VERSION 5.8 ;
BUSBITCHARS "[]" ;
DIVIDERCHAR "/" ;
UNITS
    DATABASE MICRONS 1000 ;
END UNITS

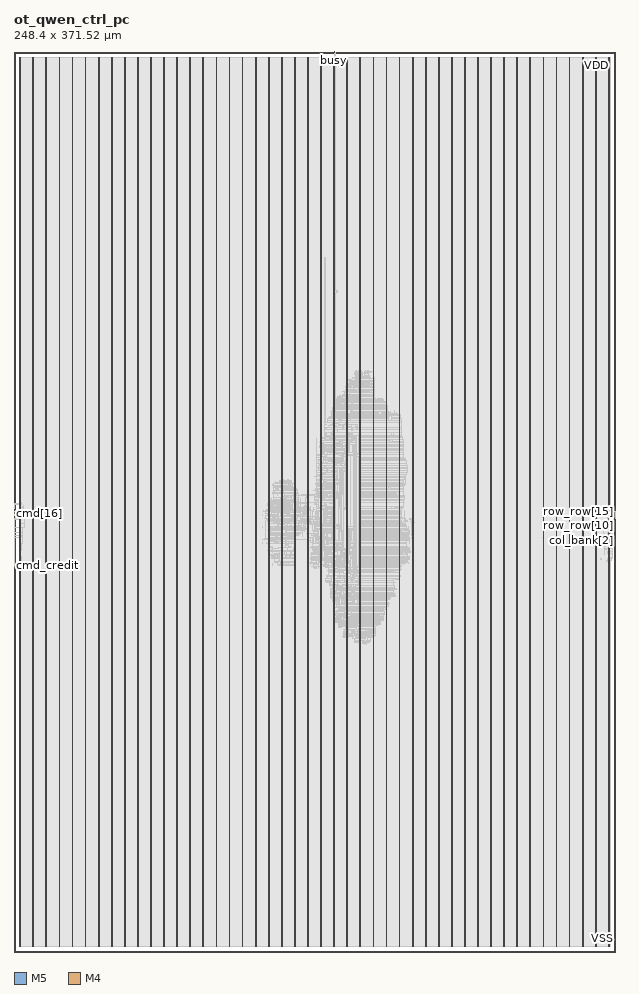
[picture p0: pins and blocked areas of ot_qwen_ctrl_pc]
MACRO ot_qwen_ctrl_pc
  FOREIGN ot_qwen_ctrl_pc 0 0 ;
  CLASS BLOCK ;
  SIZE 248.4 BY 371.52 ;
  PIN busy
    DIRECTION OUTPUT ;
    USE SIGNAL ;
    PORT
      LAYER M5 ;
        RECT  132.144 371.436 132.168 371.52 ;
    END
  END busy
  PIN clk
    DIRECTION INPUT ;
    USE SIGNAL ;
    PORT
      LAYER M5 ;
        RECT  132.24 371.436 132.264 371.52 ;
    END
  END clk
  PIN cmd[0]
    DIRECTION INPUT ;
    USE SIGNAL ;
    PORT
      LAYER M4 ;
        RECT  0 179.568 0.084 179.592 ;
    END
  END cmd[0]
  PIN cmd[10]
    DIRECTION INPUT ;
    USE SIGNAL ;
    PORT
      LAYER M4 ;
        RECT  0 180.528 0.084 180.552 ;
    END
  END cmd[10]
  PIN cmd[11]
    DIRECTION INPUT ;
    USE SIGNAL ;
    PORT
      LAYER M4 ;
        RECT  0 180.624 0.084 180.648 ;
    END
  END cmd[11]
  PIN cmd[12]
    DIRECTION INPUT ;
    USE SIGNAL ;
    PORT
      LAYER M4 ;
        RECT  0 180.72 0.084 180.744 ;
    END
  END cmd[12]
  PIN cmd[13]
    DIRECTION INPUT ;
    USE SIGNAL ;
    PORT
      LAYER M4 ;
        RECT  0 180.816 0.084 180.84 ;
    END
  END cmd[13]
  PIN cmd[14]
    DIRECTION INPUT ;
    USE SIGNAL ;
    PORT
      LAYER M4 ;
        RECT  0 180.912 0.084 180.936 ;
    END
  END cmd[14]
  PIN cmd[15]
    DIRECTION INPUT ;
    USE SIGNAL ;
    PORT
      LAYER M4 ;
        RECT  0 181.008 0.084 181.032 ;
    END
  END cmd[15]
  PIN cmd[16]
    DIRECTION INPUT ;
    USE SIGNAL ;
    PORT
      LAYER M4 ;
        RECT  0 181.104 0.084 181.128 ;
    END
  END cmd[16]
  PIN cmd[17]
    DIRECTION INPUT ;
    USE SIGNAL ;
    PORT
      LAYER M4 ;
        RECT  0 181.2 0.084 181.224 ;
    END
  END cmd[17]
  PIN cmd[18]
    DIRECTION INPUT ;
    USE SIGNAL ;
    PORT
      LAYER M4 ;
        RECT  0 181.296 0.084 181.32 ;
    END
  END cmd[18]
  PIN cmd[19]
    DIRECTION INPUT ;
    USE SIGNAL ;
    PORT
      LAYER M4 ;
        RECT  0 181.392 0.084 181.416 ;
    END
  END cmd[19]
  PIN cmd[1]
    DIRECTION INPUT ;
    USE SIGNAL ;
    PORT
      LAYER M4 ;
        RECT  0 179.664 0.084 179.688 ;
    END
  END cmd[1]
  PIN cmd[20]
    DIRECTION INPUT ;
    USE SIGNAL ;
    PORT
      LAYER M4 ;
        RECT  0 181.488 0.084 181.512 ;
    END
  END cmd[20]
  PIN cmd[21]
    DIRECTION INPUT ;
    USE SIGNAL ;
    PORT
      LAYER M4 ;
        RECT  0 181.584 0.084 181.608 ;
    END
  END cmd[21]
  PIN cmd[22]
    DIRECTION INPUT ;
    USE SIGNAL ;
    PORT
      LAYER M4 ;
        RECT  0 181.68 0.084 181.704 ;
    END
  END cmd[22]
  PIN cmd[23]
    DIRECTION INPUT ;
    USE SIGNAL ;
    PORT
      LAYER M4 ;
        RECT  0 181.776 0.084 181.8 ;
    END
  END cmd[23]
  PIN cmd[24]
    DIRECTION INPUT ;
    USE SIGNAL ;
    PORT
      LAYER M4 ;
        RECT  0 181.872 0.084 181.896 ;
    END
  END cmd[24]
  PIN cmd[25]
    DIRECTION INPUT ;
    USE SIGNAL ;
    PORT
      LAYER M4 ;
        RECT  0 181.968 0.084 181.992 ;
    END
  END cmd[25]
  PIN cmd[26]
    DIRECTION INPUT ;
    USE SIGNAL ;
    PORT
      LAYER M4 ;
        RECT  0 182.064 0.084 182.088 ;
    END
  END cmd[26]
  PIN cmd[27]
    DIRECTION INPUT ;
    USE SIGNAL ;
    PORT
      LAYER M4 ;
        RECT  0 182.16 0.084 182.184 ;
    END
  END cmd[27]
  PIN cmd[28]
    DIRECTION INPUT ;
    USE SIGNAL ;
    PORT
      LAYER M4 ;
        RECT  0 182.256 0.084 182.28 ;
    END
  END cmd[28]
  PIN cmd[29]
    DIRECTION INPUT ;
    USE SIGNAL ;
    PORT
      LAYER M4 ;
        RECT  0 182.352 0.084 182.376 ;
    END
  END cmd[29]
  PIN cmd[2]
    DIRECTION INPUT ;
    USE SIGNAL ;
    PORT
      LAYER M4 ;
        RECT  0 179.76 0.084 179.784 ;
    END
  END cmd[2]
  PIN cmd[30]
    DIRECTION INPUT ;
    USE SIGNAL ;
    PORT
      LAYER M4 ;
        RECT  0 182.448 0.084 182.472 ;
    END
  END cmd[30]
  PIN cmd[31]
    DIRECTION INPUT ;
    USE SIGNAL ;
    PORT
      LAYER M4 ;
        RECT  0 182.544 0.084 182.568 ;
    END
  END cmd[31]
  PIN cmd[3]
    DIRECTION INPUT ;
    USE SIGNAL ;
    PORT
      LAYER M4 ;
        RECT  0 179.856 0.084 179.88 ;
    END
  END cmd[3]
  PIN cmd[4]
    DIRECTION INPUT ;
    USE SIGNAL ;
    PORT
      LAYER M4 ;
        RECT  0 179.952 0.084 179.976 ;
    END
  END cmd[4]
  PIN cmd[5]
    DIRECTION INPUT ;
    USE SIGNAL ;
    PORT
      LAYER M4 ;
        RECT  0 180.048 0.084 180.072 ;
    END
  END cmd[5]
  PIN cmd[6]
    DIRECTION INPUT ;
    USE SIGNAL ;
    PORT
      LAYER M4 ;
        RECT  0 180.144 0.084 180.168 ;
    END
  END cmd[6]
  PIN cmd[7]
    DIRECTION INPUT ;
    USE SIGNAL ;
    PORT
      LAYER M4 ;
        RECT  0 180.24 0.084 180.264 ;
    END
  END cmd[7]
  PIN cmd[8]
    DIRECTION INPUT ;
    USE SIGNAL ;
    PORT
      LAYER M4 ;
        RECT  0 180.336 0.084 180.36 ;
    END
  END cmd[8]
  PIN cmd[9]
    DIRECTION INPUT ;
    USE SIGNAL ;
    PORT
      LAYER M4 ;
        RECT  0 180.432 0.084 180.456 ;
    END
  END cmd[9]
  PIN cmd_credit
    DIRECTION OUTPUT ;
    USE SIGNAL ;
    PORT
      LAYER M4 ;
        RECT  0 159.6 0.084 159.624 ;
    END
  END cmd_credit
  PIN cmd_v
    DIRECTION INPUT ;
    USE SIGNAL ;
    PORT
      LAYER M4 ;
        RECT  0 159.696 0.084 159.72 ;
    END
  END cmd_v
  PIN col_bank[0]
    DIRECTION OUTPUT ;
    USE SIGNAL ;
    PORT
      LAYER M4 ;
        RECT  248.316 169.68 248.4 169.704 ;
    END
  END col_bank[0]
  PIN col_bank[1]
    DIRECTION OUTPUT ;
    USE SIGNAL ;
    PORT
      LAYER M4 ;
        RECT  248.316 169.776 248.4 169.8 ;
    END
  END col_bank[1]
  PIN col_bank[2]
    DIRECTION OUTPUT ;
    USE SIGNAL ;
    PORT
      LAYER M4 ;
        RECT  248.316 169.872 248.4 169.896 ;
    END
  END col_bank[2]
  PIN col_bank[3]
    DIRECTION OUTPUT ;
    USE SIGNAL ;
    PORT
      LAYER M4 ;
        RECT  248.316 169.968 248.4 169.992 ;
    END
  END col_bank[3]
  PIN col_bank[4]
    DIRECTION OUTPUT ;
    USE SIGNAL ;
    PORT
      LAYER M4 ;
        RECT  248.316 170.064 248.4 170.088 ;
    END
  END col_bank[4]
  PIN col_col[0]
    DIRECTION OUTPUT ;
    USE SIGNAL ;
    PORT
      LAYER M4 ;
        RECT  248.316 170.16 248.4 170.184 ;
    END
  END col_col[0]
  PIN col_col[1]
    DIRECTION OUTPUT ;
    USE SIGNAL ;
    PORT
      LAYER M4 ;
        RECT  248.316 170.256 248.4 170.28 ;
    END
  END col_col[1]
  PIN col_col[2]
    DIRECTION OUTPUT ;
    USE SIGNAL ;
    PORT
      LAYER M4 ;
        RECT  248.316 170.352 248.4 170.376 ;
    END
  END col_col[2]
  PIN col_col[3]
    DIRECTION OUTPUT ;
    USE SIGNAL ;
    PORT
      LAYER M4 ;
        RECT  248.316 170.448 248.4 170.472 ;
    END
  END col_col[3]
  PIN col_col[4]
    DIRECTION OUTPUT ;
    USE SIGNAL ;
    PORT
      LAYER M4 ;
        RECT  248.316 170.544 248.4 170.568 ;
    END
  END col_col[4]
  PIN col_v
    DIRECTION OUTPUT ;
    USE SIGNAL ;
    PORT
      LAYER M4 ;
        RECT  248.316 170.64 248.4 170.664 ;
    END
  END col_v
  PIN col_we
    DIRECTION OUTPUT ;
    USE SIGNAL ;
    PORT
      LAYER M4 ;
        RECT  248.316 170.736 248.4 170.76 ;
    END
  END col_we
  PIN fault
    DIRECTION OUTPUT ;
    USE SIGNAL ;
    PORT
      LAYER M5 ;
        RECT  132.336 371.436 132.36 371.52 ;
    END
  END fault
  PIN read_credit[0]
    DIRECTION INPUT ;
    USE SIGNAL ;
    PORT
      LAYER M4 ;
        RECT  0 159.792 0.084 159.816 ;
    END
  END read_credit[0]
  PIN read_credit[1]
    DIRECTION INPUT ;
    USE SIGNAL ;
    PORT
      LAYER M4 ;
        RECT  0 159.888 0.084 159.912 ;
    END
  END read_credit[1]
  PIN read_credit[2]
    DIRECTION INPUT ;
    USE SIGNAL ;
    PORT
      LAYER M4 ;
        RECT  0 159.984 0.084 160.008 ;
    END
  END read_credit[2]
  PIN row_bank[0]
    DIRECTION OUTPUT ;
    USE SIGNAL ;
    PORT
      LAYER M4 ;
        RECT  248.316 170.832 248.4 170.856 ;
    END
  END row_bank[0]
  PIN row_bank[1]
    DIRECTION OUTPUT ;
    USE SIGNAL ;
    PORT
      LAYER M4 ;
        RECT  248.316 170.928 248.4 170.952 ;
    END
  END row_bank[1]
  PIN row_bank[2]
    DIRECTION OUTPUT ;
    USE SIGNAL ;
    PORT
      LAYER M4 ;
        RECT  248.316 171.024 248.4 171.048 ;
    END
  END row_bank[2]
  PIN row_bank[3]
    DIRECTION OUTPUT ;
    USE SIGNAL ;
    PORT
      LAYER M4 ;
        RECT  248.316 171.12 248.4 171.144 ;
    END
  END row_bank[3]
  PIN row_bank[4]
    DIRECTION OUTPUT ;
    USE SIGNAL ;
    PORT
      LAYER M4 ;
        RECT  248.316 171.216 248.4 171.24 ;
    END
  END row_bank[4]
  PIN row_op[0]
    DIRECTION OUTPUT ;
    USE SIGNAL ;
    PORT
      LAYER M4 ;
        RECT  248.316 171.312 248.4 171.336 ;
    END
  END row_op[0]
  PIN row_op[1]
    DIRECTION OUTPUT ;
    USE SIGNAL ;
    PORT
      LAYER M4 ;
        RECT  248.316 171.408 248.4 171.432 ;
    END
  END row_op[1]
  PIN row_op[2]
    DIRECTION OUTPUT ;
    USE SIGNAL ;
    PORT
      LAYER M4 ;
        RECT  248.316 171.504 248.4 171.528 ;
    END
  END row_op[2]
  PIN row_row[0]
    DIRECTION OUTPUT ;
    USE SIGNAL ;
    PORT
      LAYER M4 ;
        RECT  248.316 171.6 248.4 171.624 ;
    END
  END row_row[0]
  PIN row_row[10]
    DIRECTION OUTPUT ;
    USE SIGNAL ;
    PORT
      LAYER M4 ;
        RECT  248.316 172.56 248.4 172.584 ;
    END
  END row_row[10]
  PIN row_row[11]
    DIRECTION OUTPUT ;
    USE SIGNAL ;
    PORT
      LAYER M4 ;
        RECT  248.316 172.656 248.4 172.68 ;
    END
  END row_row[11]
  PIN row_row[12]
    DIRECTION OUTPUT ;
    USE SIGNAL ;
    PORT
      LAYER M4 ;
        RECT  248.316 178.128 248.4 178.152 ;
    END
  END row_row[12]
  PIN row_row[13]
    DIRECTION OUTPUT ;
    USE SIGNAL ;
    PORT
      LAYER M4 ;
        RECT  248.316 178.224 248.4 178.248 ;
    END
  END row_row[13]
  PIN row_row[14]
    DIRECTION OUTPUT ;
    USE SIGNAL ;
    PORT
      LAYER M4 ;
        RECT  248.316 178.32 248.4 178.344 ;
    END
  END row_row[14]
  PIN row_row[15]
    DIRECTION OUTPUT ;
    USE SIGNAL ;
    PORT
      LAYER M4 ;
        RECT  248.316 178.416 248.4 178.44 ;
    END
  END row_row[15]
  PIN row_row[16]
    DIRECTION OUTPUT ;
    USE SIGNAL ;
    PORT
      LAYER M4 ;
        RECT  248.316 178.512 248.4 178.536 ;
    END
  END row_row[16]
  PIN row_row[17]
    DIRECTION OUTPUT ;
    USE SIGNAL ;
    PORT
      LAYER M4 ;
        RECT  248.316 178.608 248.4 178.632 ;
    END
  END row_row[17]
  PIN row_row[18]
    DIRECTION OUTPUT ;
    USE SIGNAL ;
    PORT
      LAYER M4 ;
        RECT  248.316 178.704 248.4 178.728 ;
    END
  END row_row[18]
  PIN row_row[1]
    DIRECTION OUTPUT ;
    USE SIGNAL ;
    PORT
      LAYER M4 ;
        RECT  248.316 171.696 248.4 171.72 ;
    END
  END row_row[1]
  PIN row_row[2]
    DIRECTION OUTPUT ;
    USE SIGNAL ;
    PORT
      LAYER M4 ;
        RECT  248.316 171.792 248.4 171.816 ;
    END
  END row_row[2]
  PIN row_row[3]
    DIRECTION OUTPUT ;
    USE SIGNAL ;
    PORT
      LAYER M4 ;
        RECT  248.316 171.888 248.4 171.912 ;
    END
  END row_row[3]
  PIN row_row[4]
    DIRECTION OUTPUT ;
    USE SIGNAL ;
    PORT
      LAYER M4 ;
        RECT  248.316 171.984 248.4 172.008 ;
    END
  END row_row[4]
  PIN row_row[5]
    DIRECTION OUTPUT ;
    USE SIGNAL ;
    PORT
      LAYER M4 ;
        RECT  248.316 172.08 248.4 172.104 ;
    END
  END row_row[5]
  PIN row_row[6]
    DIRECTION OUTPUT ;
    USE SIGNAL ;
    PORT
      LAYER M4 ;
        RECT  248.316 172.176 248.4 172.2 ;
    END
  END row_row[6]
  PIN row_row[7]
    DIRECTION OUTPUT ;
    USE SIGNAL ;
    PORT
      LAYER M4 ;
        RECT  248.316 172.272 248.4 172.296 ;
    END
  END row_row[7]
  PIN row_row[8]
    DIRECTION OUTPUT ;
    USE SIGNAL ;
    PORT
      LAYER M4 ;
        RECT  248.316 172.368 248.4 172.392 ;
    END
  END row_row[8]
  PIN row_row[9]
    DIRECTION OUTPUT ;
    USE SIGNAL ;
    PORT
      LAYER M4 ;
        RECT  248.316 172.464 248.4 172.488 ;
    END
  END row_row[9]
  PIN row_v
    DIRECTION OUTPUT ;
    USE SIGNAL ;
    PORT
      LAYER M4 ;
        RECT  248.316 178.8 248.4 178.824 ;
    END
  END row_v
  PIN rst_n
    DIRECTION INPUT ;
    USE SIGNAL ;
    PORT
      LAYER M5 ;
        RECT  132.432 371.436 132.456 371.52 ;
    END
  END rst_n
  PIN VDD
    DIRECTION INOUT ;
    USE POWER ;
    PORT
      LAYER M5 ;
        RECT  245.592 2.151 245.712 369.369 ;
        RECT  240.192 2.151 240.312 369.369 ;
        RECT  234.792 2.151 234.912 369.369 ;
        RECT  229.392 2.151 229.512 369.369 ;
        RECT  223.992 2.151 224.112 369.369 ;
        RECT  218.592 2.151 218.712 369.369 ;
        RECT  213.192 2.151 213.312 369.369 ;
        RECT  207.792 2.151 207.912 369.369 ;
        RECT  202.392 2.151 202.512 369.369 ;
        RECT  196.992 2.151 197.112 369.369 ;
        RECT  191.592 2.151 191.712 369.369 ;
        RECT  186.192 2.151 186.312 369.369 ;
        RECT  180.792 2.151 180.912 369.369 ;
        RECT  175.392 2.151 175.512 369.369 ;
        RECT  169.992 2.151 170.112 369.369 ;
        RECT  164.592 2.151 164.712 369.369 ;
        RECT  159.192 2.151 159.312 369.369 ;
        RECT  153.792 2.151 153.912 369.369 ;
        RECT  148.392 2.151 148.512 369.369 ;
        RECT  142.992 2.151 143.112 369.369 ;
        RECT  137.592 2.151 137.712 369.369 ;
        RECT  132.192 2.151 132.312 369.369 ;
        RECT  126.792 2.151 126.912 369.369 ;
        RECT  121.392 2.151 121.512 369.369 ;
        RECT  115.992 2.151 116.112 369.369 ;
        RECT  110.592 2.151 110.712 369.369 ;
        RECT  105.192 2.151 105.312 369.369 ;
        RECT  99.792 2.151 99.912 369.369 ;
        RECT  94.392 2.151 94.512 369.369 ;
        RECT  88.992 2.151 89.112 369.369 ;
        RECT  83.592 2.151 83.712 369.369 ;
        RECT  78.192 2.151 78.312 369.369 ;
        RECT  72.792 2.151 72.912 369.369 ;
        RECT  67.392 2.151 67.512 369.369 ;
        RECT  61.992 2.151 62.112 369.369 ;
        RECT  56.592 2.151 56.712 369.369 ;
        RECT  51.192 2.151 51.312 369.369 ;
        RECT  45.792 2.151 45.912 369.369 ;
        RECT  40.392 2.151 40.512 369.369 ;
        RECT  34.992 2.151 35.112 369.369 ;
        RECT  29.592 2.151 29.712 369.369 ;
        RECT  24.192 2.151 24.312 369.369 ;
        RECT  18.792 2.151 18.912 369.369 ;
        RECT  13.392 2.151 13.512 369.369 ;
        RECT  7.992 2.151 8.112 369.369 ;
        RECT  2.592 2.151 2.712 369.369 ;
    END
  END VDD
  PIN VSS
    DIRECTION INOUT ;
    USE GROUND ;
    PORT
      LAYER M5 ;
        RECT  245.4 2.137 245.52 369.383 ;
        RECT  240 2.137 240.12 369.383 ;
        RECT  234.6 2.137 234.72 369.383 ;
        RECT  229.2 2.137 229.32 369.383 ;
        RECT  223.8 2.137 223.92 369.383 ;
        RECT  218.4 2.137 218.52 369.383 ;
        RECT  213 2.137 213.12 369.383 ;
        RECT  207.6 2.137 207.72 369.383 ;
        RECT  202.2 2.137 202.32 369.383 ;
        RECT  196.8 2.137 196.92 369.383 ;
        RECT  191.4 2.137 191.52 369.383 ;
        RECT  186 2.137 186.12 369.383 ;
        RECT  180.6 2.137 180.72 369.383 ;
        RECT  175.2 2.137 175.32 369.383 ;
        RECT  169.8 2.137 169.92 369.383 ;
        RECT  164.4 2.137 164.52 369.383 ;
        RECT  159 2.137 159.12 369.383 ;
        RECT  153.6 2.137 153.72 369.383 ;
        RECT  148.2 2.137 148.32 369.383 ;
        RECT  142.8 2.137 142.92 369.383 ;
        RECT  137.4 2.137 137.52 369.383 ;
        RECT  132 2.137 132.12 369.383 ;
        RECT  126.6 2.137 126.72 369.383 ;
        RECT  121.2 2.137 121.32 369.383 ;
        RECT  115.8 2.137 115.92 369.383 ;
        RECT  110.4 2.137 110.52 369.383 ;
        RECT  105 2.137 105.12 369.383 ;
        RECT  99.6 2.137 99.72 369.383 ;
        RECT  94.2 2.137 94.32 369.383 ;
        RECT  88.8 2.137 88.92 369.383 ;
        RECT  83.4 2.137 83.52 369.383 ;
        RECT  78 2.137 78.12 369.383 ;
        RECT  72.6 2.137 72.72 369.383 ;
        RECT  67.2 2.137 67.32 369.383 ;
        RECT  61.8 2.137 61.92 369.383 ;
        RECT  56.4 2.137 56.52 369.383 ;
        RECT  51 2.137 51.12 369.383 ;
        RECT  45.6 2.137 45.72 369.383 ;
        RECT  40.2 2.137 40.32 369.383 ;
        RECT  34.8 2.137 34.92 369.383 ;
        RECT  29.4 2.137 29.52 369.383 ;
        RECT  24 2.137 24.12 369.383 ;
        RECT  18.6 2.137 18.72 369.383 ;
        RECT  13.2 2.137 13.32 369.383 ;
        RECT  7.8 2.137 7.92 369.383 ;
        RECT  2.4 2.137 2.52 369.383 ;
    END
  END VSS
  OBS
    LAYER RVTN ;
     RECT  2.16 2.16 246.24 2.295 ;
     RECT  2.16 2.565 246.24 2.835 ;
     RECT  2.16 3.105 246.24 3.375 ;
     RECT  2.16 3.645 246.24 3.915 ;
     RECT  2.16 4.185 246.24 4.455 ;
     RECT  2.16 4.725 246.24 4.995 ;
     RECT  2.16 5.265 246.24 5.535 ;
     RECT  2.16 5.805 246.24 6.075 ;
     RECT  2.16 6.345 246.24 6.615 ;
     RECT  2.16 6.885 246.24 7.155 ;
     RECT  2.16 7.425 246.24 7.695 ;
     RECT  2.16 7.965 246.24 8.235 ;
     RECT  2.16 8.505 246.24 8.775 ;
     RECT  2.16 9.045 246.24 9.315 ;
     RECT  2.16 9.585 246.24 9.855 ;
     RECT  2.16 10.125 246.24 10.395 ;
     RECT  2.16 10.665 246.24 10.935 ;
     RECT  2.16 11.205 246.24 11.475 ;
     RECT  2.16 11.745 246.24 12.015 ;
     RECT  2.16 12.285 246.24 12.555 ;
     RECT  2.16 12.825 246.24 13.095 ;
     RECT  2.16 13.365 246.24 13.635 ;
     RECT  2.16 13.905 246.24 14.175 ;
     RECT  2.16 14.445 246.24 14.715 ;
     RECT  2.16 14.985 246.24 15.255 ;
     RECT  2.16 15.525 246.24 15.795 ;
     RECT  2.16 16.065 246.24 16.335 ;
     RECT  2.16 16.605 246.24 16.875 ;
     RECT  2.16 17.145 246.24 17.415 ;
     RECT  2.16 17.685 246.24 17.955 ;
     RECT  2.16 18.225 246.24 18.495 ;
     RECT  2.16 18.765 246.24 19.035 ;
     RECT  2.16 19.305 246.24 19.575 ;
     RECT  2.16 19.845 246.24 20.115 ;
     RECT  2.16 20.385 246.24 20.655 ;
     RECT  2.16 20.925 246.24 21.195 ;
     RECT  2.16 21.465 246.24 21.735 ;
     RECT  2.16 22.005 246.24 22.275 ;
     RECT  2.16 22.545 246.24 22.815 ;
     RECT  2.16 23.085 246.24 23.355 ;
     RECT  2.16 23.625 246.24 23.895 ;
     RECT  2.16 24.165 246.24 24.435 ;
     RECT  2.16 24.705 246.24 24.975 ;
     RECT  2.16 25.245 246.24 25.515 ;
     RECT  2.16 25.785 246.24 26.055 ;
     RECT  2.16 26.325 246.24 26.595 ;
     RECT  2.16 26.865 246.24 27.135 ;
     RECT  2.16 27.405 246.24 27.675 ;
     RECT  2.16 27.945 246.24 28.215 ;
     RECT  2.16 28.485 246.24 28.755 ;
     RECT  2.16 29.025 246.24 29.295 ;
     RECT  2.16 29.565 246.24 29.835 ;
     RECT  2.16 30.105 246.24 30.375 ;
     RECT  2.16 30.645 246.24 30.915 ;
     RECT  2.16 31.185 246.24 31.455 ;
     RECT  2.16 31.725 246.24 31.995 ;
     RECT  2.16 32.265 246.24 32.535 ;
     RECT  2.16 32.805 246.24 33.075 ;
     RECT  2.16 33.345 246.24 33.615 ;
     RECT  2.16 33.885 246.24 34.155 ;
     RECT  2.16 34.425 246.24 34.695 ;
     RECT  2.16 34.965 246.24 35.235 ;
     RECT  2.16 35.505 246.24 35.775 ;
     RECT  2.16 36.045 246.24 36.315 ;
     RECT  2.16 36.585 246.24 36.855 ;
     RECT  2.16 37.125 246.24 37.395 ;
     RECT  2.16 37.665 246.24 37.935 ;
     RECT  2.16 38.205 246.24 38.475 ;
     RECT  2.16 38.745 246.24 39.015 ;
     RECT  2.16 39.285 246.24 39.555 ;
     RECT  2.16 39.825 246.24 40.095 ;
     RECT  2.16 40.365 246.24 40.635 ;
     RECT  2.16 40.905 246.24 41.175 ;
     RECT  2.16 41.445 246.24 41.715 ;
     RECT  2.16 41.985 246.24 42.255 ;
     RECT  2.16 42.525 246.24 42.795 ;
     RECT  2.16 43.065 246.24 43.335 ;
     RECT  2.16 43.605 246.24 43.875 ;
     RECT  2.16 44.145 246.24 44.415 ;
     RECT  2.16 44.685 246.24 44.955 ;
     RECT  2.16 45.225 246.24 45.495 ;
     RECT  2.16 45.765 246.24 46.035 ;
     RECT  2.16 46.305 246.24 46.575 ;
     RECT  2.16 46.845 246.24 47.115 ;
     RECT  2.16 47.385 246.24 47.655 ;
     RECT  2.16 47.925 246.24 48.195 ;
     RECT  2.16 48.465 246.24 48.735 ;
     RECT  2.16 49.005 246.24 49.275 ;
     RECT  2.16 49.545 246.24 49.815 ;
     RECT  2.16 50.085 246.24 50.355 ;
     RECT  2.16 50.625 246.24 50.895 ;
     RECT  2.16 51.165 246.24 51.435 ;
     RECT  2.16 51.705 246.24 51.975 ;
     RECT  2.16 52.245 246.24 52.515 ;
     RECT  2.16 52.785 246.24 53.055 ;
     RECT  2.16 53.325 246.24 53.595 ;
     RECT  2.16 53.865 246.24 54.135 ;
     RECT  2.16 54.405 246.24 54.675 ;
     RECT  2.16 54.945 246.24 55.215 ;
     RECT  2.16 55.485 246.24 55.755 ;
     RECT  2.16 56.025 246.24 56.295 ;
     RECT  2.16 56.565 246.24 56.835 ;
     RECT  2.16 57.105 246.24 57.375 ;
     RECT  2.16 57.645 246.24 57.915 ;
     RECT  2.16 58.185 246.24 58.455 ;
     RECT  2.16 58.725 246.24 58.995 ;
     RECT  2.16 59.265 246.24 59.535 ;
     RECT  2.16 59.805 246.24 60.075 ;
     RECT  2.16 60.345 246.24 60.615 ;
     RECT  2.16 60.885 246.24 61.155 ;
     RECT  2.16 61.425 246.24 61.695 ;
     RECT  2.16 61.965 246.24 62.235 ;
     RECT  2.16 62.505 246.24 62.775 ;
     RECT  2.16 63.045 246.24 63.315 ;
     RECT  2.16 63.585 246.24 63.855 ;
     RECT  2.16 64.125 246.24 64.395 ;
     RECT  2.16 64.665 246.24 64.935 ;
     RECT  2.16 65.205 246.24 65.475 ;
     RECT  2.16 65.745 246.24 66.015 ;
     RECT  2.16 66.285 246.24 66.555 ;
     RECT  2.16 66.825 246.24 67.095 ;
     RECT  2.16 67.365 246.24 67.635 ;
     RECT  2.16 67.905 246.24 68.175 ;
     RECT  2.16 68.445 246.24 68.715 ;
     RECT  2.16 68.985 246.24 69.255 ;
     RECT  2.16 69.525 246.24 69.795 ;
     RECT  2.16 70.065 246.24 70.335 ;
     RECT  2.16 70.605 246.24 70.875 ;
     RECT  2.16 71.145 246.24 71.415 ;
     RECT  2.16 71.685 246.24 71.955 ;
     RECT  2.16 72.225 246.24 72.495 ;
     RECT  2.16 72.765 246.24 73.035 ;
     RECT  2.16 73.305 246.24 73.575 ;
     RECT  2.16 73.845 246.24 74.115 ;
     RECT  2.16 74.385 246.24 74.655 ;
     RECT  2.16 74.925 246.24 75.195 ;
     RECT  2.16 75.465 246.24 75.735 ;
     RECT  2.16 76.005 246.24 76.275 ;
     RECT  2.16 76.545 246.24 76.815 ;
     RECT  2.16 77.085 246.24 77.355 ;
     RECT  2.16 77.625 246.24 77.895 ;
     RECT  2.16 78.165 246.24 78.435 ;
     RECT  2.16 78.705 246.24 78.975 ;
     RECT  2.16 79.245 246.24 79.515 ;
     RECT  2.16 79.785 246.24 80.055 ;
     RECT  2.16 80.325 246.24 80.595 ;
     RECT  2.16 80.865 246.24 81.135 ;
     RECT  2.16 81.405 246.24 81.675 ;
     RECT  2.16 81.945 246.24 82.215 ;
     RECT  2.16 82.485 246.24 82.755 ;
     RECT  2.16 83.025 246.24 83.295 ;
     RECT  2.16 83.565 246.24 83.835 ;
     RECT  2.16 84.105 246.24 84.375 ;
     RECT  2.16 84.645 246.24 84.915 ;
     RECT  2.16 85.185 246.24 85.455 ;
     RECT  2.16 85.725 246.24 85.995 ;
     RECT  2.16 86.265 246.24 86.535 ;
     RECT  2.16 86.805 246.24 87.075 ;
     RECT  2.16 87.345 246.24 87.615 ;
     RECT  2.16 87.885 246.24 88.155 ;
     RECT  2.16 88.425 246.24 88.695 ;
     RECT  2.16 88.965 246.24 89.235 ;
     RECT  2.16 89.505 246.24 89.775 ;
     RECT  2.16 90.045 246.24 90.315 ;
     RECT  2.16 90.585 246.24 90.855 ;
     RECT  2.16 91.125 246.24 91.395 ;
     RECT  2.16 91.665 246.24 91.935 ;
     RECT  2.16 92.205 246.24 92.475 ;
     RECT  2.16 92.745 246.24 93.015 ;
     RECT  2.16 93.285 246.24 93.555 ;
     RECT  2.16 93.825 246.24 94.095 ;
     RECT  2.16 94.365 246.24 94.635 ;
     RECT  2.16 94.905 246.24 95.175 ;
     RECT  2.16 95.445 246.24 95.715 ;
     RECT  2.16 95.985 246.24 96.255 ;
     RECT  2.16 96.525 246.24 96.795 ;
     RECT  2.16 97.065 246.24 97.335 ;
     RECT  2.16 97.605 246.24 97.875 ;
     RECT  2.16 98.145 246.24 98.415 ;
     RECT  2.16 98.685 246.24 98.955 ;
     RECT  2.16 99.225 246.24 99.495 ;
     RECT  2.16 99.765 246.24 100.035 ;
     RECT  2.16 100.305 246.24 100.575 ;
     RECT  2.16 100.845 246.24 101.115 ;
     RECT  2.16 101.385 246.24 101.655 ;
     RECT  2.16 101.925 246.24 102.195 ;
     RECT  2.16 102.465 246.24 102.735 ;
     RECT  2.16 103.005 246.24 103.275 ;
     RECT  2.16 103.545 246.24 103.815 ;
     RECT  2.16 104.085 246.24 104.355 ;
     RECT  2.16 104.625 246.24 104.895 ;
     RECT  2.16 105.165 246.24 105.435 ;
     RECT  2.16 105.705 246.24 105.975 ;
     RECT  2.16 106.245 246.24 106.515 ;
     RECT  2.16 106.785 246.24 107.055 ;
     RECT  2.16 107.325 246.24 107.595 ;
     RECT  2.16 107.865 246.24 108.135 ;
     RECT  2.16 108.405 246.24 108.675 ;
     RECT  2.16 108.945 246.24 109.215 ;
     RECT  2.16 109.485 246.24 109.755 ;
     RECT  2.16 110.025 246.24 110.295 ;
     RECT  2.16 110.565 246.24 110.835 ;
     RECT  2.16 111.105 246.24 111.375 ;
     RECT  2.16 111.645 246.24 111.915 ;
     RECT  2.16 112.185 246.24 112.455 ;
     RECT  2.16 112.725 246.24 112.995 ;
     RECT  2.16 113.265 246.24 113.535 ;
     RECT  2.16 113.805 246.24 114.075 ;
     RECT  2.16 114.345 246.24 114.615 ;
     RECT  2.16 114.885 246.24 115.155 ;
     RECT  2.16 115.425 246.24 115.695 ;
     RECT  2.16 115.965 246.24 116.235 ;
     RECT  2.16 116.505 246.24 116.775 ;
     RECT  2.16 117.045 246.24 117.315 ;
     RECT  2.16 117.585 246.24 117.855 ;
     RECT  2.16 118.125 246.24 118.395 ;
     RECT  2.16 118.665 246.24 118.935 ;
     RECT  2.16 119.205 246.24 119.475 ;
     RECT  2.16 119.745 246.24 120.015 ;
     RECT  2.16 120.285 246.24 120.555 ;
     RECT  2.16 120.825 246.24 121.095 ;
     RECT  2.16 121.365 246.24 121.635 ;
     RECT  2.16 121.905 246.24 122.175 ;
     RECT  2.16 122.445 246.24 122.715 ;
     RECT  2.16 122.985 246.24 123.255 ;
     RECT  2.16 123.525 246.24 123.795 ;
     RECT  2.16 124.065 246.24 124.335 ;
     RECT  2.16 124.605 246.24 124.875 ;
     RECT  2.16 125.145 246.24 125.415 ;
     RECT  2.16 125.685 246.24 125.955 ;
     RECT  2.16 126.225 246.24 126.495 ;
     RECT  2.16 126.765 246.24 127.035 ;
     RECT  2.16 127.305 246.24 127.575 ;
     RECT  2.16 127.845 246.24 128.115 ;
     RECT  2.16 128.385 246.24 128.655 ;
     RECT  2.16 128.925 246.24 129.195 ;
     RECT  2.16 129.465 246.24 129.735 ;
     RECT  2.16 130.005 246.24 130.275 ;
     RECT  2.16 130.545 246.24 130.815 ;
     RECT  2.16 131.085 246.24 131.355 ;
     RECT  2.16 131.625 246.24 131.895 ;
     RECT  2.16 132.165 246.24 132.435 ;
     RECT  2.16 132.705 246.24 132.975 ;
     RECT  2.16 133.245 246.24 133.515 ;
     RECT  2.16 133.785 246.24 134.055 ;
     RECT  2.16 134.325 246.24 134.595 ;
     RECT  2.16 134.865 246.24 135.135 ;
     RECT  2.16 135.405 246.24 135.675 ;
     RECT  2.16 135.945 246.24 136.215 ;
     RECT  2.16 136.485 246.24 136.755 ;
     RECT  2.16 137.025 246.24 137.295 ;
     RECT  2.16 137.565 246.24 137.835 ;
     RECT  2.16 138.105 246.24 138.375 ;
     RECT  2.16 138.645 246.24 138.915 ;
     RECT  2.16 139.185 246.24 139.455 ;
     RECT  2.16 139.725 246.24 139.995 ;
     RECT  2.16 140.265 246.24 140.535 ;
     RECT  2.16 140.805 246.24 141.075 ;
     RECT  2.16 141.345 246.24 141.615 ;
     RECT  2.16 141.885 246.24 142.155 ;
     RECT  2.16 142.425 246.24 142.695 ;
     RECT  2.16 142.965 246.24 143.235 ;
     RECT  2.16 143.505 246.24 143.775 ;
     RECT  2.16 144.045 246.24 144.315 ;
     RECT  2.16 144.585 246.24 144.855 ;
     RECT  2.16 145.125 246.24 145.395 ;
     RECT  2.16 145.665 246.24 145.935 ;
     RECT  2.16 146.205 246.24 146.475 ;
     RECT  2.16 146.745 246.24 147.015 ;
     RECT  2.16 147.285 246.24 147.555 ;
     RECT  2.16 147.825 246.24 148.095 ;
     RECT  2.16 148.365 246.24 148.635 ;
     RECT  2.16 148.905 246.24 149.175 ;
     RECT  2.16 149.445 246.24 149.715 ;
     RECT  2.16 149.985 246.24 150.255 ;
     RECT  2.16 150.525 246.24 150.795 ;
     RECT  2.16 151.065 246.24 151.335 ;
     RECT  2.16 151.605 246.24 151.875 ;
     RECT  2.16 152.145 246.24 152.415 ;
     RECT  2.16 152.685 246.24 152.955 ;
     RECT  2.16 153.225 246.24 153.495 ;
     RECT  2.16 153.765 246.24 154.035 ;
     RECT  2.16 154.305 246.24 154.575 ;
     RECT  2.16 154.845 246.24 155.115 ;
     RECT  2.16 155.385 246.24 155.655 ;
     RECT  2.16 155.925 246.24 156.195 ;
     RECT  2.16 156.465 246.24 156.735 ;
     RECT  2.16 157.005 246.24 157.275 ;
     RECT  2.16 157.545 246.24 157.815 ;
     RECT  2.16 158.085 246.24 158.355 ;
     RECT  2.16 158.625 246.24 158.895 ;
     RECT  2.16 159.165 246.24 159.435 ;
     RECT  2.16 159.705 246.24 159.975 ;
     RECT  2.16 160.245 246.24 160.515 ;
     RECT  2.16 160.785 246.24 161.055 ;
     RECT  2.16 161.325 246.24 161.595 ;
     RECT  2.16 161.865 246.24 162.135 ;
     RECT  2.16 162.405 246.24 162.675 ;
     RECT  2.16 162.945 246.24 163.215 ;
     RECT  2.16 163.485 246.24 163.755 ;
     RECT  2.16 164.025 246.24 164.295 ;
     RECT  2.16 164.565 246.24 164.835 ;
     RECT  2.16 165.105 246.24 165.375 ;
     RECT  2.16 165.645 246.24 165.915 ;
     RECT  2.16 166.185 246.24 166.455 ;
     RECT  2.16 166.725 246.24 166.995 ;
     RECT  2.16 167.265 246.24 167.535 ;
     RECT  2.16 167.805 246.24 168.075 ;
     RECT  2.16 168.345 246.24 168.615 ;
     RECT  2.16 168.885 246.24 169.155 ;
     RECT  2.16 169.425 246.24 169.695 ;
     RECT  2.16 169.965 246.24 170.235 ;
     RECT  2.16 170.505 246.24 170.775 ;
     RECT  2.16 171.045 246.24 171.315 ;
     RECT  2.16 171.585 246.24 171.855 ;
     RECT  2.16 172.125 246.24 172.395 ;
     RECT  2.16 172.665 246.24 172.935 ;
     RECT  2.16 173.205 246.24 173.475 ;
     RECT  2.16 173.745 246.24 174.015 ;
     RECT  2.16 174.285 246.24 174.555 ;
     RECT  2.16 174.825 246.24 175.095 ;
     RECT  2.16 175.365 246.24 175.635 ;
     RECT  2.16 175.905 246.24 176.175 ;
     RECT  2.16 176.445 246.24 176.715 ;
     RECT  2.16 176.985 246.24 177.255 ;
     RECT  2.16 177.525 246.24 177.795 ;
     RECT  2.16 178.065 246.24 178.335 ;
     RECT  2.16 178.605 246.24 178.875 ;
     RECT  2.16 179.145 246.24 179.415 ;
     RECT  2.16 179.685 246.24 179.955 ;
     RECT  2.16 180.225 246.24 180.495 ;
     RECT  2.16 180.765 246.24 181.035 ;
     RECT  2.16 181.305 246.24 181.575 ;
     RECT  2.16 181.845 246.24 182.115 ;
     RECT  2.16 182.385 246.24 182.655 ;
     RECT  2.16 182.925 246.24 183.195 ;
     RECT  2.16 183.465 246.24 183.735 ;
     RECT  2.16 184.005 246.24 184.275 ;
     RECT  2.16 184.545 246.24 184.815 ;
     RECT  2.16 185.085 246.24 185.355 ;
     RECT  2.16 185.625 246.24 185.895 ;
     RECT  2.16 186.165 246.24 186.435 ;
     RECT  2.16 186.705 246.24 186.975 ;
     RECT  2.16 187.245 246.24 187.515 ;
     RECT  2.16 187.785 246.24 188.055 ;
     RECT  2.16 188.325 246.24 188.595 ;
     RECT  2.16 188.865 246.24 189.135 ;
     RECT  2.16 189.405 246.24 189.675 ;
     RECT  2.16 189.945 246.24 190.215 ;
     RECT  2.16 190.485 246.24 190.755 ;
     RECT  2.16 191.025 246.24 191.295 ;
     RECT  2.16 191.565 246.24 191.835 ;
     RECT  2.16 192.105 246.24 192.375 ;
     RECT  2.16 192.645 246.24 192.915 ;
     RECT  2.16 193.185 246.24 193.455 ;
     RECT  2.16 193.725 246.24 193.995 ;
     RECT  2.16 194.265 246.24 194.535 ;
     RECT  2.16 194.805 246.24 195.075 ;
     RECT  2.16 195.345 246.24 195.615 ;
     RECT  2.16 195.885 246.24 196.155 ;
     RECT  2.16 196.425 246.24 196.695 ;
     RECT  2.16 196.965 246.24 197.235 ;
     RECT  2.16 197.505 246.24 197.775 ;
     RECT  2.16 198.045 246.24 198.315 ;
     RECT  2.16 198.585 246.24 198.855 ;
     RECT  2.16 199.125 246.24 199.395 ;
     RECT  2.16 199.665 246.24 199.935 ;
     RECT  2.16 200.205 246.24 200.475 ;
     RECT  2.16 200.745 246.24 201.015 ;
     RECT  2.16 201.285 246.24 201.555 ;
     RECT  2.16 201.825 246.24 202.095 ;
     RECT  2.16 202.365 246.24 202.635 ;
     RECT  2.16 202.905 246.24 203.175 ;
     RECT  2.16 203.445 246.24 203.715 ;
     RECT  2.16 203.985 246.24 204.255 ;
     RECT  2.16 204.525 246.24 204.795 ;
     RECT  2.16 205.065 246.24 205.335 ;
     RECT  2.16 205.605 246.24 205.875 ;
     RECT  2.16 206.145 246.24 206.415 ;
     RECT  2.16 206.685 246.24 206.955 ;
     RECT  2.16 207.225 246.24 207.495 ;
     RECT  2.16 207.765 246.24 208.035 ;
     RECT  2.16 208.305 246.24 208.575 ;
     RECT  2.16 208.845 246.24 209.115 ;
     RECT  2.16 209.385 246.24 209.655 ;
     RECT  2.16 209.925 246.24 210.195 ;
     RECT  2.16 210.465 246.24 210.735 ;
     RECT  2.16 211.005 246.24 211.275 ;
     RECT  2.16 211.545 246.24 211.815 ;
     RECT  2.16 212.085 246.24 212.355 ;
     RECT  2.16 212.625 246.24 212.895 ;
     RECT  2.16 213.165 246.24 213.435 ;
     RECT  2.16 213.705 246.24 213.975 ;
     RECT  2.16 214.245 246.24 214.515 ;
     RECT  2.16 214.785 246.24 215.055 ;
     RECT  2.16 215.325 246.24 215.595 ;
     RECT  2.16 215.865 246.24 216.135 ;
     RECT  2.16 216.405 246.24 216.675 ;
     RECT  2.16 216.945 246.24 217.215 ;
     RECT  2.16 217.485 246.24 217.755 ;
     RECT  2.16 218.025 246.24 218.295 ;
     RECT  2.16 218.565 246.24 218.835 ;
     RECT  2.16 219.105 246.24 219.375 ;
     RECT  2.16 219.645 246.24 219.915 ;
     RECT  2.16 220.185 246.24 220.455 ;
     RECT  2.16 220.725 246.24 220.995 ;
     RECT  2.16 221.265 246.24 221.535 ;
     RECT  2.16 221.805 246.24 222.075 ;
     RECT  2.16 222.345 246.24 222.615 ;
     RECT  2.16 222.885 246.24 223.155 ;
     RECT  2.16 223.425 246.24 223.695 ;
     RECT  2.16 223.965 246.24 224.235 ;
     RECT  2.16 224.505 246.24 224.775 ;
     RECT  2.16 225.045 246.24 225.315 ;
     RECT  2.16 225.585 246.24 225.855 ;
     RECT  2.16 226.125 246.24 226.395 ;
     RECT  2.16 226.665 246.24 226.935 ;
     RECT  2.16 227.205 246.24 227.475 ;
     RECT  2.16 227.745 246.24 228.015 ;
     RECT  2.16 228.285 246.24 228.555 ;
     RECT  2.16 228.825 246.24 229.095 ;
     RECT  2.16 229.365 246.24 229.635 ;
     RECT  2.16 229.905 246.24 230.175 ;
     RECT  2.16 230.445 246.24 230.715 ;
     RECT  2.16 230.985 246.24 231.255 ;
     RECT  2.16 231.525 246.24 231.795 ;
     RECT  2.16 232.065 246.24 232.335 ;
     RECT  2.16 232.605 246.24 232.875 ;
     RECT  2.16 233.145 246.24 233.415 ;
     RECT  2.16 233.685 246.24 233.955 ;
     RECT  2.16 234.225 246.24 234.495 ;
     RECT  2.16 234.765 246.24 235.035 ;
     RECT  2.16 235.305 246.24 235.575 ;
     RECT  2.16 235.845 246.24 236.115 ;
     RECT  2.16 236.385 246.24 236.655 ;
     RECT  2.16 236.925 246.24 237.195 ;
     RECT  2.16 237.465 246.24 237.735 ;
     RECT  2.16 238.005 246.24 238.275 ;
     RECT  2.16 238.545 246.24 238.815 ;
     RECT  2.16 239.085 246.24 239.355 ;
     RECT  2.16 239.625 246.24 239.895 ;
     RECT  2.16 240.165 246.24 240.435 ;
     RECT  2.16 240.705 246.24 240.975 ;
     RECT  2.16 241.245 246.24 241.515 ;
     RECT  2.16 241.785 246.24 242.055 ;
     RECT  2.16 242.325 246.24 242.595 ;
     RECT  2.16 242.865 246.24 243.135 ;
     RECT  2.16 243.405 246.24 243.675 ;
     RECT  2.16 243.945 246.24 244.215 ;
     RECT  2.16 244.485 246.24 244.755 ;
     RECT  2.16 245.025 246.24 245.295 ;
     RECT  2.16 245.565 246.24 245.835 ;
     RECT  2.16 246.105 246.24 246.375 ;
     RECT  2.16 246.645 246.24 246.915 ;
     RECT  2.16 247.185 246.24 247.455 ;
     RECT  2.16 247.725 246.24 247.995 ;
     RECT  2.16 248.265 246.24 248.535 ;
     RECT  2.16 248.805 246.24 249.075 ;
     RECT  2.16 249.345 246.24 249.615 ;
     RECT  2.16 249.885 246.24 250.155 ;
     RECT  2.16 250.425 246.24 250.695 ;
     RECT  2.16 250.965 246.24 251.235 ;
     RECT  2.16 251.505 246.24 251.775 ;
     RECT  2.16 252.045 246.24 252.315 ;
     RECT  2.16 252.585 246.24 252.855 ;
     RECT  2.16 253.125 246.24 253.395 ;
     RECT  2.16 253.665 246.24 253.935 ;
     RECT  2.16 254.205 246.24 254.475 ;
     RECT  2.16 254.745 246.24 255.015 ;
     RECT  2.16 255.285 246.24 255.555 ;
     RECT  2.16 255.825 246.24 256.095 ;
     RECT  2.16 256.365 246.24 256.635 ;
     RECT  2.16 256.905 246.24 257.175 ;
     RECT  2.16 257.445 246.24 257.715 ;
     RECT  2.16 257.985 246.24 258.255 ;
     RECT  2.16 258.525 246.24 258.795 ;
     RECT  2.16 259.065 246.24 259.335 ;
     RECT  2.16 259.605 246.24 259.875 ;
     RECT  2.16 260.145 246.24 260.415 ;
     RECT  2.16 260.685 246.24 260.955 ;
     RECT  2.16 261.225 246.24 261.495 ;
     RECT  2.16 261.765 246.24 262.035 ;
     RECT  2.16 262.305 246.24 262.575 ;
     RECT  2.16 262.845 246.24 263.115 ;
     RECT  2.16 263.385 246.24 263.655 ;
     RECT  2.16 263.925 246.24 264.195 ;
     RECT  2.16 264.465 246.24 264.735 ;
     RECT  2.16 265.005 246.24 265.275 ;
     RECT  2.16 265.545 246.24 265.815 ;
     RECT  2.16 266.085 246.24 266.355 ;
     RECT  2.16 266.625 246.24 266.895 ;
     RECT  2.16 267.165 246.24 267.435 ;
     RECT  2.16 267.705 246.24 267.975 ;
     RECT  2.16 268.245 246.24 268.515 ;
     RECT  2.16 268.785 246.24 269.055 ;
     RECT  2.16 269.325 246.24 269.595 ;
     RECT  2.16 269.865 246.24 270.135 ;
     RECT  2.16 270.405 246.24 270.675 ;
     RECT  2.16 270.945 246.24 271.215 ;
     RECT  2.16 271.485 246.24 271.755 ;
     RECT  2.16 272.025 246.24 272.295 ;
     RECT  2.16 272.565 246.24 272.835 ;
     RECT  2.16 273.105 246.24 273.375 ;
     RECT  2.16 273.645 246.24 273.915 ;
     RECT  2.16 274.185 246.24 274.455 ;
     RECT  2.16 274.725 246.24 274.995 ;
     RECT  2.16 275.265 246.24 275.535 ;
     RECT  2.16 275.805 246.24 276.075 ;
     RECT  2.16 276.345 246.24 276.615 ;
     RECT  2.16 276.885 246.24 277.155 ;
     RECT  2.16 277.425 246.24 277.695 ;
     RECT  2.16 277.965 246.24 278.235 ;
     RECT  2.16 278.505 246.24 278.775 ;
     RECT  2.16 279.045 246.24 279.315 ;
     RECT  2.16 279.585 246.24 279.855 ;
     RECT  2.16 280.125 246.24 280.395 ;
     RECT  2.16 280.665 246.24 280.935 ;
     RECT  2.16 281.205 246.24 281.475 ;
     RECT  2.16 281.745 246.24 282.015 ;
     RECT  2.16 282.285 246.24 282.555 ;
     RECT  2.16 282.825 246.24 283.095 ;
     RECT  2.16 283.365 246.24 283.635 ;
     RECT  2.16 283.905 246.24 284.175 ;
     RECT  2.16 284.445 246.24 284.715 ;
     RECT  2.16 284.985 246.24 285.255 ;
     RECT  2.16 285.525 246.24 285.795 ;
     RECT  2.16 286.065 246.24 286.335 ;
     RECT  2.16 286.605 246.24 286.875 ;
     RECT  2.16 287.145 246.24 287.415 ;
     RECT  2.16 287.685 246.24 287.955 ;
     RECT  2.16 288.225 246.24 288.495 ;
     RECT  2.16 288.765 246.24 289.035 ;
     RECT  2.16 289.305 246.24 289.575 ;
     RECT  2.16 289.845 246.24 290.115 ;
     RECT  2.16 290.385 246.24 290.655 ;
     RECT  2.16 290.925 246.24 291.195 ;
     RECT  2.16 291.465 246.24 291.735 ;
     RECT  2.16 292.005 246.24 292.275 ;
     RECT  2.16 292.545 246.24 292.815 ;
     RECT  2.16 293.085 246.24 293.355 ;
     RECT  2.16 293.625 246.24 293.895 ;
     RECT  2.16 294.165 246.24 294.435 ;
     RECT  2.16 294.705 246.24 294.975 ;
     RECT  2.16 295.245 246.24 295.515 ;
     RECT  2.16 295.785 246.24 296.055 ;
     RECT  2.16 296.325 246.24 296.595 ;
     RECT  2.16 296.865 246.24 297.135 ;
     RECT  2.16 297.405 246.24 297.675 ;
     RECT  2.16 297.945 246.24 298.215 ;
     RECT  2.16 298.485 246.24 298.755 ;
     RECT  2.16 299.025 246.24 299.295 ;
     RECT  2.16 299.565 246.24 299.835 ;
     RECT  2.16 300.105 246.24 300.375 ;
     RECT  2.16 300.645 246.24 300.915 ;
     RECT  2.16 301.185 246.24 301.455 ;
     RECT  2.16 301.725 246.24 301.995 ;
     RECT  2.16 302.265 246.24 302.535 ;
     RECT  2.16 302.805 246.24 303.075 ;
     RECT  2.16 303.345 246.24 303.615 ;
     RECT  2.16 303.885 246.24 304.155 ;
     RECT  2.16 304.425 246.24 304.695 ;
     RECT  2.16 304.965 246.24 305.235 ;
     RECT  2.16 305.505 246.24 305.775 ;
     RECT  2.16 306.045 246.24 306.315 ;
     RECT  2.16 306.585 246.24 306.855 ;
     RECT  2.16 307.125 246.24 307.395 ;
     RECT  2.16 307.665 246.24 307.935 ;
     RECT  2.16 308.205 246.24 308.475 ;
     RECT  2.16 308.745 246.24 309.015 ;
     RECT  2.16 309.285 246.24 309.555 ;
     RECT  2.16 309.825 246.24 310.095 ;
     RECT  2.16 310.365 246.24 310.635 ;
     RECT  2.16 310.905 246.24 311.175 ;
     RECT  2.16 311.445 246.24 311.715 ;
     RECT  2.16 311.985 246.24 312.255 ;
     RECT  2.16 312.525 246.24 312.795 ;
     RECT  2.16 313.065 246.24 313.335 ;
     RECT  2.16 313.605 246.24 313.875 ;
     RECT  2.16 314.145 246.24 314.415 ;
     RECT  2.16 314.685 246.24 314.955 ;
     RECT  2.16 315.225 246.24 315.495 ;
     RECT  2.16 315.765 246.24 316.035 ;
     RECT  2.16 316.305 246.24 316.575 ;
     RECT  2.16 316.845 246.24 317.115 ;
     RECT  2.16 317.385 246.24 317.655 ;
     RECT  2.16 317.925 246.24 318.195 ;
     RECT  2.16 318.465 246.24 318.735 ;
     RECT  2.16 319.005 246.24 319.275 ;
     RECT  2.16 319.545 246.24 319.815 ;
     RECT  2.16 320.085 246.24 320.355 ;
     RECT  2.16 320.625 246.24 320.895 ;
     RECT  2.16 321.165 246.24 321.435 ;
     RECT  2.16 321.705 246.24 321.975 ;
     RECT  2.16 322.245 246.24 322.515 ;
     RECT  2.16 322.785 246.24 323.055 ;
     RECT  2.16 323.325 246.24 323.595 ;
     RECT  2.16 323.865 246.24 324.135 ;
     RECT  2.16 324.405 246.24 324.675 ;
     RECT  2.16 324.945 246.24 325.215 ;
     RECT  2.16 325.485 246.24 325.755 ;
     RECT  2.16 326.025 246.24 326.295 ;
     RECT  2.16 326.565 246.24 326.835 ;
     RECT  2.16 327.105 246.24 327.375 ;
     RECT  2.16 327.645 246.24 327.915 ;
     RECT  2.16 328.185 246.24 328.455 ;
     RECT  2.16 328.725 246.24 328.995 ;
     RECT  2.16 329.265 246.24 329.535 ;
     RECT  2.16 329.805 246.24 330.075 ;
     RECT  2.16 330.345 246.24 330.615 ;
     RECT  2.16 330.885 246.24 331.155 ;
     RECT  2.16 331.425 246.24 331.695 ;
     RECT  2.16 331.965 246.24 332.235 ;
     RECT  2.16 332.505 246.24 332.775 ;
     RECT  2.16 333.045 246.24 333.315 ;
     RECT  2.16 333.585 246.24 333.855 ;
     RECT  2.16 334.125 246.24 334.395 ;
     RECT  2.16 334.665 246.24 334.935 ;
     RECT  2.16 335.205 246.24 335.475 ;
     RECT  2.16 335.745 246.24 336.015 ;
     RECT  2.16 336.285 246.24 336.555 ;
     RECT  2.16 336.825 246.24 337.095 ;
     RECT  2.16 337.365 246.24 337.635 ;
     RECT  2.16 337.905 246.24 338.175 ;
     RECT  2.16 338.445 246.24 338.715 ;
     RECT  2.16 338.985 246.24 339.255 ;
     RECT  2.16 339.525 246.24 339.795 ;
     RECT  2.16 340.065 246.24 340.335 ;
     RECT  2.16 340.605 246.24 340.875 ;
     RECT  2.16 341.145 246.24 341.415 ;
     RECT  2.16 341.685 246.24 341.955 ;
     RECT  2.16 342.225 246.24 342.495 ;
     RECT  2.16 342.765 246.24 343.035 ;
     RECT  2.16 343.305 246.24 343.575 ;
     RECT  2.16 343.845 246.24 344.115 ;
     RECT  2.16 344.385 246.24 344.655 ;
     RECT  2.16 344.925 246.24 345.195 ;
     RECT  2.16 345.465 246.24 345.735 ;
     RECT  2.16 346.005 246.24 346.275 ;
     RECT  2.16 346.545 246.24 346.815 ;
     RECT  2.16 347.085 246.24 347.355 ;
     RECT  2.16 347.625 246.24 347.895 ;
     RECT  2.16 348.165 246.24 348.435 ;
     RECT  2.16 348.705 246.24 348.975 ;
     RECT  2.16 349.245 246.24 349.515 ;
     RECT  2.16 349.785 246.24 350.055 ;
     RECT  2.16 350.325 246.24 350.595 ;
     RECT  2.16 350.865 246.24 351.135 ;
     RECT  2.16 351.405 246.24 351.675 ;
     RECT  2.16 351.945 246.24 352.215 ;
     RECT  2.16 352.485 246.24 352.755 ;
     RECT  2.16 353.025 246.24 353.295 ;
     RECT  2.16 353.565 246.24 353.835 ;
     RECT  2.16 354.105 246.24 354.375 ;
     RECT  2.16 354.645 246.24 354.915 ;
     RECT  2.16 355.185 246.24 355.455 ;
     RECT  2.16 355.725 246.24 355.995 ;
     RECT  2.16 356.265 246.24 356.535 ;
     RECT  2.16 356.805 246.24 357.075 ;
     RECT  2.16 357.345 246.24 357.615 ;
     RECT  2.16 357.885 246.24 358.155 ;
     RECT  2.16 358.425 246.24 358.695 ;
     RECT  2.16 358.965 246.24 359.235 ;
     RECT  2.16 359.505 246.24 359.775 ;
     RECT  2.16 360.045 246.24 360.315 ;
     RECT  2.16 360.585 246.24 360.855 ;
     RECT  2.16 361.125 246.24 361.395 ;
     RECT  2.16 361.665 246.24 361.935 ;
     RECT  2.16 362.205 246.24 362.475 ;
     RECT  2.16 362.745 246.24 363.015 ;
     RECT  2.16 363.285 246.24 363.555 ;
     RECT  2.16 363.825 246.24 364.095 ;
     RECT  2.16 364.365 246.24 364.635 ;
     RECT  2.16 364.905 246.24 365.175 ;
     RECT  2.16 365.445 246.24 365.715 ;
     RECT  2.16 365.985 246.24 366.255 ;
     RECT  2.16 366.525 246.24 366.795 ;
     RECT  2.16 367.065 246.24 367.335 ;
     RECT  2.16 367.605 246.24 367.875 ;
     RECT  2.16 368.145 246.24 368.415 ;
     RECT  2.16 368.685 246.24 368.955 ;
     RECT  2.16 369.225 246.24 369.36 ;
    LAYER RVTP ;
     RECT  2.16 2.295 246.24 2.565 ;
     RECT  2.16 2.835 246.24 3.105 ;
     RECT  2.16 3.375 246.24 3.645 ;
     RECT  2.16 3.915 246.24 4.185 ;
     RECT  2.16 4.455 246.24 4.725 ;
     RECT  2.16 4.995 246.24 5.265 ;
     RECT  2.16 5.535 246.24 5.805 ;
     RECT  2.16 6.075 246.24 6.345 ;
     RECT  2.16 6.615 246.24 6.885 ;
     RECT  2.16 7.155 246.24 7.425 ;
     RECT  2.16 7.695 246.24 7.965 ;
     RECT  2.16 8.235 246.24 8.505 ;
     RECT  2.16 8.775 246.24 9.045 ;
     RECT  2.16 9.315 246.24 9.585 ;
     RECT  2.16 9.855 246.24 10.125 ;
     RECT  2.16 10.395 246.24 10.665 ;
     RECT  2.16 10.935 246.24 11.205 ;
     RECT  2.16 11.475 246.24 11.745 ;
     RECT  2.16 12.015 246.24 12.285 ;
     RECT  2.16 12.555 246.24 12.825 ;
     RECT  2.16 13.095 246.24 13.365 ;
     RECT  2.16 13.635 246.24 13.905 ;
     RECT  2.16 14.175 246.24 14.445 ;
     RECT  2.16 14.715 246.24 14.985 ;
     RECT  2.16 15.255 246.24 15.525 ;
     RECT  2.16 15.795 246.24 16.065 ;
     RECT  2.16 16.335 246.24 16.605 ;
     RECT  2.16 16.875 246.24 17.145 ;
     RECT  2.16 17.415 246.24 17.685 ;
     RECT  2.16 17.955 246.24 18.225 ;
     RECT  2.16 18.495 246.24 18.765 ;
     RECT  2.16 19.035 246.24 19.305 ;
     RECT  2.16 19.575 246.24 19.845 ;
     RECT  2.16 20.115 246.24 20.385 ;
     RECT  2.16 20.655 246.24 20.925 ;
     RECT  2.16 21.195 246.24 21.465 ;
     RECT  2.16 21.735 246.24 22.005 ;
     RECT  2.16 22.275 246.24 22.545 ;
     RECT  2.16 22.815 246.24 23.085 ;
     RECT  2.16 23.355 246.24 23.625 ;
     RECT  2.16 23.895 246.24 24.165 ;
     RECT  2.16 24.435 246.24 24.705 ;
     RECT  2.16 24.975 246.24 25.245 ;
     RECT  2.16 25.515 246.24 25.785 ;
     RECT  2.16 26.055 246.24 26.325 ;
     RECT  2.16 26.595 246.24 26.865 ;
     RECT  2.16 27.135 246.24 27.405 ;
     RECT  2.16 27.675 246.24 27.945 ;
     RECT  2.16 28.215 246.24 28.485 ;
     RECT  2.16 28.755 246.24 29.025 ;
     RECT  2.16 29.295 246.24 29.565 ;
     RECT  2.16 29.835 246.24 30.105 ;
     RECT  2.16 30.375 246.24 30.645 ;
     RECT  2.16 30.915 246.24 31.185 ;
     RECT  2.16 31.455 246.24 31.725 ;
     RECT  2.16 31.995 246.24 32.265 ;
     RECT  2.16 32.535 246.24 32.805 ;
     RECT  2.16 33.075 246.24 33.345 ;
     RECT  2.16 33.615 246.24 33.885 ;
     RECT  2.16 34.155 246.24 34.425 ;
     RECT  2.16 34.695 246.24 34.965 ;
     RECT  2.16 35.235 246.24 35.505 ;
     RECT  2.16 35.775 246.24 36.045 ;
     RECT  2.16 36.315 246.24 36.585 ;
     RECT  2.16 36.855 246.24 37.125 ;
     RECT  2.16 37.395 246.24 37.665 ;
     RECT  2.16 37.935 246.24 38.205 ;
     RECT  2.16 38.475 246.24 38.745 ;
     RECT  2.16 39.015 246.24 39.285 ;
     RECT  2.16 39.555 246.24 39.825 ;
     RECT  2.16 40.095 246.24 40.365 ;
     RECT  2.16 40.635 246.24 40.905 ;
     RECT  2.16 41.175 246.24 41.445 ;
     RECT  2.16 41.715 246.24 41.985 ;
     RECT  2.16 42.255 246.24 42.525 ;
     RECT  2.16 42.795 246.24 43.065 ;
     RECT  2.16 43.335 246.24 43.605 ;
     RECT  2.16 43.875 246.24 44.145 ;
     RECT  2.16 44.415 246.24 44.685 ;
     RECT  2.16 44.955 246.24 45.225 ;
     RECT  2.16 45.495 246.24 45.765 ;
     RECT  2.16 46.035 246.24 46.305 ;
     RECT  2.16 46.575 246.24 46.845 ;
     RECT  2.16 47.115 246.24 47.385 ;
     RECT  2.16 47.655 246.24 47.925 ;
     RECT  2.16 48.195 246.24 48.465 ;
     RECT  2.16 48.735 246.24 49.005 ;
     RECT  2.16 49.275 246.24 49.545 ;
     RECT  2.16 49.815 246.24 50.085 ;
     RECT  2.16 50.355 246.24 50.625 ;
     RECT  2.16 50.895 246.24 51.165 ;
     RECT  2.16 51.435 246.24 51.705 ;
     RECT  2.16 51.975 246.24 52.245 ;
     RECT  2.16 52.515 246.24 52.785 ;
     RECT  2.16 53.055 246.24 53.325 ;
     RECT  2.16 53.595 246.24 53.865 ;
     RECT  2.16 54.135 246.24 54.405 ;
     RECT  2.16 54.675 246.24 54.945 ;
     RECT  2.16 55.215 246.24 55.485 ;
     RECT  2.16 55.755 246.24 56.025 ;
     RECT  2.16 56.295 246.24 56.565 ;
     RECT  2.16 56.835 246.24 57.105 ;
     RECT  2.16 57.375 246.24 57.645 ;
     RECT  2.16 57.915 246.24 58.185 ;
     RECT  2.16 58.455 246.24 58.725 ;
     RECT  2.16 58.995 246.24 59.265 ;
     RECT  2.16 59.535 246.24 59.805 ;
     RECT  2.16 60.075 246.24 60.345 ;
     RECT  2.16 60.615 246.24 60.885 ;
     RECT  2.16 61.155 246.24 61.425 ;
     RECT  2.16 61.695 246.24 61.965 ;
     RECT  2.16 62.235 246.24 62.505 ;
     RECT  2.16 62.775 246.24 63.045 ;
     RECT  2.16 63.315 246.24 63.585 ;
     RECT  2.16 63.855 246.24 64.125 ;
     RECT  2.16 64.395 246.24 64.665 ;
     RECT  2.16 64.935 246.24 65.205 ;
     RECT  2.16 65.475 246.24 65.745 ;
     RECT  2.16 66.015 246.24 66.285 ;
     RECT  2.16 66.555 246.24 66.825 ;
     RECT  2.16 67.095 246.24 67.365 ;
     RECT  2.16 67.635 246.24 67.905 ;
     RECT  2.16 68.175 246.24 68.445 ;
     RECT  2.16 68.715 246.24 68.985 ;
     RECT  2.16 69.255 246.24 69.525 ;
     RECT  2.16 69.795 246.24 70.065 ;
     RECT  2.16 70.335 246.24 70.605 ;
     RECT  2.16 70.875 246.24 71.145 ;
     RECT  2.16 71.415 246.24 71.685 ;
     RECT  2.16 71.955 246.24 72.225 ;
     RECT  2.16 72.495 246.24 72.765 ;
     RECT  2.16 73.035 246.24 73.305 ;
     RECT  2.16 73.575 246.24 73.845 ;
     RECT  2.16 74.115 246.24 74.385 ;
     RECT  2.16 74.655 246.24 74.925 ;
     RECT  2.16 75.195 246.24 75.465 ;
     RECT  2.16 75.735 246.24 76.005 ;
     RECT  2.16 76.275 246.24 76.545 ;
     RECT  2.16 76.815 246.24 77.085 ;
     RECT  2.16 77.355 246.24 77.625 ;
     RECT  2.16 77.895 246.24 78.165 ;
     RECT  2.16 78.435 246.24 78.705 ;
     RECT  2.16 78.975 246.24 79.245 ;
     RECT  2.16 79.515 246.24 79.785 ;
     RECT  2.16 80.055 246.24 80.325 ;
     RECT  2.16 80.595 246.24 80.865 ;
     RECT  2.16 81.135 246.24 81.405 ;
     RECT  2.16 81.675 246.24 81.945 ;
     RECT  2.16 82.215 246.24 82.485 ;
     RECT  2.16 82.755 246.24 83.025 ;
     RECT  2.16 83.295 246.24 83.565 ;
     RECT  2.16 83.835 246.24 84.105 ;
     RECT  2.16 84.375 246.24 84.645 ;
     RECT  2.16 84.915 246.24 85.185 ;
     RECT  2.16 85.455 246.24 85.725 ;
     RECT  2.16 85.995 246.24 86.265 ;
     RECT  2.16 86.535 246.24 86.805 ;
     RECT  2.16 87.075 246.24 87.345 ;
     RECT  2.16 87.615 246.24 87.885 ;
     RECT  2.16 88.155 246.24 88.425 ;
     RECT  2.16 88.695 246.24 88.965 ;
     RECT  2.16 89.235 246.24 89.505 ;
     RECT  2.16 89.775 246.24 90.045 ;
     RECT  2.16 90.315 246.24 90.585 ;
     RECT  2.16 90.855 246.24 91.125 ;
     RECT  2.16 91.395 246.24 91.665 ;
     RECT  2.16 91.935 246.24 92.205 ;
     RECT  2.16 92.475 246.24 92.745 ;
     RECT  2.16 93.015 246.24 93.285 ;
     RECT  2.16 93.555 246.24 93.825 ;
     RECT  2.16 94.095 246.24 94.365 ;
     RECT  2.16 94.635 246.24 94.905 ;
     RECT  2.16 95.175 246.24 95.445 ;
     RECT  2.16 95.715 246.24 95.985 ;
     RECT  2.16 96.255 246.24 96.525 ;
     RECT  2.16 96.795 246.24 97.065 ;
     RECT  2.16 97.335 246.24 97.605 ;
     RECT  2.16 97.875 246.24 98.145 ;
     RECT  2.16 98.415 246.24 98.685 ;
     RECT  2.16 98.955 246.24 99.225 ;
     RECT  2.16 99.495 246.24 99.765 ;
     RECT  2.16 100.035 246.24 100.305 ;
     RECT  2.16 100.575 246.24 100.845 ;
     RECT  2.16 101.115 246.24 101.385 ;
     RECT  2.16 101.655 246.24 101.925 ;
     RECT  2.16 102.195 246.24 102.465 ;
     RECT  2.16 102.735 246.24 103.005 ;
     RECT  2.16 103.275 246.24 103.545 ;
     RECT  2.16 103.815 246.24 104.085 ;
     RECT  2.16 104.355 246.24 104.625 ;
     RECT  2.16 104.895 246.24 105.165 ;
     RECT  2.16 105.435 246.24 105.705 ;
     RECT  2.16 105.975 246.24 106.245 ;
     RECT  2.16 106.515 246.24 106.785 ;
     RECT  2.16 107.055 246.24 107.325 ;
     RECT  2.16 107.595 246.24 107.865 ;
     RECT  2.16 108.135 246.24 108.405 ;
     RECT  2.16 108.675 246.24 108.945 ;
     RECT  2.16 109.215 246.24 109.485 ;
     RECT  2.16 109.755 246.24 110.025 ;
     RECT  2.16 110.295 246.24 110.565 ;
     RECT  2.16 110.835 246.24 111.105 ;
     RECT  2.16 111.375 246.24 111.645 ;
     RECT  2.16 111.915 246.24 112.185 ;
     RECT  2.16 112.455 246.24 112.725 ;
     RECT  2.16 112.995 246.24 113.265 ;
     RECT  2.16 113.535 246.24 113.805 ;
     RECT  2.16 114.075 246.24 114.345 ;
     RECT  2.16 114.615 246.24 114.885 ;
     RECT  2.16 115.155 246.24 115.425 ;
     RECT  2.16 115.695 246.24 115.965 ;
     RECT  2.16 116.235 246.24 116.505 ;
     RECT  2.16 116.775 246.24 117.045 ;
     RECT  2.16 117.315 246.24 117.585 ;
     RECT  2.16 117.855 246.24 118.125 ;
     RECT  2.16 118.395 246.24 118.665 ;
     RECT  2.16 118.935 246.24 119.205 ;
     RECT  2.16 119.475 246.24 119.745 ;
     RECT  2.16 120.015 246.24 120.285 ;
     RECT  2.16 120.555 246.24 120.825 ;
     RECT  2.16 121.095 246.24 121.365 ;
     RECT  2.16 121.635 246.24 121.905 ;
     RECT  2.16 122.175 246.24 122.445 ;
     RECT  2.16 122.715 246.24 122.985 ;
     RECT  2.16 123.255 246.24 123.525 ;
     RECT  2.16 123.795 246.24 124.065 ;
     RECT  2.16 124.335 246.24 124.605 ;
     RECT  2.16 124.875 246.24 125.145 ;
     RECT  2.16 125.415 246.24 125.685 ;
     RECT  2.16 125.955 246.24 126.225 ;
     RECT  2.16 126.495 246.24 126.765 ;
     RECT  2.16 127.035 246.24 127.305 ;
     RECT  2.16 127.575 246.24 127.845 ;
     RECT  2.16 128.115 246.24 128.385 ;
     RECT  2.16 128.655 246.24 128.925 ;
     RECT  2.16 129.195 246.24 129.465 ;
     RECT  2.16 129.735 246.24 130.005 ;
     RECT  2.16 130.275 246.24 130.545 ;
     RECT  2.16 130.815 246.24 131.085 ;
     RECT  2.16 131.355 246.24 131.625 ;
     RECT  2.16 131.895 246.24 132.165 ;
     RECT  2.16 132.435 246.24 132.705 ;
     RECT  2.16 132.975 246.24 133.245 ;
     RECT  2.16 133.515 246.24 133.785 ;
     RECT  2.16 134.055 246.24 134.325 ;
     RECT  2.16 134.595 246.24 134.865 ;
     RECT  2.16 135.135 246.24 135.405 ;
     RECT  2.16 135.675 246.24 135.945 ;
     RECT  2.16 136.215 246.24 136.485 ;
     RECT  2.16 136.755 246.24 137.025 ;
     RECT  2.16 137.295 246.24 137.565 ;
     RECT  2.16 137.835 246.24 138.105 ;
     RECT  2.16 138.375 246.24 138.645 ;
     RECT  2.16 138.915 246.24 139.185 ;
     RECT  2.16 139.455 246.24 139.725 ;
     RECT  2.16 139.995 246.24 140.265 ;
     RECT  2.16 140.535 246.24 140.805 ;
     RECT  2.16 141.075 246.24 141.345 ;
     RECT  2.16 141.615 246.24 141.885 ;
     RECT  2.16 142.155 246.24 142.425 ;
     RECT  2.16 142.695 246.24 142.965 ;
     RECT  2.16 143.235 246.24 143.505 ;
     RECT  2.16 143.775 246.24 144.045 ;
     RECT  2.16 144.315 246.24 144.585 ;
     RECT  2.16 144.855 246.24 145.125 ;
     RECT  2.16 145.395 246.24 145.665 ;
     RECT  2.16 145.935 246.24 146.205 ;
     RECT  2.16 146.475 246.24 146.745 ;
     RECT  2.16 147.015 246.24 147.285 ;
     RECT  2.16 147.555 246.24 147.825 ;
     RECT  2.16 148.095 246.24 148.365 ;
     RECT  2.16 148.635 246.24 148.905 ;
     RECT  2.16 149.175 246.24 149.445 ;
     RECT  2.16 149.715 246.24 149.985 ;
     RECT  2.16 150.255 246.24 150.525 ;
     RECT  2.16 150.795 246.24 151.065 ;
     RECT  2.16 151.335 246.24 151.605 ;
     RECT  2.16 151.875 246.24 152.145 ;
     RECT  2.16 152.415 246.24 152.685 ;
     RECT  2.16 152.955 246.24 153.225 ;
     RECT  2.16 153.495 246.24 153.765 ;
     RECT  2.16 154.035 246.24 154.305 ;
     RECT  2.16 154.575 246.24 154.845 ;
     RECT  2.16 155.115 246.24 155.385 ;
     RECT  2.16 155.655 246.24 155.925 ;
     RECT  2.16 156.195 246.24 156.465 ;
     RECT  2.16 156.735 246.24 157.005 ;
     RECT  2.16 157.275 246.24 157.545 ;
     RECT  2.16 157.815 246.24 158.085 ;
     RECT  2.16 158.355 246.24 158.625 ;
     RECT  2.16 158.895 246.24 159.165 ;
     RECT  2.16 159.435 246.24 159.705 ;
     RECT  2.16 159.975 246.24 160.245 ;
     RECT  2.16 160.515 246.24 160.785 ;
     RECT  2.16 161.055 246.24 161.325 ;
     RECT  2.16 161.595 246.24 161.865 ;
     RECT  2.16 162.135 246.24 162.405 ;
     RECT  2.16 162.675 246.24 162.945 ;
     RECT  2.16 163.215 246.24 163.485 ;
     RECT  2.16 163.755 246.24 164.025 ;
     RECT  2.16 164.295 246.24 164.565 ;
     RECT  2.16 164.835 246.24 165.105 ;
     RECT  2.16 165.375 246.24 165.645 ;
     RECT  2.16 165.915 246.24 166.185 ;
     RECT  2.16 166.455 246.24 166.725 ;
     RECT  2.16 166.995 246.24 167.265 ;
     RECT  2.16 167.535 246.24 167.805 ;
     RECT  2.16 168.075 246.24 168.345 ;
     RECT  2.16 168.615 246.24 168.885 ;
     RECT  2.16 169.155 246.24 169.425 ;
     RECT  2.16 169.695 246.24 169.965 ;
     RECT  2.16 170.235 246.24 170.505 ;
     RECT  2.16 170.775 246.24 171.045 ;
     RECT  2.16 171.315 246.24 171.585 ;
     RECT  2.16 171.855 246.24 172.125 ;
     RECT  2.16 172.395 246.24 172.665 ;
     RECT  2.16 172.935 246.24 173.205 ;
     RECT  2.16 173.475 246.24 173.745 ;
     RECT  2.16 174.015 246.24 174.285 ;
     RECT  2.16 174.555 246.24 174.825 ;
     RECT  2.16 175.095 246.24 175.365 ;
     RECT  2.16 175.635 246.24 175.905 ;
     RECT  2.16 176.175 246.24 176.445 ;
     RECT  2.16 176.715 246.24 176.985 ;
     RECT  2.16 177.255 246.24 177.525 ;
     RECT  2.16 177.795 246.24 178.065 ;
     RECT  2.16 178.335 246.24 178.605 ;
     RECT  2.16 178.875 246.24 179.145 ;
     RECT  2.16 179.415 246.24 179.685 ;
     RECT  2.16 179.955 246.24 180.225 ;
     RECT  2.16 180.495 246.24 180.765 ;
     RECT  2.16 181.035 246.24 181.305 ;
     RECT  2.16 181.575 246.24 181.845 ;
     RECT  2.16 182.115 246.24 182.385 ;
     RECT  2.16 182.655 246.24 182.925 ;
     RECT  2.16 183.195 246.24 183.465 ;
     RECT  2.16 183.735 246.24 184.005 ;
     RECT  2.16 184.275 246.24 184.545 ;
     RECT  2.16 184.815 246.24 185.085 ;
     RECT  2.16 185.355 246.24 185.625 ;
     RECT  2.16 185.895 246.24 186.165 ;
     RECT  2.16 186.435 246.24 186.705 ;
     RECT  2.16 186.975 246.24 187.245 ;
     RECT  2.16 187.515 246.24 187.785 ;
     RECT  2.16 188.055 246.24 188.325 ;
     RECT  2.16 188.595 246.24 188.865 ;
     RECT  2.16 189.135 246.24 189.405 ;
     RECT  2.16 189.675 246.24 189.945 ;
     RECT  2.16 190.215 246.24 190.485 ;
     RECT  2.16 190.755 246.24 191.025 ;
     RECT  2.16 191.295 246.24 191.565 ;
     RECT  2.16 191.835 246.24 192.105 ;
     RECT  2.16 192.375 246.24 192.645 ;
     RECT  2.16 192.915 246.24 193.185 ;
     RECT  2.16 193.455 246.24 193.725 ;
     RECT  2.16 193.995 246.24 194.265 ;
     RECT  2.16 194.535 246.24 194.805 ;
     RECT  2.16 195.075 246.24 195.345 ;
     RECT  2.16 195.615 246.24 195.885 ;
     RECT  2.16 196.155 246.24 196.425 ;
     RECT  2.16 196.695 246.24 196.965 ;
     RECT  2.16 197.235 246.24 197.505 ;
     RECT  2.16 197.775 246.24 198.045 ;
     RECT  2.16 198.315 246.24 198.585 ;
     RECT  2.16 198.855 246.24 199.125 ;
     RECT  2.16 199.395 246.24 199.665 ;
     RECT  2.16 199.935 246.24 200.205 ;
     RECT  2.16 200.475 246.24 200.745 ;
     RECT  2.16 201.015 246.24 201.285 ;
     RECT  2.16 201.555 246.24 201.825 ;
     RECT  2.16 202.095 246.24 202.365 ;
     RECT  2.16 202.635 246.24 202.905 ;
     RECT  2.16 203.175 246.24 203.445 ;
     RECT  2.16 203.715 246.24 203.985 ;
     RECT  2.16 204.255 246.24 204.525 ;
     RECT  2.16 204.795 246.24 205.065 ;
     RECT  2.16 205.335 246.24 205.605 ;
     RECT  2.16 205.875 246.24 206.145 ;
     RECT  2.16 206.415 246.24 206.685 ;
     RECT  2.16 206.955 246.24 207.225 ;
     RECT  2.16 207.495 246.24 207.765 ;
     RECT  2.16 208.035 246.24 208.305 ;
     RECT  2.16 208.575 246.24 208.845 ;
     RECT  2.16 209.115 246.24 209.385 ;
     RECT  2.16 209.655 246.24 209.925 ;
     RECT  2.16 210.195 246.24 210.465 ;
     RECT  2.16 210.735 246.24 211.005 ;
     RECT  2.16 211.275 246.24 211.545 ;
     RECT  2.16 211.815 246.24 212.085 ;
     RECT  2.16 212.355 246.24 212.625 ;
     RECT  2.16 212.895 246.24 213.165 ;
     RECT  2.16 213.435 246.24 213.705 ;
     RECT  2.16 213.975 246.24 214.245 ;
     RECT  2.16 214.515 246.24 214.785 ;
     RECT  2.16 215.055 246.24 215.325 ;
     RECT  2.16 215.595 246.24 215.865 ;
     RECT  2.16 216.135 246.24 216.405 ;
     RECT  2.16 216.675 246.24 216.945 ;
     RECT  2.16 217.215 246.24 217.485 ;
     RECT  2.16 217.755 246.24 218.025 ;
     RECT  2.16 218.295 246.24 218.565 ;
     RECT  2.16 218.835 246.24 219.105 ;
     RECT  2.16 219.375 246.24 219.645 ;
     RECT  2.16 219.915 246.24 220.185 ;
     RECT  2.16 220.455 246.24 220.725 ;
     RECT  2.16 220.995 246.24 221.265 ;
     RECT  2.16 221.535 246.24 221.805 ;
     RECT  2.16 222.075 246.24 222.345 ;
     RECT  2.16 222.615 246.24 222.885 ;
     RECT  2.16 223.155 246.24 223.425 ;
     RECT  2.16 223.695 246.24 223.965 ;
     RECT  2.16 224.235 246.24 224.505 ;
     RECT  2.16 224.775 246.24 225.045 ;
     RECT  2.16 225.315 246.24 225.585 ;
     RECT  2.16 225.855 246.24 226.125 ;
     RECT  2.16 226.395 246.24 226.665 ;
     RECT  2.16 226.935 246.24 227.205 ;
     RECT  2.16 227.475 246.24 227.745 ;
     RECT  2.16 228.015 246.24 228.285 ;
     RECT  2.16 228.555 246.24 228.825 ;
     RECT  2.16 229.095 246.24 229.365 ;
     RECT  2.16 229.635 246.24 229.905 ;
     RECT  2.16 230.175 246.24 230.445 ;
     RECT  2.16 230.715 246.24 230.985 ;
     RECT  2.16 231.255 246.24 231.525 ;
     RECT  2.16 231.795 246.24 232.065 ;
     RECT  2.16 232.335 246.24 232.605 ;
     RECT  2.16 232.875 246.24 233.145 ;
     RECT  2.16 233.415 246.24 233.685 ;
     RECT  2.16 233.955 246.24 234.225 ;
     RECT  2.16 234.495 246.24 234.765 ;
     RECT  2.16 235.035 246.24 235.305 ;
     RECT  2.16 235.575 246.24 235.845 ;
     RECT  2.16 236.115 246.24 236.385 ;
     RECT  2.16 236.655 246.24 236.925 ;
     RECT  2.16 237.195 246.24 237.465 ;
     RECT  2.16 237.735 246.24 238.005 ;
     RECT  2.16 238.275 246.24 238.545 ;
     RECT  2.16 238.815 246.24 239.085 ;
     RECT  2.16 239.355 246.24 239.625 ;
     RECT  2.16 239.895 246.24 240.165 ;
     RECT  2.16 240.435 246.24 240.705 ;
     RECT  2.16 240.975 246.24 241.245 ;
     RECT  2.16 241.515 246.24 241.785 ;
     RECT  2.16 242.055 246.24 242.325 ;
     RECT  2.16 242.595 246.24 242.865 ;
     RECT  2.16 243.135 246.24 243.405 ;
     RECT  2.16 243.675 246.24 243.945 ;
     RECT  2.16 244.215 246.24 244.485 ;
     RECT  2.16 244.755 246.24 245.025 ;
     RECT  2.16 245.295 246.24 245.565 ;
     RECT  2.16 245.835 246.24 246.105 ;
     RECT  2.16 246.375 246.24 246.645 ;
     RECT  2.16 246.915 246.24 247.185 ;
     RECT  2.16 247.455 246.24 247.725 ;
     RECT  2.16 247.995 246.24 248.265 ;
     RECT  2.16 248.535 246.24 248.805 ;
     RECT  2.16 249.075 246.24 249.345 ;
     RECT  2.16 249.615 246.24 249.885 ;
     RECT  2.16 250.155 246.24 250.425 ;
     RECT  2.16 250.695 246.24 250.965 ;
     RECT  2.16 251.235 246.24 251.505 ;
     RECT  2.16 251.775 246.24 252.045 ;
     RECT  2.16 252.315 246.24 252.585 ;
     RECT  2.16 252.855 246.24 253.125 ;
     RECT  2.16 253.395 246.24 253.665 ;
     RECT  2.16 253.935 246.24 254.205 ;
     RECT  2.16 254.475 246.24 254.745 ;
     RECT  2.16 255.015 246.24 255.285 ;
     RECT  2.16 255.555 246.24 255.825 ;
     RECT  2.16 256.095 246.24 256.365 ;
     RECT  2.16 256.635 246.24 256.905 ;
     RECT  2.16 257.175 246.24 257.445 ;
     RECT  2.16 257.715 246.24 257.985 ;
     RECT  2.16 258.255 246.24 258.525 ;
     RECT  2.16 258.795 246.24 259.065 ;
     RECT  2.16 259.335 246.24 259.605 ;
     RECT  2.16 259.875 246.24 260.145 ;
     RECT  2.16 260.415 246.24 260.685 ;
     RECT  2.16 260.955 246.24 261.225 ;
     RECT  2.16 261.495 246.24 261.765 ;
     RECT  2.16 262.035 246.24 262.305 ;
     RECT  2.16 262.575 246.24 262.845 ;
     RECT  2.16 263.115 246.24 263.385 ;
     RECT  2.16 263.655 246.24 263.925 ;
     RECT  2.16 264.195 246.24 264.465 ;
     RECT  2.16 264.735 246.24 265.005 ;
     RECT  2.16 265.275 246.24 265.545 ;
     RECT  2.16 265.815 246.24 266.085 ;
     RECT  2.16 266.355 246.24 266.625 ;
     RECT  2.16 266.895 246.24 267.165 ;
     RECT  2.16 267.435 246.24 267.705 ;
     RECT  2.16 267.975 246.24 268.245 ;
     RECT  2.16 268.515 246.24 268.785 ;
     RECT  2.16 269.055 246.24 269.325 ;
     RECT  2.16 269.595 246.24 269.865 ;
     RECT  2.16 270.135 246.24 270.405 ;
     RECT  2.16 270.675 246.24 270.945 ;
     RECT  2.16 271.215 246.24 271.485 ;
     RECT  2.16 271.755 246.24 272.025 ;
     RECT  2.16 272.295 246.24 272.565 ;
     RECT  2.16 272.835 246.24 273.105 ;
     RECT  2.16 273.375 246.24 273.645 ;
     RECT  2.16 273.915 246.24 274.185 ;
     RECT  2.16 274.455 246.24 274.725 ;
     RECT  2.16 274.995 246.24 275.265 ;
     RECT  2.16 275.535 246.24 275.805 ;
     RECT  2.16 276.075 246.24 276.345 ;
     RECT  2.16 276.615 246.24 276.885 ;
     RECT  2.16 277.155 246.24 277.425 ;
     RECT  2.16 277.695 246.24 277.965 ;
     RECT  2.16 278.235 246.24 278.505 ;
     RECT  2.16 278.775 246.24 279.045 ;
     RECT  2.16 279.315 246.24 279.585 ;
     RECT  2.16 279.855 246.24 280.125 ;
     RECT  2.16 280.395 246.24 280.665 ;
     RECT  2.16 280.935 246.24 281.205 ;
     RECT  2.16 281.475 246.24 281.745 ;
     RECT  2.16 282.015 246.24 282.285 ;
     RECT  2.16 282.555 246.24 282.825 ;
     RECT  2.16 283.095 246.24 283.365 ;
     RECT  2.16 283.635 246.24 283.905 ;
     RECT  2.16 284.175 246.24 284.445 ;
     RECT  2.16 284.715 246.24 284.985 ;
     RECT  2.16 285.255 246.24 285.525 ;
     RECT  2.16 285.795 246.24 286.065 ;
     RECT  2.16 286.335 246.24 286.605 ;
     RECT  2.16 286.875 246.24 287.145 ;
     RECT  2.16 287.415 246.24 287.685 ;
     RECT  2.16 287.955 246.24 288.225 ;
     RECT  2.16 288.495 246.24 288.765 ;
     RECT  2.16 289.035 246.24 289.305 ;
     RECT  2.16 289.575 246.24 289.845 ;
     RECT  2.16 290.115 246.24 290.385 ;
     RECT  2.16 290.655 246.24 290.925 ;
     RECT  2.16 291.195 246.24 291.465 ;
     RECT  2.16 291.735 246.24 292.005 ;
     RECT  2.16 292.275 246.24 292.545 ;
     RECT  2.16 292.815 246.24 293.085 ;
     RECT  2.16 293.355 246.24 293.625 ;
     RECT  2.16 293.895 246.24 294.165 ;
     RECT  2.16 294.435 246.24 294.705 ;
     RECT  2.16 294.975 246.24 295.245 ;
     RECT  2.16 295.515 246.24 295.785 ;
     RECT  2.16 296.055 246.24 296.325 ;
     RECT  2.16 296.595 246.24 296.865 ;
     RECT  2.16 297.135 246.24 297.405 ;
     RECT  2.16 297.675 246.24 297.945 ;
     RECT  2.16 298.215 246.24 298.485 ;
     RECT  2.16 298.755 246.24 299.025 ;
     RECT  2.16 299.295 246.24 299.565 ;
     RECT  2.16 299.835 246.24 300.105 ;
     RECT  2.16 300.375 246.24 300.645 ;
     RECT  2.16 300.915 246.24 301.185 ;
     RECT  2.16 301.455 246.24 301.725 ;
     RECT  2.16 301.995 246.24 302.265 ;
     RECT  2.16 302.535 246.24 302.805 ;
     RECT  2.16 303.075 246.24 303.345 ;
     RECT  2.16 303.615 246.24 303.885 ;
     RECT  2.16 304.155 246.24 304.425 ;
     RECT  2.16 304.695 246.24 304.965 ;
     RECT  2.16 305.235 246.24 305.505 ;
     RECT  2.16 305.775 246.24 306.045 ;
     RECT  2.16 306.315 246.24 306.585 ;
     RECT  2.16 306.855 246.24 307.125 ;
     RECT  2.16 307.395 246.24 307.665 ;
     RECT  2.16 307.935 246.24 308.205 ;
     RECT  2.16 308.475 246.24 308.745 ;
     RECT  2.16 309.015 246.24 309.285 ;
     RECT  2.16 309.555 246.24 309.825 ;
     RECT  2.16 310.095 246.24 310.365 ;
     RECT  2.16 310.635 246.24 310.905 ;
     RECT  2.16 311.175 246.24 311.445 ;
     RECT  2.16 311.715 246.24 311.985 ;
     RECT  2.16 312.255 246.24 312.525 ;
     RECT  2.16 312.795 246.24 313.065 ;
     RECT  2.16 313.335 246.24 313.605 ;
     RECT  2.16 313.875 246.24 314.145 ;
     RECT  2.16 314.415 246.24 314.685 ;
     RECT  2.16 314.955 246.24 315.225 ;
     RECT  2.16 315.495 246.24 315.765 ;
     RECT  2.16 316.035 246.24 316.305 ;
     RECT  2.16 316.575 246.24 316.845 ;
     RECT  2.16 317.115 246.24 317.385 ;
     RECT  2.16 317.655 246.24 317.925 ;
     RECT  2.16 318.195 246.24 318.465 ;
     RECT  2.16 318.735 246.24 319.005 ;
     RECT  2.16 319.275 246.24 319.545 ;
     RECT  2.16 319.815 246.24 320.085 ;
     RECT  2.16 320.355 246.24 320.625 ;
     RECT  2.16 320.895 246.24 321.165 ;
     RECT  2.16 321.435 246.24 321.705 ;
     RECT  2.16 321.975 246.24 322.245 ;
     RECT  2.16 322.515 246.24 322.785 ;
     RECT  2.16 323.055 246.24 323.325 ;
     RECT  2.16 323.595 246.24 323.865 ;
     RECT  2.16 324.135 246.24 324.405 ;
     RECT  2.16 324.675 246.24 324.945 ;
     RECT  2.16 325.215 246.24 325.485 ;
     RECT  2.16 325.755 246.24 326.025 ;
     RECT  2.16 326.295 246.24 326.565 ;
     RECT  2.16 326.835 246.24 327.105 ;
     RECT  2.16 327.375 246.24 327.645 ;
     RECT  2.16 327.915 246.24 328.185 ;
     RECT  2.16 328.455 246.24 328.725 ;
     RECT  2.16 328.995 246.24 329.265 ;
     RECT  2.16 329.535 246.24 329.805 ;
     RECT  2.16 330.075 246.24 330.345 ;
     RECT  2.16 330.615 246.24 330.885 ;
     RECT  2.16 331.155 246.24 331.425 ;
     RECT  2.16 331.695 246.24 331.965 ;
     RECT  2.16 332.235 246.24 332.505 ;
     RECT  2.16 332.775 246.24 333.045 ;
     RECT  2.16 333.315 246.24 333.585 ;
     RECT  2.16 333.855 246.24 334.125 ;
     RECT  2.16 334.395 246.24 334.665 ;
     RECT  2.16 334.935 246.24 335.205 ;
     RECT  2.16 335.475 246.24 335.745 ;
     RECT  2.16 336.015 246.24 336.285 ;
     RECT  2.16 336.555 246.24 336.825 ;
     RECT  2.16 337.095 246.24 337.365 ;
     RECT  2.16 337.635 246.24 337.905 ;
     RECT  2.16 338.175 246.24 338.445 ;
     RECT  2.16 338.715 246.24 338.985 ;
     RECT  2.16 339.255 246.24 339.525 ;
     RECT  2.16 339.795 246.24 340.065 ;
     RECT  2.16 340.335 246.24 340.605 ;
     RECT  2.16 340.875 246.24 341.145 ;
     RECT  2.16 341.415 246.24 341.685 ;
     RECT  2.16 341.955 246.24 342.225 ;
     RECT  2.16 342.495 246.24 342.765 ;
     RECT  2.16 343.035 246.24 343.305 ;
     RECT  2.16 343.575 246.24 343.845 ;
     RECT  2.16 344.115 246.24 344.385 ;
     RECT  2.16 344.655 246.24 344.925 ;
     RECT  2.16 345.195 246.24 345.465 ;
     RECT  2.16 345.735 246.24 346.005 ;
     RECT  2.16 346.275 246.24 346.545 ;
     RECT  2.16 346.815 246.24 347.085 ;
     RECT  2.16 347.355 246.24 347.625 ;
     RECT  2.16 347.895 246.24 348.165 ;
     RECT  2.16 348.435 246.24 348.705 ;
     RECT  2.16 348.975 246.24 349.245 ;
     RECT  2.16 349.515 246.24 349.785 ;
     RECT  2.16 350.055 246.24 350.325 ;
     RECT  2.16 350.595 246.24 350.865 ;
     RECT  2.16 351.135 246.24 351.405 ;
     RECT  2.16 351.675 246.24 351.945 ;
     RECT  2.16 352.215 246.24 352.485 ;
     RECT  2.16 352.755 246.24 353.025 ;
     RECT  2.16 353.295 246.24 353.565 ;
     RECT  2.16 353.835 246.24 354.105 ;
     RECT  2.16 354.375 246.24 354.645 ;
     RECT  2.16 354.915 246.24 355.185 ;
     RECT  2.16 355.455 246.24 355.725 ;
     RECT  2.16 355.995 246.24 356.265 ;
     RECT  2.16 356.535 246.24 356.805 ;
     RECT  2.16 357.075 246.24 357.345 ;
     RECT  2.16 357.615 246.24 357.885 ;
     RECT  2.16 358.155 246.24 358.425 ;
     RECT  2.16 358.695 246.24 358.965 ;
     RECT  2.16 359.235 246.24 359.505 ;
     RECT  2.16 359.775 246.24 360.045 ;
     RECT  2.16 360.315 246.24 360.585 ;
     RECT  2.16 360.855 246.24 361.125 ;
     RECT  2.16 361.395 246.24 361.665 ;
     RECT  2.16 361.935 246.24 362.205 ;
     RECT  2.16 362.475 246.24 362.745 ;
     RECT  2.16 363.015 246.24 363.285 ;
     RECT  2.16 363.555 246.24 363.825 ;
     RECT  2.16 364.095 246.24 364.365 ;
     RECT  2.16 364.635 246.24 364.905 ;
     RECT  2.16 365.175 246.24 365.445 ;
     RECT  2.16 365.715 246.24 365.985 ;
     RECT  2.16 366.255 246.24 366.525 ;
     RECT  2.16 366.795 246.24 367.065 ;
     RECT  2.16 367.335 246.24 367.605 ;
     RECT  2.16 367.875 246.24 368.145 ;
     RECT  2.16 368.415 246.24 368.685 ;
     RECT  2.16 368.955 246.24 369.225 ;
    LAYER M1 ;
     RECT  2.16 2.151 246.24 369.369 ;
    LAYER M2 ;
     RECT  0.031 181.386 0.067 181.404 ;
     RECT  0.067 179.856 0.103 179.874 ;
     RECT  0.067 185.292 0.103 185.31 ;
     RECT  0.103 179.46 0.139 179.874 ;
     RECT  0.067 181.206 0.167 181.404 ;
     RECT  0.167 181.206 0.175 181.332 ;
     RECT  0.175 180.738 0.239 181.332 ;
     RECT  0.139 179.118 0.247 179.874 ;
     RECT  0.247 178.65 0.535 179.874 ;
     RECT  0.239 180.738 0.535 181.26 ;
     RECT  0.067 170.982 2.16 171 ;
     RECT  0.031 171.792 2.16 171.81 ;
     RECT  0.031 173.25 2.16 173.268 ;
     RECT  0.139 175.41 2.16 175.428 ;
     RECT  0.535 178.65 2.16 181.26 ;
     RECT  0.175 182.358 2.16 182.376 ;
     RECT  0.103 184.752 2.16 185.31 ;
     RECT  2.16 2.151 246.24 369.369 ;
     RECT  246.24 161.766 246.515 162.432 ;
     RECT  246.24 164.916 246.551 165.294 ;
     RECT  246.551 165.276 246.623 165.294 ;
     RECT  246.24 169.326 246.803 171.774 ;
     RECT  246.24 173.106 246.803 173.124 ;
     RECT  246.515 162.378 247.091 162.432 ;
     RECT  246.24 176.886 247.127 176.904 ;
     RECT  247.091 162.378 247.163 162.396 ;
     RECT  246.24 166.734 247.235 166.752 ;
     RECT  246.803 169.326 247.307 171.54 ;
     RECT  246.24 177.696 247.343 179.064 ;
     RECT  247.307 169.326 247.379 170.334 ;
     RECT  247.307 171.216 247.379 171.54 ;
     RECT  247.343 177.732 247.379 179.064 ;
     RECT  247.379 169.326 247.415 169.65 ;
     RECT  247.379 171.216 247.415 171.234 ;
     RECT  247.379 177.732 247.415 177.75 ;
     RECT  247.415 169.632 247.451 169.65 ;
     RECT  246.24 181.746 248.315 181.764 ;
    LAYER M3 ;
     RECT  2.415 2.143 2.505 2.413 ;
     RECT  7.815 2.143 7.905 2.413 ;
     RECT  13.215 2.143 13.305 2.413 ;
     RECT  18.615 2.143 18.705 2.413 ;
     RECT  24.015 2.143 24.105 2.413 ;
     RECT  29.415 2.143 29.505 2.413 ;
     RECT  34.815 2.143 34.905 2.413 ;
     RECT  40.215 2.143 40.305 2.413 ;
     RECT  45.615 2.143 45.705 2.413 ;
     RECT  51.015 2.143 51.105 2.413 ;
     RECT  56.415 2.143 56.505 2.413 ;
     RECT  61.815 2.143 61.905 2.413 ;
     RECT  67.215 2.143 67.305 2.413 ;
     RECT  72.615 2.143 72.705 2.413 ;
     RECT  78.015 2.143 78.105 2.413 ;
     RECT  83.415 2.143 83.505 2.413 ;
     RECT  88.815 2.143 88.905 2.413 ;
     RECT  94.215 2.143 94.305 2.413 ;
     RECT  99.615 2.143 99.705 2.413 ;
     RECT  105.015 2.143 105.105 2.413 ;
     RECT  110.415 2.143 110.505 2.413 ;
     RECT  115.815 2.143 115.905 2.413 ;
     RECT  121.215 2.143 121.305 2.413 ;
     RECT  126.615 2.143 126.705 2.413 ;
     RECT  132.015 2.143 132.105 2.413 ;
     RECT  137.415 2.143 137.505 2.413 ;
     RECT  142.815 2.143 142.905 2.413 ;
     RECT  148.215 2.143 148.305 2.413 ;
     RECT  153.615 2.143 153.705 2.413 ;
     RECT  159.015 2.143 159.105 2.413 ;
     RECT  164.415 2.143 164.505 2.413 ;
     RECT  169.815 2.143 169.905 2.413 ;
     RECT  175.215 2.143 175.305 2.413 ;
     RECT  180.615 2.143 180.705 2.413 ;
     RECT  186.015 2.143 186.105 2.413 ;
     RECT  191.415 2.143 191.505 2.413 ;
     RECT  196.815 2.143 196.905 2.413 ;
     RECT  202.215 2.143 202.305 2.413 ;
     RECT  207.615 2.143 207.705 2.413 ;
     RECT  213.015 2.143 213.105 2.413 ;
     RECT  218.415 2.143 218.505 2.413 ;
     RECT  223.815 2.143 223.905 2.413 ;
     RECT  229.215 2.143 229.305 2.413 ;
     RECT  234.615 2.143 234.705 2.413 ;
     RECT  240.015 2.143 240.105 2.413 ;
     RECT  245.415 2.143 245.505 2.413 ;
     RECT  144.576 127.111 144.594 127.237 ;
     RECT  145.368 127.111 145.386 127.237 ;
     RECT  144.108 127.237 145.386 127.243 ;
     RECT  143.82 127.243 145.386 127.571 ;
     RECT  146.412 127.579 146.43 127.777 ;
     RECT  142.815 2.413 143.097 127.813 ;
     RECT  142.668 127.813 143.097 127.849 ;
     RECT  144 127.571 145.386 127.849 ;
     RECT  140.796 127.849 141.21 127.885 ;
     RECT  140.688 127.885 141.354 127.921 ;
     RECT  142.092 127.849 143.097 127.921 ;
     RECT  144 127.849 145.458 127.921 ;
     RECT  146.304 127.777 146.43 127.921 ;
     RECT  140.688 127.921 143.154 128.155 ;
     RECT  144 127.921 146.754 128.191 ;
     RECT  144 128.191 146.97 128.219 ;
     RECT  144 128.219 144.738 128.417 ;
     RECT  140.508 128.155 143.154 128.461 ;
     RECT  144 128.417 144.63 128.461 ;
     RECT  145.656 128.219 146.97 128.759 ;
     RECT  140.508 128.461 144.63 129.235 ;
     RECT  140.508 129.235 144.666 129.271 ;
     RECT  140.256 129.271 144.666 129.361 ;
     RECT  140.256 129.361 144.738 129.397 ;
     RECT  140.112 129.397 144.738 129.433 ;
     RECT  140.112 129.433 145.134 129.437 ;
     RECT  140.796 129.437 145.134 129.767 ;
     RECT  145.872 128.759 146.97 129.775 ;
     RECT  148.215 2.413 148.497 129.775 ;
     RECT  137.415 2.413 137.697 129.811 ;
     RECT  135.972 129.901 135.99 129.973 ;
     RECT  136.8 129.811 137.697 129.973 ;
     RECT  135.972 129.973 137.697 130.009 ;
     RECT  135.972 130.009 138.186 130.081 ;
     RECT  140.904 129.767 145.134 130.243 ;
     RECT  145.872 129.775 148.497 130.243 ;
     RECT  135.972 130.081 138.906 130.279 ;
     RECT  140.112 130.171 140.13 130.279 ;
     RECT  140.904 130.243 148.497 130.279 ;
     RECT  135.972 130.279 140.13 130.315 ;
     RECT  135.54 130.315 140.13 130.379 ;
     RECT  140.904 130.279 148.626 130.477 ;
     RECT  140.904 130.477 149.346 130.541 ;
     RECT  135.972 130.379 140.13 130.843 ;
     RECT  140.904 130.541 147.402 130.843 ;
     RECT  135.972 130.843 147.402 131.009 ;
     RECT  136.116 131.009 147.402 131.431 ;
     RECT  136.116 131.431 147.438 131.549 ;
     RECT  141.984 131.549 147.438 131.557 ;
     RECT  148.215 130.541 149.346 131.557 ;
     RECT  136.116 131.549 140.958 131.971 ;
     RECT  141.984 131.557 149.346 132.089 ;
     RECT  145.656 132.089 149.346 132.125 ;
     RECT  135.972 131.971 140.958 132.221 ;
     RECT  136.224 132.221 140.958 132.367 ;
     RECT  141.984 132.089 144.918 132.367 ;
     RECT  145.8 132.125 149.346 132.737 ;
     RECT  136.224 132.367 144.918 133.051 ;
     RECT  145.8 132.737 149.166 133.051 ;
     RECT  136.224 133.051 149.166 133.169 ;
     RECT  136.224 133.169 141.462 133.229 ;
     RECT  142.2 133.169 149.166 133.349 ;
     RECT  134.856 133.825 135.09 134.059 ;
     RECT  134.064 134.095 134.082 134.131 ;
     RECT  134.856 134.059 135.126 134.131 ;
     RECT  136.692 133.229 141.462 134.131 ;
     RECT  134.064 134.131 135.342 134.203 ;
     RECT  134.064 134.203 135.738 134.237 ;
     RECT  142.524 133.349 149.166 134.257 ;
     RECT  136.692 134.131 141.534 134.365 ;
     RECT  142.488 134.257 149.166 134.365 ;
     RECT  134.208 134.237 135.738 134.401 ;
     RECT  136.692 134.365 149.166 134.401 ;
     RECT  134.208 134.401 149.166 134.519 ;
     RECT  134.208 134.519 148.734 134.825 ;
     RECT  149.508 134.941 149.958 135.031 ;
     RECT  149.508 135.031 150.03 135.067 ;
     RECT  142.488 134.825 148.734 135.301 ;
     RECT  149.508 135.067 150.606 135.301 ;
     RECT  151.704 135.211 151.722 135.329 ;
     RECT  134.208 134.825 141.678 135.337 ;
     RECT  142.488 135.301 150.606 135.337 ;
     RECT  142.488 135.337 151.254 135.635 ;
     RECT  133.848 135.337 141.678 135.643 ;
     RECT  142.488 135.635 151.218 135.643 ;
     RECT  133.848 135.643 151.218 135.913 ;
     RECT  133.524 135.913 151.218 135.949 ;
     RECT  132.015 2.413 132.297 136.255 ;
     RECT  133.02 135.949 151.218 136.255 ;
     RECT  132.015 136.255 151.218 136.715 ;
     RECT  136.152 136.715 151.218 136.751 ;
     RECT  136.296 136.751 151.218 136.795 ;
     RECT  152.172 136.651 152.658 136.795 ;
     RECT  136.296 136.795 152.658 137.327 ;
     RECT  132.015 136.715 135.378 137.461 ;
     RECT  136.296 137.327 152.514 137.489 ;
     RECT  132.015 137.461 135.558 137.515 ;
     RECT  136.296 137.489 152.442 137.515 ;
     RECT  132.015 137.515 152.442 137.759 ;
     RECT  133.092 137.759 152.442 137.903 ;
     RECT  133.2 137.903 152.442 138.461 ;
     RECT  133.2 138.461 150.93 138.839 ;
     RECT  132.015 137.759 132.297 138.859 ;
     RECT  132.015 138.859 132.606 138.911 ;
     RECT  151.812 138.461 152.442 139.117 ;
     RECT  133.38 138.839 150.93 139.261 ;
     RECT  151.812 139.117 152.478 139.261 ;
     RECT  133.38 139.261 152.478 139.495 ;
     RECT  133.38 139.495 152.766 139.657 ;
     RECT  133.308 139.657 152.766 139.675 ;
     RECT  133.2 139.675 152.766 140.459 ;
     RECT  133.2 140.459 152.622 140.765 ;
     RECT  133.38 140.765 152.622 140.801 ;
     RECT  133.776 140.801 152.622 141.277 ;
     RECT  153.615 2.413 153.897 141.277 ;
     RECT  133.776 141.277 153.897 141.575 ;
     RECT  133.776 141.575 152.586 141.647 ;
     RECT  133.776 141.647 133.974 142.027 ;
     RECT  132.015 138.911 132.297 142.231 ;
     RECT  133.2 142.027 133.974 142.231 ;
     RECT  132.015 142.231 133.974 142.301 ;
     RECT  134.82 141.647 152.586 142.321 ;
     RECT  153.324 141.575 153.897 142.321 ;
     RECT  133.2 142.301 133.974 142.501 ;
     RECT  134.82 142.321 153.897 142.501 ;
     RECT  133.2 142.501 153.897 142.591 ;
     RECT  133.2 142.591 153.954 142.735 ;
     RECT  133.2 142.735 154.206 142.771 ;
     RECT  133.2 142.771 154.638 143.437 ;
     RECT  133.056 143.437 154.638 143.851 ;
     RECT  133.056 143.851 154.962 143.969 ;
     RECT  133.056 143.969 154.494 144.275 ;
     RECT  132.015 142.301 132.297 144.811 ;
     RECT  131.688 144.811 132.297 145.057 ;
     RECT  133.056 144.275 153.954 145.057 ;
     RECT  131.688 145.057 153.954 145.291 ;
     RECT  131.688 145.291 154.386 145.325 ;
     RECT  131.76 145.325 154.386 145.705 ;
     RECT  131.76 145.705 155.034 145.903 ;
     RECT  131.76 145.903 155.25 146.011 ;
     RECT  131.76 146.011 155.502 146.059 ;
     RECT  131.22 146.059 155.502 146.371 ;
     RECT  131.184 146.371 155.502 146.515 ;
     RECT  156.852 146.677 156.87 146.713 ;
     RECT  130.788 146.515 155.502 146.749 ;
     RECT  130.788 146.749 156.042 146.777 ;
     RECT  134.352 146.777 156.042 146.821 ;
     RECT  156.78 146.713 156.87 146.821 ;
     RECT  134.352 146.821 157.338 147.047 ;
     RECT  130.788 146.777 133.578 147.595 ;
     RECT  134.352 147.047 156.942 147.595 ;
     RECT  130.788 147.595 156.942 147.901 ;
     RECT  130.788 147.901 157.482 148.019 ;
     RECT  130.788 148.019 156.798 148.559 ;
     RECT  130.788 148.559 156.726 148.595 ;
     RECT  130.788 148.595 130.986 148.667 ;
     RECT  131.724 148.595 156.726 149.243 ;
     RECT  131.724 149.243 132.39 149.369 ;
     RECT  131.724 149.369 132.297 149.377 ;
     RECT  130.788 148.667 130.806 149.512 ;
     RECT  131.688 149.377 132.297 149.512 ;
     RECT  130.788 149.512 132.297 149.549 ;
     RECT  133.236 149.243 156.726 149.647 ;
     RECT  133.236 149.647 157.302 149.791 ;
     RECT  133.236 149.791 157.806 149.909 ;
     RECT  130.788 149.549 130.806 149.933 ;
     RECT  133.236 149.909 157.302 149.945 ;
     RECT  131.616 149.549 132.297 150.259 ;
     RECT  131.616 150.259 132.498 150.295 ;
     RECT  133.236 149.945 156.942 150.295 ;
     RECT  131.616 150.295 156.942 150.493 ;
     RECT  130.464 150.961 130.482 151.033 ;
     RECT  130.464 151.033 130.554 151.105 ;
     RECT  131.508 150.493 156.942 151.141 ;
     RECT  131.508 151.141 157.05 151.231 ;
     RECT  131.292 151.231 157.05 151.259 ;
     RECT  130.32 151.105 130.554 151.339 ;
     RECT  131.292 151.259 156.726 151.339 ;
     RECT  130.32 151.339 156.726 152.447 ;
     RECT  129.528 152.419 129.546 152.455 ;
     RECT  130.32 152.447 132.39 152.455 ;
     RECT  133.2 152.447 156.726 152.455 ;
     RECT  133.2 152.455 157.158 152.491 ;
     RECT  133.2 152.491 157.662 152.609 ;
     RECT  157.644 152.609 157.662 152.717 ;
     RECT  129.096 152.455 132.39 153.031 ;
     RECT  128.628 153.031 132.39 153.197 ;
     RECT  128.772 153.197 132.39 153.265 ;
     RECT  133.2 152.609 156.726 153.265 ;
     RECT  157.788 153.661 157.806 153.697 ;
     RECT  157.608 153.697 157.806 153.769 ;
     RECT  159.015 2.413 159.297 153.769 ;
     RECT  128.772 153.265 156.726 153.995 ;
     RECT  129.528 153.995 156.726 154.039 ;
     RECT  157.608 153.769 159.297 154.039 ;
     RECT  128.772 153.995 128.79 154.139 ;
     RECT  129.528 154.039 159.297 154.921 ;
     RECT  129.24 154.921 159.297 155.155 ;
     RECT  129.096 155.155 159.297 155.191 ;
     RECT  129.096 155.191 159.642 155.213 ;
     RECT  129.78 155.213 159.642 155.309 ;
     RECT  129.78 155.309 159.297 155.615 ;
     RECT  129.96 155.615 159.297 156.569 ;
     RECT  129.96 156.569 156.762 157.009 ;
     RECT  129.924 157.009 156.762 157.199 ;
     RECT  129.924 157.199 132.642 157.339 ;
     RECT  133.416 157.199 156.762 157.477 ;
     RECT  157.5 156.569 159.297 157.477 ;
     RECT  129.42 157.339 132.642 157.505 ;
     RECT  133.416 157.477 159.297 157.621 ;
     RECT  133.416 157.621 159.606 157.891 ;
     RECT  129.78 157.505 132.642 157.981 ;
     RECT  133.416 157.891 160.146 157.981 ;
     RECT  129.78 157.981 160.146 158.009 ;
     RECT  124.632 158.395 124.794 158.431 ;
     RECT  124.236 158.431 124.866 158.593 ;
     RECT  124.164 158.593 124.866 158.629 ;
     RECT  129.78 158.009 159.606 158.693 ;
     RECT  129.78 158.693 130.41 158.827 ;
     RECT  129.276 158.827 130.41 158.863 ;
     RECT  128.628 158.863 130.41 158.965 ;
     RECT  127.98 158.965 130.41 158.999 ;
     RECT  123.516 158.629 124.866 159.005 ;
     RECT  131.184 158.693 159.606 159.097 ;
     RECT  125.712 158.161 125.73 159.169 ;
     RECT  126.615 2.413 126.897 159.169 ;
     RECT  127.98 158.999 129.366 159.205 ;
     RECT  123.732 159.005 124.866 159.241 ;
     RECT  125.712 159.169 126.897 159.241 ;
     RECT  123.732 159.241 126.897 159.269 ;
     RECT  126.54 159.269 126.897 159.359 ;
     RECT  131.184 159.097 160.038 159.359 ;
     RECT  130.14 158.999 130.41 159.475 ;
     RECT  131.184 159.359 159.75 159.475 ;
     RECT  114.516 159.475 114.534 159.511 ;
     RECT  115.815 2.413 116.097 159.511 ;
     RECT  112.428 159.511 113.382 159.547 ;
     RECT  2.415 2.413 2.697 159.595 ;
     RECT  112.428 159.547 113.562 159.601 ;
     RECT  112.392 159.601 113.778 159.643 ;
     RECT  114.516 159.511 116.097 159.643 ;
     RECT  111.456 159.643 111.474 159.673 ;
     RECT  2.304 159.595 2.697 159.709 ;
     RECT  110.415 2.413 110.697 159.736 ;
     RECT  2.304 159.709 2.862 159.745 ;
     RECT  111.42 159.673 111.474 159.745 ;
     RECT  127.944 159.205 129.366 159.745 ;
     RECT  130.14 159.475 159.75 159.745 ;
     RECT  109.224 159.739 109.242 159.779 ;
     RECT  110.412 159.736 110.697 159.781 ;
     RECT  111.42 159.745 111.51 159.781 ;
     RECT  121.215 2.413 121.497 159.781 ;
     RECT  112.392 159.643 116.097 159.809 ;
     RECT  109.692 159.781 111.51 159.899 ;
     RECT  123.732 159.269 125.73 159.899 ;
     RECT  109.764 159.899 111.51 159.907 ;
     RECT  126.615 159.359 126.897 159.907 ;
     RECT  127.764 159.745 159.75 159.907 ;
     RECT  2.268 159.745 2.862 159.935 ;
     RECT  2.304 159.935 2.862 159.979 ;
     RECT  109.764 159.907 111.618 159.979 ;
     RECT  112.392 159.809 112.446 159.979 ;
     RECT  2.304 159.979 3.186 160.007 ;
     RECT  123.732 159.899 125.694 160.051 ;
     RECT  109.764 159.979 112.446 160.079 ;
     RECT  0.108 159.691 0.126 160.123 ;
     RECT  0.036 160.123 0.126 160.157 ;
     RECT  106.596 159.601 106.614 160.169 ;
     RECT  123.696 160.051 125.694 160.177 ;
     RECT  126.615 159.907 159.75 160.177 ;
     RECT  160.668 159.979 160.686 160.177 ;
     RECT  126.615 160.177 160.794 160.249 ;
     RECT  122.544 159.871 122.562 160.285 ;
     RECT  123.624 160.177 125.694 160.285 ;
     RECT  2.415 160.007 3.186 160.321 ;
     RECT  122.544 160.285 125.694 160.349 ;
     RECT  126.615 160.249 160.866 160.411 ;
     RECT  161.604 160.171 161.622 160.411 ;
     RECT  2.415 160.321 3.906 160.439 ;
     RECT  2.415 160.439 3.186 160.475 ;
     RECT  126.615 160.411 161.622 160.519 ;
     RECT  121.215 159.781 121.77 160.591 ;
     RECT  122.544 160.349 124.722 160.591 ;
     RECT  126.615 160.519 161.658 160.591 ;
     RECT  108.864 159.943 108.882 160.681 ;
     RECT  109.872 160.079 112.446 160.681 ;
     RECT  113.184 159.809 116.097 160.681 ;
     RECT  162.864 160.555 162.882 160.709 ;
     RECT  107.496 160.681 107.514 160.717 ;
     RECT  121.215 160.591 124.722 160.733 ;
     RECT  107.424 160.717 107.514 160.753 ;
     RECT  108.396 160.681 108.882 160.753 ;
     RECT  126.615 160.591 161.766 160.753 ;
     RECT  162.54 160.717 162.558 160.753 ;
     RECT  107.424 160.753 108.882 160.861 ;
     RECT  125.64 160.349 125.694 160.861 ;
     RECT  126.615 160.753 162.558 160.861 ;
     RECT  125.64 160.861 162.558 161.015 ;
     RECT  107.424 160.861 109.134 161.059 ;
     RECT  109.872 160.681 116.097 161.059 ;
     RECT  245.415 2.413 245.697 161.401 ;
     RECT  122.76 160.733 124.722 161.491 ;
     RECT  125.64 161.015 162.45 161.491 ;
     RECT  244.692 161.401 245.697 161.789 ;
     RECT  122.76 161.491 162.45 161.869 ;
     RECT  122.76 161.869 162.486 161.905 ;
     RECT  122.76 161.905 163.062 161.941 ;
     RECT  122.76 161.941 163.17 162.059 ;
     RECT  122.76 162.059 163.062 162.211 ;
     RECT  122.436 162.211 163.062 162.239 ;
     RECT  242.244 162.211 242.334 162.329 ;
     RECT  246.492 161.761 246.51 162.373 ;
     RECT  122.436 162.239 162.738 162.401 ;
     RECT  242.316 162.329 242.334 162.437 ;
     RECT  122.508 162.401 162.738 162.599 ;
     RECT  106.56 162.481 106.578 162.607 ;
     RECT  107.424 161.059 116.097 162.607 ;
     RECT  245.124 161.789 245.697 162.635 ;
     RECT  245.415 162.635 245.697 162.751 ;
     RECT  246.492 162.373 247.158 162.751 ;
     RECT  122.544 162.599 162.738 162.869 ;
     RECT  106.344 162.607 116.097 162.905 ;
     RECT  122.616 162.869 162.738 162.941 ;
     RECT  106.344 162.905 107.73 162.985 ;
     RECT  118.584 162.751 118.602 163.013 ;
     RECT  122.832 162.941 162.738 163.021 ;
     RECT  122.832 163.021 163.386 163.139 ;
     RECT  2.415 160.475 3.006 163.319 ;
     RECT  106.308 162.985 107.73 163.381 ;
     RECT  122.868 163.139 162.954 163.409 ;
     RECT  106.272 163.381 107.73 163.489 ;
     RECT  244.584 163.561 244.602 163.679 ;
     RECT  106.056 163.489 107.73 163.687 ;
     RECT  108.648 162.905 116.097 163.687 ;
     RECT  122.868 163.409 162.378 163.949 ;
     RECT  122.868 163.949 160.362 164.021 ;
     RECT  161.244 163.949 162.378 164.021 ;
     RECT  105.015 2.413 105.297 164.029 ;
     RECT  106.056 163.687 116.097 164.029 ;
     RECT  105.015 164.029 116.097 164.219 ;
     RECT  122.868 164.021 122.994 164.219 ;
     RECT  161.496 164.021 162.378 164.371 ;
     RECT  123.732 164.021 160.362 164.489 ;
     RECT  244.548 164.371 244.566 164.489 ;
     RECT  122.832 164.335 122.85 164.569 ;
     RECT  245.415 162.751 247.158 164.641 ;
     RECT  122.544 164.569 122.85 164.669 ;
     RECT  122.832 164.669 122.85 164.717 ;
     RECT  161.496 164.371 162.522 164.767 ;
     RECT  123.768 164.489 160.362 164.911 ;
     RECT  161.1 164.767 162.522 164.911 ;
     RECT  123.768 164.911 162.522 165.067 ;
     RECT  123.768 165.067 162.558 165.109 ;
     RECT  123.768 165.109 163.602 165.209 ;
     RECT  245.124 164.641 247.158 165.335 ;
     RECT  105.015 164.219 111.618 165.343 ;
     RECT  112.392 164.219 116.097 165.343 ;
     RECT  105.015 165.343 116.097 165.691 ;
     RECT  123.768 165.209 163.53 165.721 ;
     RECT  2.415 163.319 2.697 165.811 ;
     RECT  123.66 165.721 163.53 165.811 ;
     RECT  102.6 165.721 102.618 165.839 ;
     RECT  123.3 165.811 163.53 165.839 ;
     RECT  104.616 165.691 116.097 165.875 ;
     RECT  123.3 165.839 163.098 165.931 ;
     RECT  123.156 165.931 163.098 165.983 ;
     RECT  243.792 164.101 243.81 166.261 ;
     RECT  243.792 166.261 244.386 166.379 ;
     RECT  245.415 165.335 247.158 166.423 ;
     RECT  244.908 166.423 247.158 166.685 ;
     RECT  123.3 165.983 163.098 166.693 ;
     RECT  245.415 166.685 247.158 166.729 ;
     RECT  122.544 166.693 122.562 166.829 ;
     RECT  123.3 166.693 163.278 166.919 ;
     RECT  123.3 166.919 162.81 167.063 ;
     RECT  123.3 167.063 162.558 167.179 ;
     RECT  122.832 167.179 162.558 167.225 ;
     RECT  243.792 166.379 243.81 167.269 ;
     RECT  123.12 167.225 162.558 167.459 ;
     RECT  243.792 167.269 244.062 167.459 ;
     RECT  123.12 167.459 162.09 168.619 ;
     RECT  2.415 165.811 3.186 168.781 ;
     RECT  105.015 165.875 116.097 168.809 ;
     RECT  163.476 168.619 163.494 168.809 ;
     RECT  104.04 168.715 104.058 168.845 ;
     RECT  102.6 168.781 102.618 168.953 ;
     RECT  123.048 168.619 162.09 168.961 ;
     RECT  122.652 168.961 162.09 169.147 ;
     RECT  122.508 169.147 162.09 169.223 ;
     RECT  245.415 166.729 247.23 169.321 ;
     RECT  244.584 168.781 244.602 169.349 ;
     RECT  163.332 168.811 163.35 169.385 ;
     RECT  242.316 169.357 242.334 169.501 ;
     RECT  105.015 168.809 112.338 169.529 ;
     RECT  110.016 169.529 112.338 169.591 ;
     RECT  105.015 169.529 109.062 169.619 ;
     RECT  110.016 169.591 112.41 169.621 ;
     RECT  110.016 169.621 112.59 169.627 ;
     RECT  113.328 168.809 116.097 169.627 ;
     RECT  245.415 169.321 247.41 169.627 ;
     RECT  105.015 169.619 107.766 169.771 ;
     RECT  123.192 169.223 162.09 169.861 ;
     RECT  123.192 169.861 162.45 169.933 ;
     RECT  243.792 167.459 243.81 170.005 ;
     RECT  245.415 169.627 247.446 170.093 ;
     RECT  123.192 169.933 163.314 170.203 ;
     RECT  119.916 170.203 119.934 170.251 ;
     RECT  110.016 169.627 116.097 170.275 ;
     RECT  102.6 170.131 102.618 170.311 ;
     RECT  122.58 170.203 163.314 170.311 ;
     RECT  245.415 170.093 247.374 170.311 ;
     RECT  98.604 170.167 98.622 170.339 ;
     RECT  102.6 170.311 102.834 170.339 ;
     RECT  242.244 169.501 242.334 170.339 ;
     RECT  102.816 170.339 102.834 170.381 ;
     RECT  104.868 169.771 107.766 170.401 ;
     RECT  108.54 169.619 109.062 170.401 ;
     RECT  119.916 170.251 120.222 170.429 ;
     RECT  122.544 170.311 163.314 170.437 ;
     RECT  104.868 170.401 109.062 170.473 ;
     RECT  109.98 170.275 116.097 170.473 ;
     RECT  243.792 170.005 244.026 170.545 ;
     RECT  245.268 170.311 247.374 170.545 ;
     RECT  104.868 170.473 116.097 170.581 ;
     RECT  104.544 170.581 116.097 170.699 ;
     RECT  103.608 170.539 103.626 170.735 ;
     RECT  122.4 170.437 163.314 170.851 ;
     RECT  164.415 2.413 164.697 170.851 ;
     RECT  243.612 170.545 244.026 170.851 ;
     RECT  245.124 170.545 247.374 170.851 ;
     RECT  122.4 170.851 163.35 170.969 ;
     RECT  164.124 170.851 164.697 170.969 ;
     RECT  0.036 160.157 0.054 170.977 ;
     RECT  105.015 170.699 116.097 171.005 ;
     RECT  123.156 170.969 163.17 171.005 ;
     RECT  122.4 170.969 122.418 171.011 ;
     RECT  175.215 2.413 175.497 171.112 ;
     RECT  186.015 2.413 186.297 171.112 ;
     RECT  196.815 2.413 197.097 171.112 ;
     RECT  207.615 2.413 207.897 171.112 ;
     RECT  218.415 2.413 218.697 171.112 ;
     RECT  229.215 2.413 229.497 171.112 ;
     RECT  164.304 170.969 164.697 171.149 ;
     RECT  175.104 171.112 175.497 171.149 ;
     RECT  185.904 171.112 186.297 171.149 ;
     RECT  196.704 171.112 197.097 171.149 ;
     RECT  207.504 171.112 207.897 171.149 ;
     RECT  218.304 171.112 218.697 171.149 ;
     RECT  229.104 171.112 229.497 171.149 ;
     RECT  242.316 170.339 242.334 171.149 ;
     RECT  243.612 170.851 247.374 171.211 ;
     RECT  238.428 171.115 238.446 171.259 ;
     RECT  123.156 171.005 124.434 171.275 ;
     RECT  238.32 171.259 238.446 171.293 ;
     RECT  242.532 171.259 242.55 171.319 ;
     RECT  243.612 171.211 247.41 171.319 ;
     RECT  238.32 171.293 238.338 171.391 ;
     RECT  238.284 171.391 238.338 171.392 ;
     RECT  242.532 171.319 247.41 171.392 ;
     RECT  242.532 171.392 243.018 171.509 ;
     RECT  238.284 171.392 238.302 171.545 ;
     RECT  2.415 168.781 3.366 171.625 ;
     RECT  244.152 171.392 247.41 171.629 ;
     RECT  125.28 171.005 162.99 171.689 ;
     RECT  119.088 171.517 119.106 171.751 ;
     RECT  2.415 171.625 3.438 171.779 ;
     RECT  244.152 171.629 247.23 171.779 ;
     RECT  164.415 171.149 164.697 171.787 ;
     RECT  0.036 170.977 0.09 171.815 ;
     RECT  105.015 171.005 112.05 171.931 ;
     RECT  112.824 171.005 116.097 171.931 ;
     RECT  123.48 171.275 124.434 171.931 ;
     RECT  125.28 171.689 162.954 171.931 ;
     RECT  245.16 171.779 247.23 172.013 ;
     RECT  164.415 171.787 164.934 172.021 ;
     RECT  105.015 171.931 116.097 172.057 ;
     RECT  105.015 172.057 116.622 172.093 ;
     RECT  122.724 172.123 122.742 172.129 ;
     RECT  123.48 171.931 162.954 172.129 ;
     RECT  243.936 172.123 243.954 172.201 ;
     RECT  122.724 172.129 162.954 172.319 ;
     RECT  164.124 172.021 164.934 172.319 ;
     RECT  164.124 172.319 164.697 172.327 ;
     RECT  163.98 172.327 164.697 172.397 ;
     RECT  105.015 172.093 117.342 172.471 ;
     RECT  123.516 172.319 162.954 172.471 ;
     RECT  123.516 172.471 163.242 172.589 ;
     RECT  243.396 172.201 243.954 172.589 ;
     RECT  245.16 172.013 247.122 172.589 ;
     RECT  123.624 172.589 163.242 172.661 ;
     RECT  121.215 160.733 121.497 172.699 ;
     RECT  245.16 172.589 245.697 172.699 ;
     RECT  122.724 172.319 122.742 172.733 ;
     RECT  105.015 172.471 117.846 172.831 ;
     RECT  120.852 172.699 121.497 172.859 ;
     RECT  245.124 172.699 245.697 173.129 ;
     RECT  246.78 172.589 247.122 173.129 ;
     RECT  105.015 172.831 118.314 173.137 ;
     RECT  119.052 171.751 119.106 173.137 ;
     RECT  123.624 172.661 123.822 173.165 ;
     RECT  125.172 172.661 163.242 173.165 ;
     RECT  161.496 173.165 162.09 173.171 ;
     RECT  0.072 171.815 0.09 173.245 ;
     RECT  125.172 173.165 160.65 173.273 ;
     RECT  2.415 171.779 3.366 173.371 ;
     RECT  120.996 172.859 121.497 173.399 ;
     RECT  245.34 173.129 245.697 173.399 ;
     RECT  125.172 173.273 160.362 173.407 ;
     RECT  124.74 173.407 160.362 173.507 ;
     RECT  243.396 172.589 243.414 173.507 ;
     RECT  119.844 173.479 119.862 173.551 ;
     RECT  123.804 173.165 123.822 173.551 ;
     RECT  124.74 173.507 160.038 173.551 ;
     RECT  244.584 173.551 244.602 173.705 ;
     RECT  162.936 173.165 163.242 173.849 ;
     RECT  105.015 173.137 119.106 173.899 ;
     RECT  104.904 173.899 119.106 173.939 ;
     RECT  123.804 173.551 160.038 173.939 ;
     RECT  160.812 174.019 161.046 174.055 ;
     RECT  161.892 173.171 162.09 174.055 ;
     RECT  105.015 173.939 119.106 174.091 ;
     RECT  119.844 173.551 120.006 174.091 ;
     RECT  160.812 174.055 162.198 174.091 ;
     RECT  162.936 173.849 162.954 174.091 ;
     RECT  105.015 174.091 120.006 174.217 ;
     RECT  105.015 174.217 120.15 174.361 ;
     RECT  121.215 173.399 121.497 174.361 ;
     RECT  123.948 173.939 160.038 174.361 ;
     RECT  160.812 174.091 162.954 174.361 ;
     RECT  123.948 174.361 162.954 174.365 ;
     RECT  124.02 174.365 162.954 174.749 ;
     RECT  105.015 174.361 121.497 174.821 ;
     RECT  124.02 174.749 162.198 174.821 ;
     RECT  105.015 174.821 120.402 175.361 ;
     RECT  2.415 173.371 3.546 175.369 ;
     RECT  0.036 173.245 0.09 175.405 ;
     RECT  105.015 175.361 118.782 175.433 ;
     RECT  102.6 175.369 102.618 175.559 ;
     RECT  105.015 175.433 118.566 175.559 ;
     RECT  117.108 175.559 118.566 175.595 ;
     RECT  124.02 174.821 162.09 175.631 ;
     RECT  119.556 175.361 120.402 175.829 ;
     RECT  162.936 174.749 162.954 175.829 ;
     RECT  117.216 175.595 118.566 175.865 ;
     RECT  124.02 175.631 161.982 175.949 ;
     RECT  117.324 175.865 118.566 176.099 ;
     RECT  117.324 176.099 118.494 176.243 ;
     RECT  124.02 175.949 161.694 176.251 ;
     RECT  123.156 174.091 123.174 176.413 ;
     RECT  123.948 176.251 161.694 176.413 ;
     RECT  119.592 175.829 120.402 176.485 ;
     RECT  123.156 176.413 161.694 176.521 ;
     RECT  122.544 176.521 161.694 176.717 ;
     RECT  121.215 174.821 121.497 176.791 ;
     RECT  2.415 175.369 4.266 176.881 ;
     RECT  121.215 176.791 121.806 176.881 ;
     RECT  122.544 176.717 160.182 176.881 ;
     RECT  121.215 176.881 160.182 176.909 ;
     RECT  161.496 176.717 161.694 176.909 ;
     RECT  244.116 176.791 244.134 176.909 ;
     RECT  247.104 173.129 247.122 176.909 ;
     RECT  119.592 176.485 120.474 176.953 ;
     RECT  121.215 176.909 122.67 176.953 ;
     RECT  105.015 175.559 116.37 176.989 ;
     RECT  117.432 176.243 118.494 176.989 ;
     RECT  245.415 173.399 245.697 177.025 ;
     RECT  102.6 176.881 102.618 177.053 ;
     RECT  119.52 176.953 122.67 177.061 ;
     RECT  105.015 176.989 118.494 177.089 ;
     RECT  245.415 177.025 245.79 177.179 ;
     RECT  119.412 177.061 122.67 177.187 ;
     RECT  164.124 172.397 164.697 177.187 ;
     RECT  123.696 176.909 160.182 177.323 ;
     RECT  117.432 177.089 118.494 177.331 ;
     RECT  119.34 177.187 122.67 177.331 ;
     RECT  164.124 177.187 165.294 177.449 ;
     RECT  123.696 177.323 160.074 177.521 ;
     RECT  105.015 177.089 116.694 177.529 ;
     RECT  164.124 177.449 164.697 177.565 ;
     RECT  163.692 177.565 164.697 177.629 ;
     RECT  117.432 177.331 122.67 177.719 ;
     RECT  163.872 177.629 164.697 177.719 ;
     RECT  247.32 177.691 247.338 177.727 ;
     RECT  244.584 177.061 244.674 177.755 ;
     RECT  119.124 177.719 122.67 177.799 ;
     RECT  161.496 176.909 161.514 177.799 ;
     RECT  161.1 177.799 161.514 177.829 ;
     RECT  160.956 177.829 161.514 177.835 ;
     RECT  162.36 177.799 162.378 177.835 ;
     RECT  160.956 177.835 162.378 177.869 ;
     RECT  161.1 177.869 162.378 177.989 ;
     RECT  104.58 177.529 116.694 177.997 ;
     RECT  117.432 177.719 118.314 177.997 ;
     RECT  162.252 177.989 162.27 178.025 ;
     RECT  104.58 177.997 118.314 178.097 ;
     RECT  123.696 177.521 159.822 178.097 ;
     RECT  247.32 177.727 247.41 178.157 ;
     RECT  103.752 170.851 103.77 178.169 ;
     RECT  104.58 178.097 116.766 178.169 ;
     RECT  123.696 178.097 159.75 178.169 ;
     RECT  245.415 177.179 245.697 178.231 ;
     RECT  247.32 178.157 247.374 178.231 ;
     RECT  119.124 177.799 122.958 178.303 ;
     RECT  104.58 178.169 116.73 178.411 ;
     RECT  246.816 178.231 247.374 178.411 ;
     RECT  245.088 178.231 245.697 178.501 ;
     RECT  246.78 178.411 247.374 178.501 ;
     RECT  119.124 178.303 123.678 178.529 ;
     RECT  244.116 178.411 244.134 178.529 ;
     RECT  245.088 178.501 247.374 178.529 ;
     RECT  118.116 178.097 118.314 178.537 ;
     RECT  119.124 178.529 123.426 178.537 ;
     RECT  245.124 178.529 247.374 178.541 ;
     RECT  0.036 175.405 0.162 178.645 ;
     RECT  161.1 177.989 161.514 178.645 ;
     RECT  163.152 178.411 163.17 178.681 ;
     RECT  164.124 177.719 164.697 178.681 ;
     RECT  104.436 178.411 116.73 178.799 ;
     RECT  246.78 178.541 247.374 178.799 ;
     RECT  247.32 178.799 247.374 178.829 ;
     RECT  118.116 178.537 123.426 178.835 ;
     RECT  118.116 178.835 118.314 178.907 ;
     RECT  119.124 178.835 123.426 178.907 ;
     RECT  124.56 178.169 159.75 178.915 ;
     RECT  161.028 178.645 161.514 178.915 ;
     RECT  103.5 178.915 103.518 178.939 ;
     RECT  124.38 178.915 160.11 178.951 ;
     RECT  160.92 178.915 161.514 178.951 ;
     RECT  103.5 178.939 103.842 178.973 ;
     RECT  104.58 178.799 116.73 178.973 ;
     RECT  163.152 178.681 164.697 178.973 ;
     RECT  163.656 178.973 164.697 178.979 ;
     RECT  124.38 178.951 161.658 179.069 ;
     RECT  247.356 178.829 247.374 179.069 ;
     RECT  161.1 179.069 161.514 179.105 ;
     RECT  105.015 178.973 116.73 179.113 ;
     RECT  175.215 171.149 175.497 179.311 ;
     RECT  186.015 171.149 186.297 179.311 ;
     RECT  196.815 171.149 197.097 179.311 ;
     RECT  207.615 171.149 207.897 179.311 ;
     RECT  218.415 171.149 218.697 179.311 ;
     RECT  229.215 171.149 229.497 179.311 ;
     RECT  240.015 2.413 240.297 179.311 ;
     RECT  164.304 178.979 164.697 179.357 ;
     RECT  175.104 179.311 175.497 179.357 ;
     RECT  185.904 179.311 186.297 179.357 ;
     RECT  196.704 179.311 197.097 179.357 ;
     RECT  207.504 179.311 207.897 179.357 ;
     RECT  218.304 179.311 218.697 179.357 ;
     RECT  229.104 179.311 229.497 179.357 ;
     RECT  239.904 179.311 240.297 179.357 ;
     RECT  245.124 178.541 245.697 179.357 ;
     RECT  0.036 178.645 0.27 179.383 ;
     RECT  123.408 178.907 123.426 179.411 ;
     RECT  0.036 179.383 0.486 179.419 ;
     RECT  124.38 179.069 160.254 179.419 ;
     RECT  123.84 179.419 160.254 179.483 ;
     RECT  123.84 179.483 159.786 179.609 ;
     RECT  105.015 179.113 116.838 179.689 ;
     RECT  105.015 179.689 116.874 179.995 ;
     RECT  118.116 178.907 118.134 179.995 ;
     RECT  119.124 178.907 122.562 179.995 ;
     RECT  105.015 179.995 117.27 180.031 ;
     RECT  118.116 179.995 122.562 180.031 ;
     RECT  103.824 178.973 103.842 180.091 ;
     RECT  105.015 180.031 122.562 180.091 ;
     RECT  103.824 180.091 122.562 180.125 ;
     RECT  102.636 180.301 102.654 180.391 ;
     RECT  124.38 179.609 159.786 180.499 ;
     RECT  102.6 180.391 102.654 180.535 ;
     RECT  102.6 180.535 102.69 180.599 ;
     RECT  102.672 180.599 102.69 180.689 ;
     RECT  104.544 180.125 122.562 180.689 ;
     RECT  118.944 180.689 122.562 180.715 ;
     RECT  2.415 176.881 4.302 180.805 ;
     RECT  124.38 180.499 159.858 180.841 ;
     RECT  2.304 180.805 4.302 180.941 ;
     RECT  118.944 180.715 123.102 180.995 ;
     RECT  2.415 180.941 4.302 181.103 ;
     RECT  104.544 180.689 105.534 181.111 ;
     RECT  119.124 180.995 123.102 181.273 ;
     RECT  0.036 179.419 0.558 181.409 ;
     RECT  124.38 180.841 159.966 181.499 ;
     RECT  106.416 180.689 118.17 181.615 ;
     RECT  245.415 179.357 245.697 181.627 ;
     RECT  119.124 181.273 123.246 181.651 ;
     RECT  2.415 181.103 3.762 181.675 ;
     RECT  103.86 181.111 105.534 181.741 ;
     RECT  106.416 181.615 118.35 181.741 ;
     RECT  119.124 181.651 123.462 181.769 ;
     RECT  124.56 181.499 159.966 181.769 ;
     RECT  244.872 181.627 245.697 181.769 ;
     RECT  248.292 178.603 248.31 181.769 ;
     RECT  103.86 181.741 118.35 181.811 ;
     RECT  124.668 181.769 159.966 181.813 ;
     RECT  0.072 181.409 0.558 181.901 ;
     RECT  119.124 181.769 122.274 181.913 ;
     RECT  115.632 181.811 118.35 181.921 ;
     RECT  119.124 181.913 122.13 181.921 ;
     RECT  103.86 181.811 114.822 182.039 ;
     RECT  102.924 182.011 102.942 182.048 ;
     RECT  103.968 182.039 114.822 182.075 ;
     RECT  6.804 182.011 6.822 182.111 ;
     RECT  2.304 181.675 3.762 182.119 ;
     RECT  98.604 182.047 98.622 182.183 ;
     RECT  123.048 181.769 123.462 182.299 ;
     RECT  102.672 182.083 102.69 182.309 ;
     RECT  124.668 181.813 160.146 182.309 ;
     RECT  161.1 179.105 161.118 182.309 ;
     RECT  2.304 182.119 3.978 182.317 ;
     RECT  115.632 181.921 122.13 182.345 ;
     RECT  2.196 182.317 3.978 182.381 ;
     RECT  123.048 182.299 123.75 182.381 ;
     RECT  2.415 182.381 3.978 182.461 ;
     RECT  123.624 182.381 123.75 182.461 ;
     RECT  0.072 181.901 0.198 182.573 ;
     RECT  2.415 182.461 4.194 182.579 ;
     RECT  104.22 182.075 114.822 182.731 ;
     RECT  115.632 182.345 118.566 182.731 ;
     RECT  119.304 182.345 122.13 182.731 ;
     RECT  104.22 182.731 118.566 182.849 ;
     RECT  123.624 182.461 123.93 182.849 ;
     RECT  124.704 182.309 160.146 182.885 ;
     RECT  124.704 182.885 156.15 182.921 ;
     RECT  119.304 182.731 122.562 182.957 ;
     RECT  105.015 182.849 118.566 183.235 ;
     RECT  119.304 182.957 122.526 183.235 ;
     RECT  157.14 182.885 160.146 183.271 ;
     RECT  2.415 182.579 3.906 183.389 ;
     RECT  123.624 182.849 123.642 183.389 ;
     RECT  157.14 183.271 160.326 183.397 ;
     RECT  105.015 183.235 122.526 183.533 ;
     RECT  105.015 183.533 118.386 183.659 ;
     RECT  119.304 183.533 122.346 183.695 ;
     RECT  157.14 183.397 160.866 183.703 ;
     RECT  156.78 183.703 160.866 183.739 ;
     RECT  3.564 183.389 3.906 183.929 ;
     RECT  105.015 183.659 118.35 183.929 ;
     RECT  122.328 183.695 122.346 183.929 ;
     RECT  119.304 183.695 121.497 183.965 ;
     RECT  124.704 182.921 155.934 184.045 ;
     RECT  156.672 183.739 160.866 184.045 ;
     RECT  119.592 183.965 121.497 184.073 ;
     RECT  119.808 184.073 121.497 184.109 ;
     RECT  3.888 183.929 3.906 184.235 ;
     RECT  105.015 183.929 117.522 184.351 ;
     RECT  104.76 184.351 117.522 184.397 ;
     RECT  0.072 182.573 0.126 184.775 ;
     RECT  105.015 184.397 117.522 184.781 ;
     RECT  2.415 183.389 2.697 184.891 ;
     RECT  105.015 184.781 115.002 185.275 ;
     RECT  104.904 185.275 115.002 185.279 ;
     RECT  115.74 184.781 117.522 185.287 ;
     RECT  118.296 183.929 118.35 185.287 ;
     RECT  0.072 184.775 0.09 185.315 ;
     RECT  120.456 184.109 121.497 185.323 ;
     RECT  115.74 185.287 118.35 185.357 ;
     RECT  124.704 184.045 160.866 185.371 ;
     RECT  124.236 185.371 160.866 185.395 ;
     RECT  123.696 185.395 160.866 185.431 ;
     RECT  120.456 185.323 121.59 185.453 ;
     RECT  123.696 185.431 161.226 185.453 ;
     RECT  2.415 184.891 3.15 185.549 ;
     RECT  115.74 185.357 117.45 185.557 ;
     RECT  104.904 185.279 114.93 185.585 ;
     RECT  124.272 185.453 161.226 185.621 ;
     RECT  118.26 185.357 118.35 185.657 ;
     RECT  102.6 185.521 102.618 185.693 ;
     RECT  115.704 185.557 117.45 185.819 ;
     RECT  105.015 185.585 114.93 186.169 ;
     RECT  115.704 185.819 117.378 186.169 ;
     RECT  124.272 185.621 160.866 186.367 ;
     RECT  124.272 186.367 160.938 186.379 ;
     RECT  105.015 186.169 117.378 186.539 ;
     RECT  118.296 185.657 118.35 186.773 ;
     RECT  124.164 186.379 160.938 186.781 ;
     RECT  107.172 186.539 117.378 186.899 ;
     RECT  118.296 186.773 118.314 187.079 ;
     RECT  105.015 186.539 106.254 187.169 ;
     RECT  106.236 187.169 106.254 187.313 ;
     RECT  124.164 186.781 161.01 187.483 ;
     RECT  124.164 187.483 161.118 187.517 ;
     RECT  107.172 186.899 117.306 187.781 ;
     RECT  120.456 185.453 121.497 187.817 ;
     RECT  124.452 187.517 161.118 188.141 ;
     RECT  124.704 188.141 161.118 188.393 ;
     RECT  124.704 188.393 160.866 188.555 ;
     RECT  118.584 188.491 118.602 188.669 ;
     RECT  120.816 187.817 121.497 188.789 ;
     RECT  123.624 188.635 123.642 188.941 ;
     RECT  124.704 188.555 157.878 188.941 ;
     RECT  123.624 188.941 157.878 189.005 ;
     RECT  123.984 189.005 157.878 189.059 ;
     RECT  124.452 189.059 157.878 189.203 ;
     RECT  107.172 187.781 117.27 189.211 ;
     RECT  107.172 189.211 117.306 189.329 ;
     RECT  107.172 189.329 117.162 189.437 ;
     RECT  106.632 189.445 106.65 189.485 ;
     RECT  107.496 189.437 117.162 189.707 ;
     RECT  124.704 189.203 157.878 189.751 ;
     RECT  124.704 189.751 157.914 189.985 ;
     RECT  158.652 188.555 160.866 189.985 ;
     RECT  124.704 189.985 160.866 190.049 ;
     RECT  124.704 190.049 126.897 190.349 ;
     RECT  107.496 189.707 116.946 190.381 ;
     RECT  107.172 190.381 116.946 190.589 ;
     RECT  107.172 190.589 107.334 190.679 ;
     RECT  108.072 190.589 116.946 190.831 ;
     RECT  127.764 190.049 160.866 190.831 ;
     RECT  126 190.349 126.897 190.891 ;
     RECT  127.62 190.831 160.866 190.891 ;
     RECT  108.072 190.831 117.162 190.949 ;
     RECT  124.704 190.349 124.722 191.035 ;
     RECT  126 190.891 160.866 191.093 ;
     RECT  155.412 191.093 160.866 191.129 ;
     RECT  124.596 191.035 124.722 191.191 ;
     RECT  126 191.093 154.458 191.191 ;
     RECT  124.596 191.191 154.458 191.291 ;
     RECT  108.072 190.949 116.478 191.327 ;
     RECT  108.072 191.327 116.406 191.399 ;
     RECT  107.172 190.679 107.19 191.767 ;
     RECT  108.072 191.399 116.19 191.767 ;
     RECT  107.172 191.767 116.19 192.029 ;
     RECT  107.172 192.029 116.154 192.101 ;
     RECT  155.592 191.129 160.866 192.109 ;
     RECT  124.704 191.291 154.458 192.145 ;
     RECT  155.232 192.109 160.866 192.145 ;
     RECT  124.704 192.145 160.866 192.721 ;
     RECT  107.172 192.101 116.097 192.763 ;
     RECT  124.704 192.721 161.19 193.117 ;
     RECT  124.56 193.117 161.73 193.229 ;
     RECT  107.136 192.763 116.097 193.277 ;
     RECT  107.748 193.277 116.097 193.379 ;
     RECT  107.748 193.379 114.534 193.415 ;
     RECT  124.704 193.229 161.73 193.415 ;
     RECT  124.704 193.415 160.866 193.757 ;
     RECT  108.072 193.415 114.534 193.919 ;
     RECT  108.072 193.919 108.09 194.261 ;
     RECT  109.404 193.919 114.534 194.297 ;
     RECT  161.712 193.415 161.73 194.341 ;
     RECT  109.404 194.297 109.566 194.459 ;
     RECT  110.304 194.297 114.534 194.531 ;
     RECT  125.928 193.757 160.866 194.611 ;
     RECT  110.304 194.531 113.814 194.621 ;
     RECT  109.404 194.459 109.422 194.639 ;
     RECT  110.415 194.621 113.814 194.639 ;
     RECT  125.64 194.611 160.866 194.683 ;
     RECT  110.415 194.639 113.742 194.729 ;
     RECT  125.496 194.683 160.866 194.845 ;
     RECT  161.712 194.341 161.802 194.845 ;
     RECT  110.415 194.729 111.366 194.873 ;
     RECT  124.704 193.757 124.722 194.923 ;
     RECT  125.496 194.845 161.802 194.923 ;
     RECT  112.716 194.729 113.382 194.999 ;
     RECT  124.704 194.923 161.802 194.999 ;
     RECT  112.824 194.999 112.842 195.071 ;
     RECT  124.704 194.999 161.01 195.149 ;
     RECT  128.304 195.149 161.01 195.853 ;
     RECT  128.304 195.853 161.046 195.925 ;
     RECT  128.268 195.925 161.046 195.961 ;
     RECT  161.784 194.999 161.802 195.961 ;
     RECT  124.704 195.149 127.53 196.087 ;
     RECT  128.268 195.961 161.802 196.087 ;
     RECT  124.704 196.087 161.802 197.311 ;
     RECT  124.704 197.311 162.054 197.851 ;
     RECT  124.704 197.851 162.126 198.121 ;
     RECT  124.704 198.121 162.234 198.589 ;
     RECT  124.704 198.589 162.27 198.689 ;
     RECT  125.46 198.689 162.27 198.823 ;
     RECT  125.46 198.823 162.306 198.941 ;
     RECT  125.856 198.941 162.306 199.589 ;
     RECT  124.704 198.689 124.722 199.975 ;
     RECT  125.856 199.589 162.27 199.975 ;
     RECT  124.704 199.975 162.27 200.045 ;
     RECT  125.64 200.045 162.27 200.717 ;
     RECT  126 200.717 162.27 200.849 ;
     RECT  126.036 200.849 162.27 200.939 ;
     RECT  124.704 200.045 124.722 201.739 ;
     RECT  126.036 200.939 162.09 201.739 ;
     RECT  124.704 201.739 162.09 201.785 ;
     RECT  125.784 201.785 162.09 202.829 ;
     RECT  124.704 201.785 124.722 202.981 ;
     RECT  124.704 202.981 124.902 203.251 ;
     RECT  125.784 202.829 161.802 203.251 ;
     RECT  124.704 203.251 161.802 203.369 ;
     RECT  129.6 203.369 161.802 203.639 ;
     RECT  129.6 203.639 161.478 203.783 ;
     RECT  124.704 203.369 128.79 204.151 ;
     RECT  129.6 203.783 160.758 204.151 ;
     RECT  124.704 204.151 160.758 205.169 ;
     RECT  125.856 205.169 160.758 205.259 ;
     RECT  124.704 205.169 125.082 205.367 ;
     RECT  126.072 205.259 160.758 205.376 ;
     RECT  126.108 205.376 160.758 205.403 ;
     RECT  126.108 205.403 128.322 205.529 ;
     RECT  129.348 205.403 160.758 205.529 ;
     RECT  126.54 205.529 128.322 205.709 ;
     RECT  129.384 205.529 160.758 206.141 ;
     RECT  126.54 205.709 128.07 206.491 ;
     RECT  129.384 206.141 132.75 206.491 ;
     RECT  126.54 206.491 132.75 206.519 ;
     RECT  133.632 206.141 160.758 206.887 ;
     RECT  126.615 206.519 132.75 207.031 ;
     RECT  133.56 206.887 160.758 207.031 ;
     RECT  126.615 207.031 160.758 207.301 ;
     RECT  126.615 207.301 160.902 207.773 ;
     RECT  126.615 207.773 128.898 207.841 ;
     RECT  129.672 207.773 160.902 207.869 ;
     RECT  126.54 207.841 128.898 208.111 ;
     RECT  126.216 208.111 128.898 208.237 ;
     RECT  126.108 208.237 128.898 208.615 ;
     RECT  129.924 207.869 160.902 208.615 ;
     RECT  126.108 208.615 160.902 208.925 ;
     RECT  126.576 208.925 160.902 209.453 ;
     RECT  126.576 209.453 160.758 210.271 ;
     RECT  126.54 210.271 160.758 210.379 ;
     RECT  126.396 210.379 160.758 210.425 ;
     RECT  126.396 210.425 155.106 210.497 ;
     RECT  155.88 210.425 160.758 210.542 ;
     RECT  155.916 210.542 160.758 210.659 ;
     RECT  156.024 210.659 160.758 210.731 ;
     RECT  156.132 210.731 160.758 210.803 ;
     RECT  126.396 210.497 155.034 211.351 ;
     RECT  156.24 210.803 160.758 211.379 ;
     RECT  126.396 211.351 155.25 211.441 ;
     RECT  126.396 211.441 155.394 211.469 ;
     RECT  126.615 211.469 155.394 211.585 ;
     RECT  126.615 211.585 155.466 211.621 ;
     RECT  156.24 211.379 160.362 211.621 ;
     RECT  124.704 205.367 124.722 211.919 ;
     RECT  126.615 211.621 160.362 212.189 ;
     RECT  128.268 212.189 160.362 212.279 ;
     RECT  126.615 212.189 127.494 212.315 ;
     RECT  128.376 212.279 160.362 212.621 ;
     RECT  128.376 212.621 160.29 212.999 ;
     RECT  128.376 212.999 159.822 213.197 ;
     RECT  156.672 213.197 159.822 213.395 ;
     RECT  128.376 213.197 155.826 214.285 ;
     RECT  156.708 213.395 159.822 214.285 ;
     RECT  128.376 214.285 159.822 215.591 ;
     RECT  128.376 215.591 128.394 216.445 ;
     RECT  129.168 215.591 159.822 216.445 ;
     RECT  128.376 216.445 159.822 218.489 ;
     RECT  129.204 218.489 159.822 218.669 ;
     RECT  129.564 218.669 159.822 219.443 ;
     RECT  129.564 219.443 154.89 219.605 ;
     RECT  129.564 219.605 154.674 220.061 ;
     RECT  155.88 219.443 159.822 220.109 ;
     RECT  129.852 220.061 154.674 220.451 ;
     RECT  155.88 220.109 159.678 220.523 ;
     RECT  130.104 220.451 154.674 220.891 ;
     RECT  130.104 220.891 154.998 220.919 ;
     RECT  130.104 220.919 130.122 220.991 ;
     RECT  130.968 220.919 154.998 221.035 ;
     RECT  130.968 221.035 155.106 221.189 ;
     RECT  155.952 220.523 159.678 221.539 ;
     RECT  131.148 221.189 155.106 221.611 ;
     RECT  155.844 221.539 159.678 221.611 ;
     RECT  131.148 221.611 159.678 221.729 ;
     RECT  131.148 221.729 159.297 222.035 ;
     RECT  151.632 222.035 158.238 222.143 ;
     RECT  156.636 222.143 158.238 222.269 ;
     RECT  151.632 222.143 155.574 222.305 ;
     RECT  156.636 222.269 157.77 222.305 ;
     RECT  131.148 222.035 150.57 222.313 ;
     RECT  156.888 222.305 157.77 222.341 ;
     RECT  157.752 222.341 157.77 222.539 ;
     RECT  130.968 222.313 150.57 222.611 ;
     RECT  151.632 222.305 155.394 222.719 ;
     RECT  151.632 222.719 154.566 222.845 ;
     RECT  131.4 222.611 150.57 222.961 ;
     RECT  151.632 222.845 154.494 222.961 ;
     RECT  131.4 222.961 154.494 223.079 ;
     RECT  131.4 223.079 154.386 223.151 ;
     RECT  155.376 222.719 155.394 223.259 ;
     RECT  156.888 222.341 156.906 223.619 ;
     RECT  131.4 223.151 154.35 223.771 ;
     RECT  131.292 223.771 154.35 224.159 ;
     RECT  131.364 224.159 154.35 224.969 ;
     RECT  131.868 224.969 154.35 225.113 ;
     RECT  131.868 225.113 154.062 225.149 ;
     RECT  132.015 225.149 154.062 225.689 ;
     RECT  132.015 225.689 153.897 226.121 ;
     RECT  132.015 226.121 134.766 226.229 ;
     RECT  132.015 226.229 134.694 226.411 ;
     RECT  131.796 226.411 134.694 226.463 ;
     RECT  132.015 226.463 134.694 226.975 ;
     RECT  135.684 226.121 153.897 226.975 ;
     RECT  132.015 226.975 153.897 227.129 ;
     RECT  132.015 227.129 152.658 227.399 ;
     RECT  132.015 227.399 152.514 227.419 ;
     RECT  131.94 227.419 152.514 227.471 ;
     RECT  132.015 227.471 152.514 227.939 ;
     RECT  132.015 227.939 152.442 227.981 ;
     RECT  132.015 227.981 152.334 228.047 ;
     RECT  150.156 228.047 152.334 228.083 ;
     RECT  132.015 228.047 149.31 228.209 ;
     RECT  150.156 228.083 152.298 228.245 ;
     RECT  150.228 228.245 152.298 228.317 ;
     RECT  132.015 228.209 149.274 228.389 ;
     RECT  150.228 228.317 152.262 228.479 ;
     RECT  150.228 228.479 150.246 228.515 ;
     RECT  151.344 228.479 152.118 228.515 ;
     RECT  132.015 228.389 148.662 228.551 ;
     RECT  151.344 228.515 151.578 228.551 ;
     RECT  133.704 228.551 148.662 228.659 ;
     RECT  133.704 228.659 134.874 228.749 ;
     RECT  135.612 228.659 148.662 229.171 ;
     RECT  133.704 228.749 134.802 229.289 ;
     RECT  135.612 229.171 148.806 229.289 ;
     RECT  133.884 229.289 134.802 229.325 ;
     RECT  133.956 229.325 134.802 229.469 ;
     RECT  134.496 229.469 134.658 229.559 ;
     RECT  135.612 229.289 148.662 229.559 ;
     RECT  134.496 229.559 134.514 229.595 ;
     RECT  135.756 229.559 148.662 230.285 ;
     RECT  136.26 230.285 148.662 230.341 ;
     RECT  136.26 230.341 148.734 230.981 ;
     RECT  136.26 230.981 146.646 231.017 ;
     RECT  136.296 231.017 146.646 231.287 ;
     RECT  136.656 231.287 146.646 231.871 ;
     RECT  147.384 230.981 148.734 231.871 ;
     RECT  136.656 231.871 148.734 232.025 ;
     RECT  137.196 232.025 148.734 232.331 ;
     RECT  137.196 232.331 148.662 232.835 ;
     RECT  137.196 232.835 139.338 232.907 ;
     RECT  137.196 232.907 139.266 232.979 ;
     RECT  137.196 232.979 139.23 233.185 ;
     RECT  136.8 233.185 139.23 233.339 ;
     RECT  140.22 232.835 148.662 233.375 ;
     RECT  136.656 233.419 136.674 233.483 ;
     RECT  140.22 233.375 146.682 233.617 ;
     RECT  140.112 233.617 146.682 233.725 ;
     RECT  137.415 233.339 139.23 233.851 ;
     RECT  140.04 233.725 146.682 233.851 ;
     RECT  137.415 233.851 146.682 234.157 ;
     RECT  147.492 233.375 148.662 234.157 ;
     RECT  137.415 234.157 148.662 234.535 ;
     RECT  137.088 234.535 148.662 234.605 ;
     RECT  137.088 234.605 146.898 234.725 ;
     RECT  137.376 234.725 146.898 235.139 ;
     RECT  147.744 234.605 148.662 235.345 ;
     RECT  137.412 235.139 146.898 235.381 ;
     RECT  147.672 235.345 148.662 235.381 ;
     RECT  137.412 235.381 148.662 235.643 ;
     RECT  137.412 235.643 146.97 235.769 ;
     RECT  147.744 235.643 148.662 235.769 ;
     RECT  137.412 235.769 139.95 235.901 ;
     RECT  140.796 235.769 146.97 235.997 ;
     RECT  137.415 235.901 139.518 236.111 ;
     RECT  139.104 236.111 139.518 236.183 ;
     RECT  137.415 236.111 138.366 236.309 ;
     RECT  139.104 236.183 139.122 236.309 ;
     RECT  140.796 235.997 146.898 236.695 ;
     RECT  148.215 235.769 148.662 236.731 ;
     RECT  139.896 236.731 139.914 236.849 ;
     RECT  147.636 236.731 148.662 236.849 ;
     RECT  140.688 236.695 146.898 236.857 ;
     RECT  139.716 236.929 139.734 237.005 ;
     RECT  148.215 236.849 148.662 237.119 ;
     RECT  140.472 236.857 147.186 237.155 ;
     RECT  140.796 237.155 146.79 237.659 ;
     RECT  140.796 237.659 143.802 237.821 ;
     RECT  144.576 237.659 146.79 237.929 ;
     RECT  144.576 237.929 146.394 237.965 ;
     RECT  140.796 237.821 143.658 238.411 ;
     RECT  140.4 238.411 143.658 238.891 ;
     RECT  144.576 237.965 146.286 238.891 ;
     RECT  140.4 238.891 146.286 239.009 ;
     RECT  144.684 239.009 146.286 239.045 ;
     RECT  140.4 239.009 143.838 239.165 ;
     RECT  144.792 239.045 146.286 239.279 ;
     RECT  140.4 239.165 143.622 239.351 ;
     RECT  144.864 239.279 146.286 239.395 ;
     RECT  147.024 239.359 147.042 239.395 ;
     RECT  144.864 239.395 147.042 239.431 ;
     RECT  148.215 237.119 148.497 239.431 ;
     RECT  141.12 239.351 143.622 239.549 ;
     RECT  144.864 239.431 148.497 239.549 ;
     RECT  144.864 239.549 147.042 239.585 ;
     RECT  144.864 239.585 146.79 239.729 ;
     RECT  141.12 239.549 143.55 239.819 ;
     RECT  144.972 239.729 146.25 239.819 ;
     RECT  141.12 239.819 141.354 239.927 ;
     RECT  145.8 239.819 146.214 239.933 ;
     RECT  141.12 239.927 141.138 239.936 ;
     RECT  144.972 239.819 144.99 239.963 ;
     RECT  142.092 239.819 143.406 240.089 ;
     RECT  145.8 239.933 145.818 240.089 ;
     RECT  132.015 228.551 132.606 250.195 ;
     RECT  132.015 250.195 132.714 272.443 ;
     RECT  132.015 272.443 133.362 273.029 ;
     RECT  132.015 273.029 132.822 273.065 ;
     RECT  128.376 218.489 128.394 286.799 ;
     RECT  2.415 185.549 2.697 369.107 ;
     RECT  7.815 2.413 8.097 369.107 ;
     RECT  13.215 2.413 13.497 369.107 ;
     RECT  18.615 2.413 18.897 369.107 ;
     RECT  24.015 2.413 24.297 369.107 ;
     RECT  29.415 2.413 29.697 369.107 ;
     RECT  34.815 2.413 35.097 369.107 ;
     RECT  40.215 2.413 40.497 369.107 ;
     RECT  45.615 2.413 45.897 369.107 ;
     RECT  51.015 2.413 51.297 369.107 ;
     RECT  56.415 2.413 56.697 369.107 ;
     RECT  61.815 2.413 62.097 369.107 ;
     RECT  67.215 2.413 67.497 369.107 ;
     RECT  72.615 2.413 72.897 369.107 ;
     RECT  78.015 2.413 78.297 369.107 ;
     RECT  83.415 2.413 83.697 369.107 ;
     RECT  88.815 2.413 89.097 369.107 ;
     RECT  94.215 2.413 94.497 369.107 ;
     RECT  99.615 2.413 99.897 369.107 ;
     RECT  105.015 187.169 105.297 369.107 ;
     RECT  110.415 194.873 110.697 369.107 ;
     RECT  115.815 193.379 116.097 369.107 ;
     RECT  121.215 188.789 121.497 369.107 ;
     RECT  126.615 212.315 126.897 369.107 ;
     RECT  137.415 236.309 137.697 369.107 ;
     RECT  142.815 240.089 143.097 369.107 ;
     RECT  148.215 239.549 148.497 369.107 ;
     RECT  153.615 227.129 153.897 369.107 ;
     RECT  159.015 222.035 159.297 369.107 ;
     RECT  164.415 179.357 164.697 369.107 ;
     RECT  169.815 2.413 170.097 369.107 ;
     RECT  175.215 179.357 175.497 369.107 ;
     RECT  180.615 2.413 180.897 369.107 ;
     RECT  186.015 179.357 186.297 369.107 ;
     RECT  191.415 2.413 191.697 369.107 ;
     RECT  196.815 179.357 197.097 369.107 ;
     RECT  202.215 2.413 202.497 369.107 ;
     RECT  207.615 179.357 207.897 369.107 ;
     RECT  213.015 2.413 213.297 369.107 ;
     RECT  218.415 179.357 218.697 369.107 ;
     RECT  223.815 2.413 224.097 369.107 ;
     RECT  229.215 179.357 229.497 369.107 ;
     RECT  234.615 2.413 234.897 369.107 ;
     RECT  240.015 179.357 240.297 369.107 ;
     RECT  245.415 181.769 245.697 369.107 ;
     RECT  2.415 369.107 2.505 369.377 ;
     RECT  7.815 369.107 7.905 369.377 ;
     RECT  13.215 369.107 13.305 369.377 ;
     RECT  18.615 369.107 18.705 369.377 ;
     RECT  24.015 369.107 24.105 369.377 ;
     RECT  29.415 369.107 29.505 369.377 ;
     RECT  34.815 369.107 34.905 369.377 ;
     RECT  40.215 369.107 40.305 369.377 ;
     RECT  45.615 369.107 45.705 369.377 ;
     RECT  51.015 369.107 51.105 369.377 ;
     RECT  56.415 369.107 56.505 369.377 ;
     RECT  61.815 369.107 61.905 369.377 ;
     RECT  67.215 369.107 67.305 369.377 ;
     RECT  72.615 369.107 72.705 369.377 ;
     RECT  78.015 369.107 78.105 369.377 ;
     RECT  83.415 369.107 83.505 369.377 ;
     RECT  88.815 369.107 88.905 369.377 ;
     RECT  94.215 369.107 94.305 369.377 ;
     RECT  99.615 369.107 99.705 369.377 ;
     RECT  105.015 369.107 105.105 369.377 ;
     RECT  110.415 369.107 110.505 369.377 ;
     RECT  115.815 369.107 115.905 369.377 ;
     RECT  121.215 369.107 121.305 369.377 ;
     RECT  126.615 369.107 126.705 369.377 ;
     RECT  132.015 273.065 132.714 369.377 ;
     RECT  137.415 369.107 137.505 369.377 ;
     RECT  142.815 369.107 142.905 369.377 ;
     RECT  148.215 369.107 148.305 369.377 ;
     RECT  153.615 369.107 153.705 369.377 ;
     RECT  159.015 369.107 159.105 369.377 ;
     RECT  164.415 369.107 164.505 369.377 ;
     RECT  169.815 369.107 169.905 369.377 ;
     RECT  175.215 369.107 175.305 369.377 ;
     RECT  180.615 369.107 180.705 369.377 ;
     RECT  186.015 369.107 186.105 369.377 ;
     RECT  191.415 369.107 191.505 369.377 ;
     RECT  196.815 369.107 196.905 369.377 ;
     RECT  202.215 369.107 202.305 369.377 ;
     RECT  207.615 369.107 207.705 369.377 ;
     RECT  213.015 369.107 213.105 369.377 ;
     RECT  218.415 369.107 218.505 369.377 ;
     RECT  223.815 369.107 223.905 369.377 ;
     RECT  229.215 369.107 229.305 369.377 ;
     RECT  234.615 369.107 234.705 369.377 ;
     RECT  240.015 369.107 240.105 369.377 ;
     RECT  245.415 369.107 245.505 369.377 ;
     RECT  132.156 369.377 132.714 370.493 ;
     RECT  132.156 370.493 132.174 370.541 ;
    LAYER M4 ;
     RECT  0.025 160.128 0.06 160.152 ;
     RECT  0.06 159.6 0.137 160.152 ;
     RECT  0.06 179.568 0.137 182.568 ;
     RECT  0.137 179.664 0.173 182.568 ;
     RECT  0.173 179.76 0.209 182.568 ;
     RECT  0.209 179.76 0.569 182.376 ;
     RECT  0.137 159.6 2.408 160.008 ;
     RECT  0.569 180.432 2.408 182.376 ;
     RECT  2.408 2.148 2.512 369.372 ;
     RECT  2.512 2.418 2.704 369.102 ;
     RECT  2.704 180.432 2.837 182.184 ;
     RECT  2.837 180.432 2.945 182.088 ;
     RECT  2.945 181.008 3.089 182.088 ;
     RECT  2.704 159.984 3.197 160.008 ;
     RECT  3.089 181.008 3.269 181.032 ;
     RECT  3.089 182.064 3.413 182.088 ;
     RECT  7.808 2.148 7.912 369.372 ;
     RECT  7.912 2.418 8.104 369.102 ;
     RECT  13.208 2.148 13.312 369.372 ;
     RECT  13.312 2.418 13.504 369.102 ;
     RECT  18.608 2.148 18.712 369.372 ;
     RECT  18.712 2.418 18.904 369.102 ;
     RECT  24.008 2.148 24.112 369.372 ;
     RECT  24.112 2.418 24.304 369.102 ;
     RECT  29.408 2.148 29.512 369.372 ;
     RECT  29.512 2.418 29.704 369.102 ;
     RECT  34.808 2.148 34.912 369.372 ;
     RECT  34.912 2.418 35.104 369.102 ;
     RECT  40.208 2.148 40.312 369.372 ;
     RECT  40.312 2.418 40.504 369.102 ;
     RECT  45.608 2.148 45.712 369.372 ;
     RECT  45.712 2.418 45.904 369.102 ;
     RECT  51.008 2.148 51.112 369.372 ;
     RECT  51.112 2.418 51.304 369.102 ;
     RECT  56.408 2.148 56.512 369.372 ;
     RECT  56.512 2.418 56.704 369.102 ;
     RECT  61.808 2.148 61.912 369.372 ;
     RECT  61.912 2.418 62.104 369.102 ;
     RECT  67.208 2.148 67.312 369.372 ;
     RECT  67.312 2.418 67.504 369.102 ;
     RECT  72.608 2.148 72.712 369.372 ;
     RECT  72.712 2.418 72.904 369.102 ;
     RECT  78.008 2.148 78.112 369.372 ;
     RECT  78.112 2.418 78.304 369.102 ;
     RECT  83.408 2.148 83.512 369.372 ;
     RECT  83.512 2.418 83.704 369.102 ;
     RECT  88.808 2.148 88.912 369.372 ;
     RECT  88.912 2.418 89.104 369.102 ;
     RECT  94.208 2.148 94.312 369.372 ;
     RECT  94.312 2.418 94.504 369.102 ;
     RECT  99.608 2.148 99.712 369.372 ;
     RECT  99.712 2.418 99.904 369.102 ;
     RECT  102.805 170.352 103.597 170.376 ;
     RECT  104.749 184.368 104.849 184.392 ;
     RECT  104.029 168.72 104.869 168.744 ;
     RECT  104.849 184.368 104.869 185.304 ;
     RECT  104.605 165.696 105.008 165.72 ;
     RECT  104.869 168.72 105.008 169.368 ;
     RECT  103.597 170.352 105.008 170.568 ;
     RECT  104.849 173.904 105.008 173.928 ;
     RECT  103.489 178.944 105.008 178.968 ;
     RECT  103.813 180.096 105.008 180.12 ;
     RECT  102.913 182.016 105.008 182.04 ;
     RECT  104.869 183.792 105.008 185.304 ;
     RECT  105.008 2.148 105.112 369.372 ;
     RECT  105.112 2.418 105.304 369.102 ;
     RECT  105.304 170.544 105.473 171 ;
     RECT  105.304 173.232 105.473 176.712 ;
     RECT  105.473 173.232 105.484 175.848 ;
     RECT  105.304 168.624 105.581 169.368 ;
     RECT  105.484 173.232 105.875 174.888 ;
     RECT  105.875 174.432 105.905 174.888 ;
     RECT  105.304 178.944 106.157 178.968 ;
     RECT  105.304 165.312 106.369 165.72 ;
     RECT  105.304 181.776 106.445 181.8 ;
     RECT  106.369 165.312 106.585 166.104 ;
     RECT  105.304 167.184 106.597 167.208 ;
     RECT  106.585 164.976 106.621 166.104 ;
     RECT  106.597 167.184 106.621 167.496 ;
     RECT  105.304 184.08 106.621 184.104 ;
     RECT  106.621 164.976 106.643 167.496 ;
     RECT  106.643 166.368 106.684 167.496 ;
     RECT  106.643 164.976 106.689 165.336 ;
     RECT  106.684 166.368 106.704 167.208 ;
     RECT  106.765 179.136 106.837 179.16 ;
     RECT  105.304 180.144 106.837 180.168 ;
     RECT  105.473 170.976 106.877 171 ;
     RECT  105.905 174.864 106.909 174.888 ;
     RECT  106.621 184.08 106.909 184.68 ;
     RECT  106.909 184.08 106.945 184.824 ;
     RECT  105.581 168.624 107.053 168.648 ;
     RECT  107.053 168.576 107.125 168.648 ;
     RECT  106.645 192.768 107.125 192.792 ;
     RECT  106.837 179.136 107.153 180.168 ;
     RECT  107.125 192.768 107.165 193.272 ;
     RECT  106.604 189.456 107.173 189.48 ;
     RECT  107.161 190.56 107.173 190.584 ;
     RECT  106.621 185.808 107.197 185.832 ;
     RECT  107.153 179.136 107.219 180.216 ;
     RECT  106.945 183.408 107.237 184.824 ;
     RECT  107.173 189.456 107.245 190.584 ;
     RECT  105.304 177.696 107.269 177.72 ;
     RECT  107.269 177.264 107.309 177.72 ;
     RECT  107.237 183.408 107.309 184.68 ;
     RECT  107.228 182.304 107.315 182.328 ;
     RECT  107.405 162.432 107.413 162.456 ;
     RECT  106.297 163.68 107.413 163.704 ;
     RECT  107.219 180.144 107.413 180.216 ;
     RECT  107.269 181.248 107.413 181.272 ;
     RECT  106.909 174.864 107.417 175.608 ;
     RECT  107.413 180.144 107.453 181.272 ;
     RECT  107.365 187.488 107.453 187.512 ;
     RECT  107.413 162.432 107.489 164.376 ;
     RECT  107.125 168.432 107.557 168.648 ;
     RECT  106.597 169.776 107.557 169.8 ;
     RECT  107.417 174.96 107.633 175.608 ;
     RECT  107.245 189.456 107.701 189.864 ;
     RECT  107.219 179.136 107.741 179.16 ;
     RECT  107.701 189.312 107.741 189.864 ;
     RECT  107.557 168.432 107.777 169.8 ;
     RECT  107.165 193.248 107.777 193.272 ;
     RECT  106.873 172.944 107.809 172.968 ;
     RECT  107.489 162.864 107.845 164.376 ;
     RECT  107.845 162.864 108.029 164.568 ;
     RECT  107.197 185.808 108.173 186.36 ;
     RECT  107.309 183.792 108.205 184.68 ;
     RECT  108.029 164.16 108.241 164.568 ;
     RECT  106.704 166.368 108.281 166.488 ;
     RECT  107.309 177.264 108.313 177.288 ;
     RECT  108.205 183.792 108.349 184.776 ;
     RECT  107.809 171.504 108.353 172.968 ;
     RECT  108.349 183.456 108.385 184.776 ;
     RECT  108.277 173.952 108.421 173.976 ;
     RECT  107.633 174.96 108.421 174.984 ;
     RECT  107.453 180.144 108.493 180.696 ;
     RECT  107.777 168.432 108.497 169.464 ;
     RECT  108.421 173.952 108.569 174.984 ;
     RECT  108.385 182.928 108.641 184.776 ;
     RECT  108.173 186.336 108.781 186.36 ;
     RECT  107.741 189.312 108.781 189.336 ;
     RECT  108.641 184.128 108.785 184.776 ;
     RECT  108.313 176.976 108.853 177.288 ;
     RECT  108.457 178.416 108.853 178.44 ;
     RECT  108.493 179.904 108.853 180.696 ;
     RECT  108.781 188.64 108.865 189.336 ;
     RECT  107.989 161.088 108.889 161.112 ;
     RECT  108.353 171.504 108.889 171.528 ;
     RECT  108.781 186.336 108.925 186.408 ;
     RECT  108.497 168.72 108.929 169.464 ;
     RECT  108.889 171.024 108.929 171.528 ;
     RECT  108.853 176.976 108.937 181.512 ;
     RECT  108.937 176.976 108.956 177.096 ;
     RECT  108.241 164.16 108.997 164.616 ;
     RECT  108.029 162.864 109.033 162.888 ;
     RECT  108.997 163.872 109.033 164.616 ;
     RECT  108.281 166.464 109.043 166.488 ;
     RECT  108.569 174.336 109.043 174.984 ;
     RECT  108.956 176.064 109.043 177.096 ;
     RECT  108.889 160.944 109.073 161.112 ;
     RECT  108.349 191.088 109.1 191.112 ;
     RECT  108.929 168.72 109.109 169.416 ;
     RECT  108.937 179.52 109.132 181.512 ;
     RECT  109.1 191.088 109.141 191.928 ;
     RECT  108.637 193.824 109.141 193.848 ;
     RECT  109.043 174.336 109.181 174.36 ;
     RECT  108.865 189.312 109.181 189.336 ;
     RECT  109.141 193.488 109.253 193.848 ;
     RECT  109.141 190.32 109.331 191.928 ;
     RECT  109.177 161.328 109.393 161.544 ;
     RECT  109.033 162.864 109.393 164.616 ;
     RECT  108.353 172.608 109.393 172.968 ;
     RECT  109.043 176.448 109.397 177.096 ;
     RECT  109.393 161.328 109.429 164.616 ;
     RECT  108.925 186.336 109.645 186.456 ;
     RECT  109.645 186.24 109.676 186.456 ;
     RECT  108.929 171.024 109.753 171.048 ;
     RECT  109.132 179.904 109.969 181.512 ;
     RECT  108.641 182.928 109.969 182.952 ;
     RECT  109.676 185.52 110.005 186.456 ;
     RECT  110.005 185.52 110.053 187.272 ;
     RECT  109.753 170.976 110.101 171.048 ;
     RECT  109.393 172.608 110.101 173.016 ;
     RECT  109.213 159.744 110.408 159.768 ;
     RECT  109.429 161.328 110.408 165.864 ;
     RECT  109.321 166.944 110.408 166.968 ;
     RECT  109.109 168.72 110.408 168.744 ;
     RECT  110.101 170.976 110.408 173.016 ;
     RECT  109.397 176.448 110.408 176.472 ;
     RECT  108.937 178.128 110.408 178.152 ;
     RECT  109.969 179.904 110.408 182.952 ;
     RECT  108.785 184.128 110.408 184.152 ;
     RECT  110.053 185.52 110.408 187.464 ;
     RECT  109.331 190.512 110.408 191.928 ;
     RECT  109.253 193.488 110.408 193.512 ;
     RECT  109.393 194.592 110.408 194.616 ;
     RECT  110.408 2.148 110.512 369.372 ;
     RECT  110.512 2.418 110.704 369.102 ;
     RECT  110.704 171.504 110.729 174.216 ;
     RECT  110.704 176.352 110.729 177.816 ;
     RECT  110.704 159.648 110.765 161.352 ;
     RECT  110.704 162.432 110.765 164.232 ;
     RECT  110.704 165.696 110.819 167.592 ;
     RECT  110.729 171.504 110.873 171.528 ;
     RECT  110.819 167.04 111.017 167.592 ;
     RECT  110.704 182.064 111.197 182.76 ;
     RECT  110.704 178.8 111.203 180.84 ;
     RECT  110.704 194.592 111.377 194.616 ;
     RECT  110.704 185.136 111.395 185.832 ;
     RECT  110.704 189.216 111.395 191.544 ;
     RECT  110.765 159.648 111.413 161.256 ;
     RECT  110.819 165.696 111.413 165.864 ;
     RECT  111.395 190.656 111.521 191.544 ;
     RECT  110.729 176.352 111.539 176.376 ;
     RECT  110.704 187.248 111.685 187.992 ;
     RECT  111.395 189.216 111.685 189.24 ;
     RECT  110.704 184.08 111.697 184.104 ;
     RECT  111.395 185.808 111.733 185.832 ;
     RECT  111.685 187.248 111.733 189.24 ;
     RECT  111.733 185.808 111.737 189.24 ;
     RECT  111.737 185.808 111.779 188.472 ;
     RECT  111.697 184.08 111.881 184.488 ;
     RECT  110.704 169.344 112.021 169.368 ;
     RECT  112.021 168.816 112.093 169.368 ;
     RECT  110.704 192.624 112.117 192.648 ;
     RECT  111.017 167.04 112.124 167.064 ;
     RECT  112.117 192.624 112.163 193.368 ;
     RECT  110.765 163.008 112.165 164.232 ;
     RECT  112.124 167.04 112.165 167.4 ;
     RECT  112.093 168.816 112.165 170.424 ;
     RECT  111.881 184.464 112.169 184.488 ;
     RECT  112.163 193.344 112.204 193.368 ;
     RECT  112.165 166.944 112.211 170.424 ;
     RECT  110.729 172.656 112.273 174.216 ;
     RECT  111.779 186.384 112.277 188.472 ;
     RECT  112.277 186.432 112.307 188.472 ;
     RECT  110.729 177.456 112.313 177.816 ;
     RECT  112.211 168 112.349 170.424 ;
     RECT  111.197 182.064 112.381 182.088 ;
     RECT  111.203 180.144 112.417 180.84 ;
     RECT  112.381 182.064 112.417 182.184 ;
     RECT  111.413 160.848 112.453 161.256 ;
     RECT  111.413 165.84 112.493 165.864 ;
     RECT  112.453 160.752 112.529 161.256 ;
     RECT  112.417 180.144 112.549 182.184 ;
     RECT  112.165 162.384 112.601 164.232 ;
     RECT  112.349 169.632 112.601 170.424 ;
     RECT  112.273 172.656 112.601 174.84 ;
     RECT  112.345 191.952 112.601 191.976 ;
     RECT  112.601 162.384 112.637 163.608 ;
     RECT  111.521 190.656 112.741 190.68 ;
     RECT  112.549 180.144 112.745 183.144 ;
     RECT  112.211 166.944 112.777 166.968 ;
     RECT  112.237 176.016 112.781 176.136 ;
     RECT  111.203 178.8 112.813 178.824 ;
     RECT  112.777 165.984 112.817 166.968 ;
     RECT  112.781 176.112 112.921 176.136 ;
     RECT  112.345 177.12 112.921 177.144 ;
     RECT  112.741 190.464 112.997 190.68 ;
     RECT  112.921 176.112 113.033 177.144 ;
     RECT  112.817 165.984 113.069 166.008 ;
     RECT  112.745 180.144 113.269 182.088 ;
     RECT  112.349 168 113.317 168.024 ;
     RECT  112.745 183.12 113.317 183.144 ;
     RECT  113.209 193.488 113.353 193.512 ;
     RECT  113.317 167.136 113.357 168.024 ;
     RECT  113.317 183.12 113.357 183.432 ;
     RECT  112.601 170.4 113.413 170.424 ;
     RECT  111.413 159.648 113.425 159.672 ;
     RECT  112.529 160.752 113.425 161.064 ;
     RECT  112.307 188.064 113.425 188.472 ;
     RECT  113.425 159.648 113.429 161.064 ;
     RECT  113.413 170.4 113.459 171.384 ;
     RECT  113.429 159.648 113.533 159.912 ;
     RECT  112.601 172.656 113.533 172.968 ;
     RECT  113.605 185.232 113.677 185.256 ;
     RECT  112.601 174.432 113.681 174.84 ;
     RECT  112.637 163.008 113.749 163.608 ;
     RECT  113.269 180.048 113.861 182.088 ;
     RECT  113.353 192.624 113.929 193.512 ;
     RECT  113.681 174.816 113.933 174.84 ;
     RECT  113.677 184.608 113.941 185.256 ;
     RECT  112.307 186.432 113.941 186.456 ;
     RECT  113.749 163.008 113.969 163.992 ;
     RECT  113.357 167.136 113.987 167.592 ;
     RECT  113.533 172.512 113.987 172.968 ;
     RECT  113.533 159.552 114.005 159.912 ;
     RECT  113.033 177.12 114.005 177.144 ;
     RECT  113.929 192 114.005 193.512 ;
     RECT  113.861 181.584 114.037 182.088 ;
     RECT  113.941 184.608 114.149 186.456 ;
     RECT  113.425 187.584 114.181 188.472 ;
     RECT  114.005 159.552 114.185 159.768 ;
     RECT  113.857 175.968 114.217 175.992 ;
     RECT  113.969 163.968 114.289 163.992 ;
     RECT  113.605 165.168 114.289 165.192 ;
     RECT  112.997 190.464 114.397 190.488 ;
     RECT  114.289 163.968 114.401 165.192 ;
     RECT  113.861 180.048 114.469 180.168 ;
     RECT  113.429 161.04 114.473 161.064 ;
     RECT  113.987 167.568 114.515 167.592 ;
     RECT  114.185 159.552 114.545 159.576 ;
     RECT  114.401 163.968 114.545 164.76 ;
     RECT  114.469 168.576 114.556 169.08 ;
     RECT  114.181 187.584 114.565 188.568 ;
     RECT  114.005 192 114.565 192.024 ;
     RECT  114.505 160.752 114.617 160.776 ;
     RECT  113.459 171.36 114.617 171.384 ;
     RECT  113.987 172.512 114.617 172.68 ;
     RECT  114.217 175.968 114.653 176.136 ;
     RECT  112.813 178.656 114.685 178.824 ;
     RECT  114.469 179.952 114.685 180.168 ;
     RECT  114.617 172.656 114.689 172.68 ;
     RECT  114.037 181.584 114.761 182.184 ;
     RECT  114.565 191.712 115.045 192.024 ;
     RECT  115.045 191.712 115.093 192.072 ;
     RECT  114.005 193.488 115.093 193.512 ;
     RECT  114.685 178.656 115.117 180.168 ;
     RECT  113.357 183.408 115.117 183.432 ;
     RECT  114.149 184.608 115.117 185.448 ;
     RECT  115.117 183.408 115.153 185.448 ;
     RECT  114.541 165.888 115.261 165.912 ;
     RECT  115.117 178.08 115.261 180.168 ;
     RECT  113.941 170.256 115.441 170.28 ;
     RECT  114.565 186.672 115.541 188.568 ;
     RECT  115.541 186.672 115.573 188.712 ;
     RECT  114.761 181.584 115.585 181.8 ;
     RECT  114.973 173.136 115.801 173.16 ;
     RECT  114.541 162.432 115.808 162.456 ;
     RECT  114.545 163.968 115.808 163.992 ;
     RECT  115.261 165.888 115.808 166.776 ;
     RECT  114.556 168.576 115.808 168.6 ;
     RECT  115.441 170.256 115.808 170.472 ;
     RECT  115.117 171.6 115.808 171.624 ;
     RECT  115.801 173.136 115.808 173.448 ;
     RECT  115.333 175.68 115.808 175.704 ;
     RECT  115.261 177.216 115.808 180.168 ;
     RECT  115.585 181.296 115.808 181.8 ;
     RECT  115.153 182.832 115.808 185.448 ;
     RECT  115.573 186.672 115.808 189.384 ;
     RECT  114.397 190.464 115.808 190.536 ;
     RECT  115.093 191.712 115.808 193.512 ;
     RECT  115.808 2.148 115.912 369.372 ;
     RECT  115.912 2.418 116.104 369.102 ;
     RECT  116.104 181.296 116.237 181.656 ;
     RECT  116.104 173.136 116.273 173.448 ;
     RECT  116.104 190.368 116.273 190.536 ;
     RECT  116.104 172.128 116.309 172.152 ;
     RECT  116.104 183.408 116.309 183.432 ;
     RECT  116.237 181.296 116.453 181.32 ;
     RECT  116.104 177.744 116.525 177.768 ;
     RECT  116.104 174.576 116.771 174.6 ;
     RECT  116.104 175.68 116.771 176.184 ;
     RECT  116.104 184.752 116.813 184.776 ;
     RECT  116.104 188.496 116.813 189.384 ;
     RECT  116.273 190.368 116.813 190.392 ;
     RECT  116.104 185.904 116.921 186.696 ;
     RECT  116.921 186.672 117.029 186.696 ;
     RECT  116.771 176.16 117.353 176.184 ;
     RECT  117.349 183.312 117.673 183.336 ;
     RECT  116.273 173.136 117.785 173.16 ;
     RECT  116.104 179.856 117.889 180.216 ;
     RECT  117.889 179.856 118.141 180.504 ;
     RECT  117.673 183.312 118.165 183.48 ;
     RECT  118.141 179.856 118.225 180.696 ;
     RECT  118.165 182.304 118.285 183.48 ;
     RECT  118.285 182.112 118.361 183.48 ;
     RECT  118.361 183.216 118.433 183.48 ;
     RECT  116.813 188.496 118.573 188.52 ;
     RECT  118.573 188.496 118.613 188.664 ;
     RECT  118.433 183.312 118.685 183.48 ;
     RECT  118.685 183.36 118.789 183.48 ;
     RECT  118.225 179.856 118.901 180.504 ;
     RECT  118.361 182.112 119.225 182.136 ;
     RECT  118.177 178.272 119.365 178.296 ;
     RECT  118.789 183.36 119.369 183.528 ;
     RECT  119.293 174.336 119.411 174.36 ;
     RECT  119.365 177.84 119.657 178.296 ;
     RECT  119.369 183.408 119.797 183.528 ;
     RECT  119.797 183.408 119.881 184.104 ;
     RECT  116.104 170.256 119.905 170.28 ;
     RECT  118.901 179.856 119.941 180.168 ;
     RECT  119.941 179.856 120.661 180.744 ;
     RECT  119.657 177.84 120.841 177.864 ;
     RECT  120.841 177.84 120.877 178.44 ;
     RECT  119.905 170.208 121.208 170.28 ;
     RECT  120.841 172.704 121.208 172.728 ;
     RECT  120.877 177.216 121.208 178.44 ;
     RECT  120.661 179.856 121.208 180.792 ;
     RECT  120.301 181.776 121.208 181.8 ;
     RECT  119.881 183.408 121.208 183.576 ;
     RECT  117.169 185.328 121.208 185.352 ;
     RECT  118.613 188.64 121.208 188.664 ;
     RECT  121.208 2.148 121.312 369.372 ;
     RECT  121.312 2.418 121.504 369.102 ;
     RECT  121.504 185.328 121.601 185.448 ;
     RECT  121.504 177.216 121.673 177.24 ;
     RECT  121.504 178.368 122.429 178.872 ;
     RECT  121.504 169.776 122.497 171 ;
     RECT  121.504 179.952 122.497 182.328 ;
     RECT  122.429 178.368 122.533 178.392 ;
     RECT  121.504 183.504 122.537 183.528 ;
     RECT  121.504 172.704 122.713 172.728 ;
     RECT  121.504 160.704 122.78 160.728 ;
     RECT  122.533 162.816 122.821 162.84 ;
     RECT  122.78 160.704 122.867 161.016 ;
     RECT  122.821 162.72 122.929 163.032 ;
     RECT  122.497 169.152 123.02 171 ;
     RECT  122.821 164.688 123.107 164.712 ;
     RECT  122.821 167.184 123.107 167.208 ;
     RECT  123.02 168.624 123.107 171 ;
     RECT  122.497 179.856 123.113 182.328 ;
     RECT  122.929 162.48 123.181 163.032 ;
     RECT  123.061 165.936 123.185 165.96 ;
     RECT  123.113 181.392 123.257 182.328 ;
     RECT  123.181 162.48 123.293 163.224 ;
     RECT  123.107 168.672 123.325 171 ;
     RECT  123.293 162.48 123.365 163.032 ;
     RECT  123.325 168.672 123.452 171.048 ;
     RECT  122.713 172.128 123.452 172.728 ;
     RECT  123.257 181.68 123.491 182.328 ;
     RECT  123.452 168.672 123.539 172.728 ;
     RECT  122.821 158.976 123.545 159 ;
     RECT  121.504 188.64 123.596 188.664 ;
     RECT  123.539 172.56 123.653 172.728 ;
     RECT  122.533 177.792 123.725 178.392 ;
     RECT  121.601 185.424 123.725 185.448 ;
     RECT  123.491 182.304 123.761 182.328 ;
     RECT  123.596 188.64 123.973 189 ;
     RECT  123.973 187.488 124.019 189 ;
     RECT  123.649 167.088 124.049 167.112 ;
     RECT  123.113 179.856 124.081 179.88 ;
     RECT  123.937 174.336 124.161 174.36 ;
     RECT  124.019 187.488 124.193 188.136 ;
     RECT  124.161 174.336 124.213 174.984 ;
     RECT  124.045 176.688 124.259 176.712 ;
     RECT  124.153 186.384 124.259 186.408 ;
     RECT  124.213 174.336 124.3 175.368 ;
     RECT  124.213 184.656 124.3 185.4 ;
     RECT  124.3 174.336 124.32 174.984 ;
     RECT  123.539 168.672 124.409 171.576 ;
     RECT  124.409 169.2 124.445 171.576 ;
     RECT  124.445 169.2 124.451 170.328 ;
     RECT  124.193 188.112 124.481 188.136 ;
     RECT  123.637 190.416 124.585 190.44 ;
     RECT  123.365 162.72 124.625 163.032 ;
     RECT  124.153 164.736 124.729 164.76 ;
     RECT  123.973 196.32 124.741 196.344 ;
     RECT  124.721 198.384 124.805 198.408 ;
     RECT  124.741 196.32 124.828 197.256 ;
     RECT  123.725 177.888 124.877 178.392 ;
     RECT  124.828 196.32 124.877 196.344 ;
     RECT  124.549 193.2 124.909 193.224 ;
     RECT  124.625 162.816 124.913 163.032 ;
     RECT  124.32 174.432 124.913 174.984 ;
     RECT  124.729 181.632 124.945 181.656 ;
     RECT  124.913 163.008 124.949 163.032 ;
     RECT  124.909 193.2 124.949 193.464 ;
     RECT  124.729 164.112 124.985 165.048 ;
     RECT  124.451 169.2 124.985 169.224 ;
     RECT  124.877 177.888 125.183 178.344 ;
     RECT  124.081 179.424 125.221 179.88 ;
     RECT  123.653 172.56 125.233 172.584 ;
     RECT  124.945 181.632 125.273 181.992 ;
     RECT  124.445 171.552 125.341 171.576 ;
     RECT  125.233 172.56 125.341 172.728 ;
     RECT  125.341 171.552 125.377 172.728 ;
     RECT  125.183 177.84 125.377 178.344 ;
     RECT  124.585 190.416 125.413 191.064 ;
     RECT  124.213 166.08 125.449 166.104 ;
     RECT  124.729 203.472 125.453 203.496 ;
     RECT  124.765 194.928 125.485 194.952 ;
     RECT  125.413 190.32 125.521 191.064 ;
     RECT  125.377 171.552 125.585 173.304 ;
     RECT  124.913 174.432 125.585 174.456 ;
     RECT  125.413 200.016 125.605 200.04 ;
     RECT  124.3 184.656 125.653 184.68 ;
     RECT  125.593 175.728 125.66 175.752 ;
     RECT  125.485 185.856 125.737 185.88 ;
     RECT  125.485 194.688 125.737 194.952 ;
     RECT  125.449 166.08 125.756 166.488 ;
     RECT  125.756 166.08 125.797 166.776 ;
     RECT  125.653 183.504 125.804 184.68 ;
     RECT  125.737 185.856 125.804 186.36 ;
     RECT  125.221 179.424 125.845 180.456 ;
     RECT  125.273 181.632 125.845 181.656 ;
     RECT  125.804 183.504 125.845 186.36 ;
     RECT  125.029 204.96 125.845 204.984 ;
     RECT  124.451 170.304 125.881 170.328 ;
     RECT  125.845 183.504 125.881 187.176 ;
     RECT  125.66 175.728 125.989 176.52 ;
     RECT  125.377 177.552 125.989 178.344 ;
     RECT  124.949 193.44 126.044 193.464 ;
     RECT  125.737 194.688 126.044 195.048 ;
     RECT  126.044 193.44 126.085 195.048 ;
     RECT  126.025 161.52 126.133 161.544 ;
     RECT  124.985 165.024 126.313 165.048 ;
     RECT  125.797 166.08 126.313 167.64 ;
     RECT  126.085 193.44 126.349 195.576 ;
     RECT  125.881 183.504 126.385 187.56 ;
     RECT  126.133 210.384 126.385 210.408 ;
     RECT  125.701 163.536 126.457 163.56 ;
     RECT  125.989 175.728 126.457 178.344 ;
     RECT  125.845 179.424 126.457 181.656 ;
     RECT  126.349 193.104 126.469 195.576 ;
     RECT  125.449 198.912 126.529 198.936 ;
     RECT  125.845 204.96 126.529 205.224 ;
     RECT  126.385 183.504 126.565 188.136 ;
     RECT  124.441 189.168 126.565 189.192 ;
     RECT  126.529 204.96 126.565 206.088 ;
     RECT  126.133 161.088 126.608 161.544 ;
     RECT  126.457 162.864 126.608 163.56 ;
     RECT  126.313 164.832 126.608 165.048 ;
     RECT  126.313 166.08 126.608 168.6 ;
     RECT  125.881 169.584 126.608 170.328 ;
     RECT  125.585 171.552 126.608 174.456 ;
     RECT  126.457 175.728 126.608 181.656 ;
     RECT  126.565 183.504 126.608 189.192 ;
     RECT  125.521 190.272 126.608 191.064 ;
     RECT  126.469 192.576 126.608 195.576 ;
     RECT  125.845 196.704 126.608 196.728 ;
     RECT  126.529 198.096 126.608 198.936 ;
     RECT  125.605 200.016 126.608 200.712 ;
     RECT  125.305 201.744 126.608 201.768 ;
     RECT  126.565 204.72 126.608 206.088 ;
     RECT  126.092 208.896 126.608 208.92 ;
     RECT  126.385 210.384 126.608 211.272 ;
     RECT  126.608 2.148 126.712 369.372 ;
     RECT  126.712 2.418 126.904 369.102 ;
     RECT  126.904 163.008 126.929 174.312 ;
     RECT  126.904 176.736 126.965 184.248 ;
     RECT  126.904 192.576 127.037 195.048 ;
     RECT  126.904 175.44 127.043 175.464 ;
     RECT  126.904 201.744 127.043 204.744 ;
     RECT  126.904 196.32 127.139 199.512 ;
     RECT  127.139 196.32 127.217 197.352 ;
     RECT  126.929 163.008 127.235 173.88 ;
     RECT  126.904 190.896 127.289 191.544 ;
     RECT  126.904 205.968 127.289 207.096 ;
     RECT  127.289 207.024 127.331 207.096 ;
     RECT  127.139 198.96 127.505 199.512 ;
     RECT  127.235 166.896 127.613 173.88 ;
     RECT  127.043 202.128 127.715 204.744 ;
     RECT  126.965 176.736 127.757 182.568 ;
     RECT  127.037 193.44 127.757 195.048 ;
     RECT  127.715 202.128 127.829 202.344 ;
     RECT  126.904 209.904 127.852 209.928 ;
     RECT  127.829 202.128 127.901 202.152 ;
     RECT  126.904 188.64 127.933 188.664 ;
     RECT  126.904 210.96 127.973 211.896 ;
     RECT  127.613 173.856 128.003 173.88 ;
     RECT  127.505 199.488 128.005 199.512 ;
     RECT  126.904 187.2 128.009 187.224 ;
     RECT  127.613 166.896 128.044 172.728 ;
     RECT  127.289 205.968 128.045 205.992 ;
     RECT  127.757 177.552 128.077 182.568 ;
     RECT  128.005 199.488 128.077 200.088 ;
     RECT  127.757 194.16 128.113 195.048 ;
     RECT  127.715 203.328 128.117 204.744 ;
     RECT  127.933 188.64 128.149 189.24 ;
     RECT  126.965 183.936 128.185 184.248 ;
     RECT  126.904 185.376 128.185 185.592 ;
     RECT  126.904 160.128 128.197 161.544 ;
     RECT  127.235 163.008 128.197 165.912 ;
     RECT  128.149 188.64 128.293 189.672 ;
     RECT  128.077 199.488 128.297 200.904 ;
     RECT  128.044 166.896 128.339 170.328 ;
     RECT  127.289 190.896 128.365 191.496 ;
     RECT  128.293 187.536 128.369 189.672 ;
     RECT  128.185 183.936 128.405 185.592 ;
     RECT  127.973 211.872 128.473 211.896 ;
     RECT  128.197 160.128 128.477 165.912 ;
     RECT  128.365 190.896 128.513 191.928 ;
     RECT  128.477 163.152 128.545 165.912 ;
     RECT  128.339 166.896 128.545 167.064 ;
     RECT  128.297 199.488 128.621 200.664 ;
     RECT  127.217 196.32 128.653 196.344 ;
     RECT  127.217 197.328 128.657 197.352 ;
     RECT  128.473 211.872 128.723 212.616 ;
     RECT  127.969 158.976 128.732 159 ;
     RECT  128.077 177.552 128.761 182.76 ;
     RECT  128.405 183.936 128.761 184.584 ;
     RECT  128.117 204.192 128.773 204.744 ;
     RECT  128.689 213.696 128.773 213.72 ;
     RECT  128.761 177.552 128.801 184.584 ;
     RECT  128.369 187.536 128.801 187.848 ;
     RECT  128.677 217.776 128.801 217.8 ;
     RECT  128.732 158.976 128.819 159.144 ;
     RECT  128.773 204.192 128.819 205.368 ;
     RECT  128.723 212.592 128.819 212.616 ;
     RECT  128.773 213.696 128.819 214.344 ;
     RECT  128.801 177.552 128.833 183.96 ;
     RECT  128.833 177.456 128.873 183.96 ;
     RECT  128.473 192.96 128.909 192.984 ;
     RECT  128.653 196.128 128.909 196.344 ;
     RECT  128.819 205.344 128.909 205.368 ;
     RECT  128.909 196.224 128.953 196.344 ;
     RECT  128.545 163.152 128.981 167.064 ;
     RECT  128.113 194.16 129.011 195.144 ;
     RECT  128.873 179.376 129.017 183.96 ;
     RECT  128.953 196.32 129.017 196.344 ;
     RECT  128.965 193.152 129.052 193.176 ;
     RECT  128.477 160.128 129.053 161.544 ;
     RECT  129.017 179.424 129.053 183.96 ;
     RECT  129.011 195.12 129.053 195.144 ;
     RECT  127.331 207.072 129.061 207.096 ;
     RECT  129.061 207.072 129.107 207.768 ;
     RECT  128.621 200.64 129.125 200.664 ;
     RECT  129.107 207.744 129.148 207.768 ;
     RECT  128.044 171.6 129.157 172.728 ;
     RECT  128.339 168.048 129.193 170.328 ;
     RECT  128.689 197.76 129.205 197.784 ;
     RECT  128.621 199.488 129.205 199.656 ;
     RECT  128.617 153.168 129.229 153.192 ;
     RECT  128.981 163.536 129.269 167.064 ;
     RECT  129.157 171.6 129.269 173.304 ;
     RECT  129.205 197.76 129.292 199.656 ;
     RECT  129.193 168.048 129.299 170.424 ;
     RECT  129.269 171.6 129.337 172.728 ;
     RECT  128.801 187.824 129.337 187.848 ;
     RECT  128.369 189.216 129.337 189.672 ;
     RECT  129.337 187.824 129.377 189.672 ;
     RECT  129.269 166.896 129.395 167.064 ;
     RECT  129.292 197.76 129.413 198.024 ;
     RECT  129.292 199.584 129.413 199.656 ;
     RECT  129.269 163.536 129.421 165.912 ;
     RECT  129.404 186.72 129.445 186.744 ;
     RECT  129.053 179.424 129.521 182.568 ;
     RECT  129.053 183.6 129.593 183.96 ;
     RECT  128.689 202.08 129.593 202.104 ;
     RECT  129.445 176.4 129.625 176.424 ;
     RECT  129.421 164.112 129.665 165.912 ;
     RECT  128.819 214.32 129.697 214.344 ;
     RECT  129.661 202.272 129.733 202.296 ;
     RECT  129.445 174.576 129.773 174.6 ;
     RECT  129.625 176.112 129.809 176.424 ;
     RECT  129.229 153.072 129.841 153.192 ;
     RECT  126.904 208.896 129.841 208.92 ;
     RECT  129.053 160.128 129.973 160.728 ;
     RECT  129.841 153.024 129.989 153.192 ;
     RECT  129.409 157.344 129.989 157.368 ;
     RECT  129.697 214.32 129.989 214.536 ;
     RECT  129.769 158.4 130.019 158.424 ;
     RECT  129.299 168.048 130.025 170.04 ;
     RECT  129.589 206.352 130.028 206.76 ;
     RECT  129.445 186.624 130.057 186.744 ;
     RECT  129.377 187.824 130.057 189.24 ;
     RECT  129.733 193.488 130.057 193.512 ;
     RECT  129.665 164.304 130.061 165.912 ;
     RECT  130.057 186.624 130.061 189.24 ;
     RECT  129.553 220.032 130.069 220.056 ;
     RECT  130.069 220.032 130.115 220.968 ;
     RECT  129.841 208.896 130.129 208.968 ;
     RECT  130.061 188.304 130.133 189.24 ;
     RECT  130.115 220.56 130.156 220.968 ;
     RECT  128.405 185.568 130.165 185.592 ;
     RECT  130.028 206.304 130.201 206.76 ;
     RECT  130.165 185.232 130.205 185.592 ;
     RECT  130.061 186.624 130.237 186.936 ;
     RECT  130.061 164.304 130.241 165.336 ;
     RECT  129.989 153.168 130.273 153.192 ;
     RECT  129.395 167.04 130.309 167.064 ;
     RECT  128.873 177.456 130.309 178.296 ;
     RECT  128.513 191.328 130.309 191.928 ;
     RECT  130.057 193.392 130.309 193.512 ;
     RECT  129.877 217.392 130.309 217.416 ;
     RECT  128.819 204.192 130.345 204.216 ;
     RECT  130.309 167.04 130.349 167.496 ;
     RECT  130.309 217.392 130.457 217.512 ;
     RECT  130.201 206.304 130.525 206.904 ;
     RECT  130.129 208.752 130.525 208.968 ;
     RECT  130.309 191.328 130.541 193.512 ;
     RECT  130.345 151.584 130.547 152.184 ;
     RECT  130.525 205.776 130.549 207.48 ;
     RECT  130.525 208.752 130.549 209.16 ;
     RECT  130.549 205.776 130.565 209.16 ;
     RECT  130.309 212.016 130.597 212.04 ;
     RECT  130.309 219.552 130.601 219.576 ;
     RECT  129.989 214.32 130.604 214.344 ;
     RECT  130.565 207.456 130.609 209.16 ;
     RECT  129.521 179.424 130.669 179.448 ;
     RECT  130.309 177.312 130.705 178.296 ;
     RECT  130.669 179.424 130.705 179.64 ;
     RECT  130.541 191.28 130.705 193.512 ;
     RECT  130.349 167.424 130.739 167.496 ;
     RECT  130.565 205.776 130.745 205.944 ;
     RECT  130.165 163.008 130.777 163.032 ;
     RECT  130.237 186.288 130.781 186.936 ;
     RECT  130.745 205.92 130.781 205.944 ;
     RECT  130.025 168.672 130.787 170.04 ;
     RECT  130.597 212.016 130.813 212.568 ;
     RECT  130.777 163.008 130.817 163.416 ;
     RECT  129.593 183.6 130.817 183.768 ;
     RECT  130.781 186.288 130.817 186.888 ;
     RECT  130.609 208.032 130.817 209.16 ;
     RECT  129.809 176.112 130.885 176.136 ;
     RECT  130.705 177.312 130.885 179.64 ;
     RECT  130.705 191.28 130.885 193.56 ;
     RECT  130.817 183.6 130.889 183.624 ;
     RECT  129.337 171.264 130.957 172.728 ;
     RECT  130.817 186.528 130.961 186.888 ;
     RECT  129.301 196.368 130.961 196.392 ;
     RECT  130.817 208.032 130.979 208.968 ;
     RECT  130.273 153.168 131.029 153.528 ;
     RECT  129.085 155.184 131.029 155.208 ;
     RECT  130.241 165.12 131.029 165.336 ;
     RECT  130.604 214.08 131.065 214.344 ;
     RECT  129.521 181.632 131.101 182.568 ;
     RECT  131.101 180.768 131.125 182.568 ;
     RECT  131.029 153.168 131.137 155.208 ;
     RECT  129.413 198 131.137 198.024 ;
     RECT  129.973 159.504 131.173 160.728 ;
     RECT  130.885 176.112 131.173 179.64 ;
     RECT  131.125 180.768 131.173 183.576 ;
     RECT  130.957 171.264 131.209 172.776 ;
     RECT  129.733 202.272 131.209 202.344 ;
     RECT  130.813 211.056 131.221 212.568 ;
     RECT  131.065 213.84 131.221 214.344 ;
     RECT  131.173 159.504 131.317 160.824 ;
     RECT  131.209 171.264 131.317 173.688 ;
     RECT  131.209 202.272 131.353 203.208 ;
     RECT  130.156 220.56 131.353 220.728 ;
     RECT  130.133 188.352 131.425 189.24 ;
     RECT  131.221 211.056 131.461 214.344 ;
     RECT  129.413 199.584 131.468 199.608 ;
     RECT  130.777 148.656 131.497 148.68 ;
     RECT  130.777 149.904 131.497 149.928 ;
     RECT  130.633 217.728 131.497 217.8 ;
     RECT  131.497 217.152 131.509 217.8 ;
     RECT  130.885 191.28 131.605 193.752 ;
     RECT  131.353 201.744 131.605 203.208 ;
     RECT  131.209 146.064 131.633 146.088 ;
     RECT  131.317 171.264 131.641 173.784 ;
     RECT  131.173 176.112 131.641 183.576 ;
     RECT  131.533 196.416 131.641 196.44 ;
     RECT  131.461 211.056 131.641 214.584 ;
     RECT  131.633 145.296 131.677 146.088 ;
     RECT  130.739 167.424 131.677 167.448 ;
     RECT  131.605 201.504 131.701 203.208 ;
     RECT  130.345 204.192 131.701 204.312 ;
     RECT  131.641 196.416 131.713 196.68 ;
     RECT  131.137 198 131.713 198.36 ;
     RECT  131.713 196.416 131.785 198.36 ;
     RECT  131.137 221.76 131.785 221.784 ;
     RECT  130.645 223.2 131.785 223.224 ;
     RECT  131.353 220.464 131.797 220.728 ;
     RECT  131.701 201.504 131.821 204.312 ;
     RECT  129.985 194.88 131.852 194.904 ;
     RECT  131.797 225.12 131.857 225.144 ;
     RECT  131.653 161.904 131.893 161.928 ;
     RECT  130.817 163.392 131.893 163.416 ;
     RECT  131.605 190.416 131.893 193.752 ;
     RECT  131.852 194.88 131.893 195.144 ;
     RECT  130.979 208.032 131.893 208.68 ;
     RECT  131.641 211.056 131.893 215.016 ;
     RECT  130.129 157.248 131.929 157.272 ;
     RECT  131.893 206.112 131.965 206.136 ;
     RECT  131.677 144.816 132.008 146.088 ;
     RECT  131.653 147.072 132.008 147.096 ;
     RECT  131.497 148.656 132.008 149.928 ;
     RECT  130.547 151.584 132.008 151.608 ;
     RECT  131.137 152.736 132.008 155.208 ;
     RECT  131.929 157.248 132.008 158.136 ;
     RECT  131.317 159.216 132.008 160.824 ;
     RECT  131.893 161.904 132.008 163.8 ;
     RECT  131.029 165.12 132.008 165.96 ;
     RECT  131.677 166.992 132.008 167.448 ;
     RECT  130.787 168.672 132.008 168.792 ;
     RECT  130.787 169.968 132.008 170.04 ;
     RECT  131.641 171.264 132.008 183.576 ;
     RECT  130.205 185.232 132.008 185.256 ;
     RECT  130.961 186.528 132.008 186.648 ;
     RECT  131.425 188.064 132.008 189.24 ;
     RECT  131.893 190.416 132.008 195.144 ;
     RECT  131.785 196.416 132.008 198.6 ;
     RECT  131.468 199.584 132.008 200.328 ;
     RECT  131.821 201.504 132.008 205.032 ;
     RECT  131.965 206.112 132.008 206.472 ;
     RECT  131.893 207.504 132.008 208.68 ;
     RECT  131.893 210.336 132.008 215.016 ;
     RECT  131.509 217.152 132.008 218.28 ;
     RECT  131.797 219.696 132.008 220.728 ;
     RECT  131.785 221.76 132.008 223.224 ;
     RECT  131.857 224.736 132.008 225.144 ;
     RECT  131.756 226.416 132.008 226.44 ;
     RECT  131.797 227.424 132.008 227.448 ;
     RECT  132.008 2.148 132.112 369.372 ;
     RECT  132.133 370.464 132.145 370.488 ;
     RECT  132.145 370.464 132.229 370.536 ;
     RECT  132.112 2.418 132.304 369.102 ;
     RECT  132.304 205.776 132.329 206.472 ;
     RECT  132.304 211.488 132.365 214.488 ;
     RECT  132.304 158.112 132.401 160.2 ;
     RECT  132.304 135.984 132.419 136.296 ;
     RECT  132.229 370.464 132.421 371.208 ;
     RECT  132.304 197.52 132.437 198.36 ;
     RECT  132.304 222.912 132.437 223.608 ;
     RECT  132.401 158.112 132.473 159.24 ;
     RECT  132.304 218.208 132.509 218.328 ;
     RECT  132.304 169.92 132.515 188.088 ;
     RECT  132.304 257.04 132.563 257.064 ;
     RECT  132.421 370.464 132.563 371.304 ;
     RECT  132.304 190.128 132.617 193.512 ;
     RECT  132.304 220.464 132.617 220.584 ;
     RECT  132.304 221.76 132.617 221.784 ;
     RECT  132.304 137.856 132.659 137.88 ;
     RECT  132.304 138.864 132.659 139.704 ;
     RECT  132.304 142.032 132.659 142.296 ;
     RECT  132.563 370.464 132.725 370.488 ;
     RECT  132.515 169.92 132.761 175.416 ;
     RECT  132.761 169.92 132.797 174.936 ;
     RECT  132.365 211.488 132.797 213.096 ;
     RECT  132.437 223.584 132.797 223.608 ;
     RECT  132.797 169.92 132.799 174.84 ;
     RECT  132.797 211.488 132.805 211.608 ;
     RECT  132.304 147.648 132.833 147.672 ;
     RECT  132.304 207.504 132.833 208.104 ;
     RECT  132.304 272.976 132.833 273 ;
     RECT  132.515 176.448 132.897 188.088 ;
     RECT  132.304 200.88 132.905 203.256 ;
     RECT  132.304 216.96 132.941 217.176 ;
     RECT  132.304 156.72 133.013 156.744 ;
     RECT  132.304 166.992 133.013 167.016 ;
     RECT  132.805 211.584 133.013 211.608 ;
     RECT  132.304 227.424 133.013 227.448 ;
     RECT  132.419 135.984 133.049 136.008 ;
     RECT  132.304 148.656 133.049 148.68 ;
     RECT  132.304 143.952 133.085 144.84 ;
     RECT  132.617 220.56 133.121 220.584 ;
     RECT  132.304 161.808 133.229 162.648 ;
     RECT  132.905 201.168 133.229 203.256 ;
     RECT  132.941 217.152 133.229 217.176 ;
     RECT  132.659 142.032 133.235 142.056 ;
     RECT  132.304 224.736 133.265 224.76 ;
     RECT  132.304 140.736 133.273 140.76 ;
     RECT  132.304 151.584 133.297 151.608 ;
     RECT  132.304 168.096 133.297 168.168 ;
     RECT  132.304 195.36 133.333 196.488 ;
     RECT  132.659 139.68 133.337 139.704 ;
     RECT  132.473 158.112 133.373 159.096 ;
     RECT  132.437 197.808 133.405 198.36 ;
     RECT  132.304 154.32 133.409 155.496 ;
     RECT  133.333 272.448 133.417 272.472 ;
     RECT  132.304 163.776 133.441 165.432 ;
     RECT  133.333 195.36 133.441 196.536 ;
     RECT  133.405 197.808 133.441 199.08 ;
     RECT  133.441 195.312 133.477 196.536 ;
     RECT  133.441 197.808 133.477 200.04 ;
     RECT  133.373 158.112 133.549 158.664 ;
     RECT  133.297 151.008 133.58 151.608 ;
     RECT  132.365 214.464 133.58 214.488 ;
     RECT  133.58 151.008 133.621 152.136 ;
     RECT  132.329 205.776 133.621 205.8 ;
     RECT  133.58 214.464 133.621 215.304 ;
     RECT  132.833 207.504 133.657 207.768 ;
     RECT  133.621 151.008 133.667 152.76 ;
     RECT  133.621 214.464 133.667 215.688 ;
     RECT  133.477 194.88 133.693 196.536 ;
     RECT  133.477 197.52 133.693 200.04 ;
     RECT  133.229 202.08 133.697 203.256 ;
     RECT  133.513 227.376 133.715 227.4 ;
     RECT  132.617 190.128 133.729 193.032 ;
     RECT  133.667 151.008 133.763 151.608 ;
     RECT  133.333 145.872 133.765 145.896 ;
     RECT  132.897 176.448 133.769 187.176 ;
     RECT  133.085 143.952 133.801 144.6 ;
     RECT  133.693 160.56 133.801 160.584 ;
     RECT  132.509 218.208 133.801 218.232 ;
     RECT  133.297 167.856 133.805 168.312 ;
     RECT  133.409 154.32 133.841 154.344 ;
     RECT  133.667 214.464 133.841 214.488 ;
     RECT  133.765 145.872 133.859 146.28 ;
     RECT  133.669 229.248 133.873 229.272 ;
     RECT  133.801 149.712 133.909 149.736 ;
     RECT  133.667 152.736 133.909 152.76 ;
     RECT  132.799 169.968 133.945 174.84 ;
     RECT  132.797 213.072 133.949 213.096 ;
     RECT  133.837 135.36 133.957 135.384 ;
     RECT  133.957 134.64 134.003 135.384 ;
     RECT  133.801 217.392 134.021 218.232 ;
     RECT  134.003 134.64 134.053 134.664 ;
     RECT  133.549 157.776 134.161 158.664 ;
     RECT  133.657 207.408 134.161 207.768 ;
     RECT  133.409 155.472 134.197 155.496 ;
     RECT  133.769 184.272 134.197 187.176 ;
     RECT  133.909 188.208 134.197 188.232 ;
     RECT  134.161 157.488 134.201 158.664 ;
     RECT  133.729 189.696 134.233 193.032 ;
     RECT  134.053 134.208 134.237 134.664 ;
     RECT  133.909 152.736 134.237 153.48 ;
     RECT  133.837 223.248 134.237 223.272 ;
     RECT  133.621 205.776 134.273 206.376 ;
     RECT  133.805 168.096 134.305 168.312 ;
     RECT  134.197 155.472 134.345 156.456 ;
     RECT  133.945 141.936 134.369 141.96 ;
     RECT  133.801 143.472 134.369 144.6 ;
     RECT  133.873 229.248 134.377 229.32 ;
     RECT  133.945 169.968 134.381 175.416 ;
     RECT  134.201 157.488 134.387 157.512 ;
     RECT  134.201 158.496 134.389 158.664 ;
     RECT  134.369 141.936 134.413 144.6 ;
     RECT  133.859 145.872 134.413 145.896 ;
     RECT  134.233 189.696 134.413 193.656 ;
     RECT  133.693 194.88 134.413 200.04 ;
     RECT  134.273 205.776 134.449 205.944 ;
     RECT  134.413 141.936 134.453 145.896 ;
     RECT  133.229 162.528 134.521 162.648 ;
     RECT  132.304 210.096 134.521 210.12 ;
     RECT  134.377 228.432 134.521 229.32 ;
     RECT  134.345 156.432 134.525 156.456 ;
     RECT  133.667 215.664 134.557 215.688 ;
     RECT  133.801 159.744 134.561 160.584 ;
     RECT  134.305 223.968 134.597 224.04 ;
     RECT  133.697 202.08 134.629 202.44 ;
     RECT  133.837 219.6 134.629 219.624 ;
     RECT  134.413 189.696 134.633 200.04 ;
     RECT  133.909 149.616 134.669 149.736 ;
     RECT  134.389 158.592 134.669 158.664 ;
     RECT  134.561 159.744 134.675 160.536 ;
     RECT  133.763 151.008 134.737 151.032 ;
     RECT  133.441 163.776 134.737 165.576 ;
     RECT  134.557 154.608 134.741 154.632 ;
     RECT  134.021 217.392 134.741 217.704 ;
     RECT  134.521 162.528 134.773 162.744 ;
     RECT  134.737 163.776 134.773 166.44 ;
     RECT  134.237 153.456 134.777 153.48 ;
     RECT  134.629 218.688 134.777 219.624 ;
     RECT  133.769 176.448 134.845 183.144 ;
     RECT  134.197 184.272 134.845 188.232 ;
     RECT  134.269 226.272 134.869 226.296 ;
     RECT  134.633 199.968 134.885 200.04 ;
     RECT  134.869 226.272 134.915 227.16 ;
     RECT  133.813 148.128 134.917 148.152 ;
     RECT  134.521 210.096 134.917 210.792 ;
     RECT  134.915 227.136 134.917 227.16 ;
     RECT  134.521 228.24 134.917 229.32 ;
     RECT  134.917 227.136 134.921 229.32 ;
     RECT  133.957 136.416 134.953 136.44 ;
     RECT  134.377 137.616 134.953 137.64 ;
     RECT  134.885 200.016 134.957 200.04 ;
     RECT  134.921 227.136 134.957 227.448 ;
     RECT  134.921 228.432 134.957 229.32 ;
     RECT  134.341 203.952 134.989 203.976 ;
     RECT  134.449 205.056 134.989 205.944 ;
     RECT  134.953 136.416 134.993 137.64 ;
     RECT  134.773 162.528 135.025 166.44 ;
     RECT  134.305 168.096 135.025 168.408 ;
     RECT  134.809 146.976 135.061 147 ;
     RECT  134.917 148.128 135.061 149.208 ;
     RECT  134.629 201.264 135.065 202.44 ;
     RECT  134.453 143.472 135.097 145.896 ;
     RECT  135.061 146.976 135.097 149.208 ;
     RECT  135.025 162.528 135.097 168.408 ;
     RECT  134.381 174.672 135.097 175.416 ;
     RECT  134.845 176.448 135.097 188.232 ;
     RECT  135.097 162.528 135.101 168.6 ;
     RECT  134.633 189.696 135.101 198.984 ;
     RECT  135.065 202.128 135.109 202.44 ;
     RECT  134.993 136.704 135.133 137.64 ;
     RECT  134.197 139.392 135.133 139.416 ;
     RECT  135.101 162.528 135.133 163.8 ;
     RECT  135.133 161.808 135.137 163.8 ;
     RECT  134.381 169.968 135.137 173.688 ;
     RECT  134.957 228.576 135.155 229.32 ;
     RECT  134.161 207.408 135.169 207.864 ;
     RECT  135.133 136.704 135.173 139.416 ;
     RECT  135.169 207.408 135.205 208.776 ;
     RECT  135.097 174.672 135.277 188.232 ;
     RECT  134.777 219.6 135.277 219.624 ;
     RECT  134.917 222.816 135.313 222.84 ;
     RECT  134.597 223.968 135.313 223.992 ;
     RECT  135.097 143.472 135.317 149.208 ;
     RECT  135.277 219.6 135.317 220.584 ;
     RECT  135.205 207.12 135.347 208.776 ;
     RECT  134.593 212.544 135.385 212.568 ;
     RECT  134.557 215.664 135.385 215.784 ;
     RECT  135.277 174.672 135.397 188.904 ;
     RECT  135.109 202.128 135.421 202.584 ;
     RECT  135.317 143.472 135.425 145.896 ;
     RECT  135.421 202.128 135.461 202.92 ;
     RECT  135.101 190.032 135.491 198.984 ;
     RECT  135.404 200.112 135.491 200.664 ;
     RECT  134.237 134.208 135.493 134.232 ;
     RECT  135.452 135.696 135.493 135.72 ;
     RECT  135.169 140.736 135.493 140.76 ;
     RECT  134.453 141.936 135.493 141.96 ;
     RECT  135.425 143.472 135.493 143.976 ;
     RECT  135.137 163.776 135.497 163.8 ;
     RECT  135.461 202.224 135.533 202.92 ;
     RECT  135.493 134.208 135.539 135.72 ;
     RECT  134.737 150.48 135.601 151.032 ;
     RECT  135.385 215.568 135.601 215.784 ;
     RECT  135.493 143.328 135.605 143.976 ;
     RECT  135.601 150.48 135.605 151.56 ;
     RECT  135.601 215.568 135.605 216.024 ;
     RECT  135.347 207.552 135.637 208.776 ;
     RECT  134.917 209.904 135.637 210.792 ;
     RECT  135.317 220.56 135.637 220.584 ;
     RECT  135.605 215.76 135.641 216.024 ;
     RECT  135.533 202.32 135.673 202.92 ;
     RECT  134.989 203.952 135.673 205.944 ;
     RECT  135.101 165.12 135.677 168.6 ;
     RECT  135.313 222.816 135.677 222.936 ;
     RECT  135.155 229.248 135.677 229.32 ;
     RECT  135.637 207.552 135.683 210.792 ;
     RECT  135.637 220.56 135.683 221.448 ;
     RECT  135.677 166.704 135.685 168.6 ;
     RECT  135.641 216 135.709 216.024 ;
     RECT  134.741 217.68 135.709 217.704 ;
     RECT  135.683 208.944 135.731 210.792 ;
     RECT  135.677 229.296 135.733 229.32 ;
     RECT  135.539 134.208 135.749 135.096 ;
     RECT  135.677 165.12 135.772 165.72 ;
     RECT  135.673 202.32 135.773 205.944 ;
     RECT  135.733 229.296 135.779 230.28 ;
     RECT  135.685 166.704 135.781 168.84 ;
     RECT  135.137 169.968 135.781 172.728 ;
     RECT  135.683 221.184 135.788 221.448 ;
     RECT  135.677 222.816 135.788 222.84 ;
     RECT  135.779 229.344 135.82 230.28 ;
     RECT  135.773 202.32 135.827 206.376 ;
     RECT  135.709 216 135.829 217.704 ;
     RECT  135.788 221.184 135.857 222.84 ;
     RECT  135.829 216 135.875 217.752 ;
     RECT  135.857 221.184 135.875 222.312 ;
     RECT  135.875 221.184 135.901 222.216 ;
     RECT  135.493 157.632 135.929 157.656 ;
     RECT  135.529 130.32 135.932 130.344 ;
     RECT  135.709 155.088 135.997 155.112 ;
     RECT  135.493 140.736 136.001 141.96 ;
     RECT  135.317 146.976 136.001 149.208 ;
     RECT  135.932 129.936 136.019 130.344 ;
     RECT  136.001 148.176 136.033 149.208 ;
     RECT  135.875 217.008 136.037 217.752 ;
     RECT  135.313 223.92 136.037 223.992 ;
     RECT  135.173 136.704 136.067 138.6 ;
     RECT  135.397 173.952 136.069 188.904 ;
     RECT  135.491 190.032 136.069 198.408 ;
     RECT  135.565 156.624 136.105 156.648 ;
     RECT  135.781 166.704 136.105 172.728 ;
     RECT  136.069 173.952 136.105 198.408 ;
     RECT  135.137 161.808 136.117 162.744 ;
     RECT  136.033 148.176 136.141 149.352 ;
     RECT  135.205 158.784 136.141 159.288 ;
     RECT  135.875 216 136.145 216.024 ;
     RECT  135.901 221.424 136.181 222.216 ;
     RECT  136.105 156.624 136.213 157.368 ;
     RECT  136.105 166.704 136.217 198.408 ;
     RECT  135.733 231.456 136.249 231.48 ;
     RECT  135.997 154.464 136.253 155.112 ;
     RECT  136.117 161.808 136.253 163.56 ;
     RECT  135.745 225.168 136.253 225.192 ;
     RECT  136.172 133.2 136.259 133.224 ;
     RECT  136.141 158.64 136.285 159.288 ;
     RECT  134.675 160.512 136.285 160.536 ;
     RECT  136.037 217.152 136.289 217.752 ;
     RECT  135.277 153.264 136.316 153.288 ;
     RECT  136.253 154.464 136.316 155.064 ;
     RECT  136.316 153.264 136.357 155.064 ;
     RECT  136.285 158.64 136.397 160.536 ;
     RECT  136.357 152.736 136.403 155.064 ;
     RECT  136.001 140.736 136.465 140.856 ;
     RECT  135.827 205.728 136.537 206.376 ;
     RECT  135.683 207.552 136.537 207.768 ;
     RECT  135.605 143.616 136.549 143.976 ;
     RECT  135.425 145.488 136.549 145.896 ;
     RECT  136.549 143.616 136.609 145.896 ;
     RECT  136.001 146.976 136.609 147 ;
     RECT  136.141 148.176 136.681 149.4 ;
     RECT  135.605 150.48 136.681 150.504 ;
     RECT  136.253 161.856 136.681 163.56 ;
     RECT  135.772 165.12 136.681 165.576 ;
     RECT  136.217 183.504 136.681 198.408 ;
     RECT  135.385 212.544 136.681 213 ;
     RECT  136.001 141.936 136.741 141.96 ;
     RECT  136.681 183.504 136.741 198.84 ;
     RECT  135.491 200.112 136.741 200.136 ;
     RECT  136.397 158.64 136.789 158.664 ;
     RECT  136.741 183.504 136.789 200.136 ;
     RECT  136.357 201.216 136.789 201.24 ;
     RECT  136.289 217.68 136.789 217.752 ;
     RECT  135.827 202.32 136.861 204.504 ;
     RECT  136.537 205.728 136.861 207.768 ;
     RECT  135.82 229.344 136.897 229.368 ;
     RECT  136.019 130.32 136.933 130.344 ;
     RECT  136.789 183.504 136.969 201.24 ;
     RECT  136.861 202.32 136.969 207.768 ;
     RECT  136.741 141.936 137.005 142.2 ;
     RECT  136.609 143.616 137.005 147 ;
     RECT  136.969 183.504 137.029 207.768 ;
     RECT  135.731 208.944 137.029 210.312 ;
     RECT  135.605 151.536 137.084 151.56 ;
     RECT  136.403 152.736 137.084 152.76 ;
     RECT  136.217 166.704 137.18 182.472 ;
     RECT  136.789 214.464 137.221 214.488 ;
     RECT  134.957 227.424 137.221 227.448 ;
     RECT  136.897 228.768 137.221 229.368 ;
     RECT  137.18 166.656 137.257 182.472 ;
     RECT  137.029 183.504 137.257 210.312 ;
     RECT  136.249 138.672 137.329 138.936 ;
     RECT  136.465 140.208 137.329 140.856 ;
     RECT  137.221 214.464 137.329 215.016 ;
     RECT  135.961 132.192 137.365 132.216 ;
     RECT  136.681 161.856 137.365 165.576 ;
     RECT  137.257 166.656 137.365 210.312 ;
     RECT  136.181 222.192 137.365 222.216 ;
     RECT  136.933 130.32 137.408 130.584 ;
     RECT  137.365 131.568 137.408 132.216 ;
     RECT  135.749 134.208 137.408 134.232 ;
     RECT  136.067 136.704 137.408 137.544 ;
     RECT  137.329 138.672 137.408 140.856 ;
     RECT  137.005 141.936 137.408 147 ;
     RECT  136.681 148.176 137.408 150.504 ;
     RECT  137.084 151.536 137.408 152.76 ;
     RECT  136.403 154.08 137.408 155.064 ;
     RECT  136.213 156.144 137.408 157.368 ;
     RECT  136.789 158.496 137.408 158.664 ;
     RECT  136.397 159.744 137.408 160.536 ;
     RECT  137.365 161.856 137.408 210.312 ;
     RECT  136.681 212.544 137.408 213.192 ;
     RECT  137.329 214.176 137.408 215.016 ;
     RECT  136.789 217.68 137.408 218.472 ;
     RECT  137.041 220.512 137.408 220.536 ;
     RECT  137.365 221.76 137.408 222.216 ;
     RECT  136.037 223.968 137.408 223.992 ;
     RECT  136.321 226.32 137.408 226.344 ;
     RECT  137.221 227.424 137.408 229.368 ;
     RECT  136.249 230.976 137.408 231.48 ;
     RECT  136.645 233.424 137.408 233.448 ;
     RECT  137.401 235.872 137.408 235.896 ;
     RECT  137.408 2.148 137.512 369.372 ;
     RECT  137.512 2.418 137.704 369.102 ;
     RECT  137.704 131.376 137.729 133.464 ;
     RECT  137.704 143.952 137.765 146.184 ;
     RECT  137.765 143.952 137.801 144.072 ;
     RECT  137.704 175.152 137.801 204.84 ;
     RECT  137.704 221.76 137.837 223.992 ;
     RECT  137.704 130.32 137.843 130.344 ;
     RECT  137.704 215.376 137.843 217.752 ;
     RECT  137.704 219.36 137.843 220.584 ;
     RECT  137.837 221.76 137.843 223.896 ;
     RECT  137.704 147.792 137.873 148.68 ;
     RECT  137.704 134.544 137.939 137.64 ;
     RECT  137.939 135.744 137.987 137.64 ;
     RECT  137.729 131.376 138.017 133.368 ;
     RECT  137.704 161.616 138.017 173.976 ;
     RECT  137.704 150.72 138.035 151.848 ;
     RECT  137.704 206.352 138.161 214.296 ;
     RECT  137.704 225.264 138.161 225.912 ;
     RECT  138.161 206.352 138.269 211.656 ;
     RECT  138.017 131.376 138.275 133.08 ;
     RECT  138.017 165.168 138.371 173.976 ;
     RECT  137.987 135.744 138.449 136.728 ;
     RECT  137.704 234.528 138.449 235.896 ;
     RECT  137.939 134.544 138.557 134.568 ;
     RECT  137.704 228.384 138.563 228.936 ;
     RECT  137.704 230.256 138.563 231.48 ;
     RECT  138.269 206.352 138.593 211.56 ;
     RECT  138.161 212.64 138.593 214.296 ;
     RECT  138.563 230.256 138.604 230.28 ;
     RECT  137.765 145.392 138.629 146.184 ;
     RECT  138.371 165.168 138.629 173.832 ;
     RECT  138.593 206.352 138.652 210.984 ;
     RECT  137.704 157.2 138.697 157.512 ;
     RECT  137.704 158.544 138.697 160.536 ;
     RECT  137.704 155.088 138.701 156.072 ;
     RECT  138.593 212.64 138.701 214.2 ;
     RECT  138.035 150.72 138.733 151.56 ;
     RECT  138.161 225.744 138.733 225.912 ;
     RECT  137.843 220.416 138.809 220.584 ;
     RECT  138.017 161.616 138.845 163.944 ;
     RECT  138.809 220.416 138.845 220.44 ;
     RECT  137.704 138.672 138.877 139.512 ;
     RECT  137.801 175.536 138.901 204.84 ;
     RECT  137.843 219.36 138.908 219.384 ;
     RECT  137.873 147.792 138.949 147.816 ;
     RECT  138.877 138.48 138.953 139.512 ;
     RECT  138.701 155.088 138.985 155.736 ;
     RECT  138.901 175.536 138.988 205.032 ;
     RECT  138.697 157.2 138.997 160.536 ;
     RECT  137.704 140.88 139.021 140.904 ;
     RECT  137.843 222.384 139.021 223.896 ;
     RECT  138.449 235.584 139.025 235.896 ;
     RECT  138.997 156.96 139.043 160.536 ;
     RECT  138.629 167.568 139.043 173.832 ;
     RECT  138.449 234.528 139.043 234.6 ;
     RECT  138.563 231.408 139.045 231.48 ;
     RECT  137.704 233.136 139.045 233.448 ;
     RECT  137.704 227.04 139.052 227.064 ;
     RECT  138.949 147.792 139.061 148.056 ;
     RECT  138.652 210.912 139.061 210.984 ;
     RECT  138.908 219.36 139.061 220.104 ;
     RECT  139.043 156.96 139.084 157.512 ;
     RECT  139.045 231.408 139.091 233.448 ;
     RECT  139.043 158.64 139.093 160.536 ;
     RECT  138.845 161.616 139.093 162.36 ;
     RECT  139.091 231.408 139.097 233.16 ;
     RECT  139.021 140.832 139.129 140.904 ;
     RECT  137.704 142.224 139.129 142.248 ;
     RECT  138.733 150.192 139.133 151.56 ;
     RECT  139.052 227.04 139.139 227.16 ;
     RECT  139.129 140.832 139.141 142.248 ;
     RECT  139.021 221.712 139.205 224.28 ;
     RECT  139.141 140.208 139.213 142.248 ;
     RECT  138.701 212.64 139.237 214.056 ;
     RECT  139.213 140.208 139.241 140.904 ;
     RECT  139.241 140.784 139.277 140.904 ;
     RECT  139.213 142.224 139.277 142.248 ;
     RECT  137.843 216.768 139.313 217.752 ;
     RECT  138.877 153.792 139.345 153.816 ;
     RECT  139.277 140.784 139.349 140.856 ;
     RECT  139.061 219.36 139.349 219.384 ;
     RECT  138.275 131.376 139.385 132.84 ;
     RECT  139.133 150.192 139.385 151.512 ;
     RECT  139.043 169.728 139.429 173.832 ;
     RECT  139.313 216.768 139.429 217.704 ;
     RECT  139.061 147.792 139.489 147.816 ;
     RECT  139.429 216.576 139.516 217.704 ;
     RECT  139.345 215.232 139.525 215.256 ;
     RECT  139.516 216.576 139.525 216.6 ;
     RECT  138.733 225.744 139.525 226.008 ;
     RECT  139.139 227.04 139.525 227.064 ;
     RECT  138.953 138.48 139.561 138.696 ;
     RECT  138.629 165.168 139.561 166.488 ;
     RECT  139.084 157.2 139.565 157.512 ;
     RECT  139.237 212.016 139.571 214.056 ;
     RECT  139.525 215.232 139.571 216.6 ;
     RECT  139.561 231.168 139.597 231.336 ;
     RECT  139.129 130.32 139.621 130.344 ;
     RECT  139.385 131.376 139.621 131.64 ;
     RECT  139.525 225.744 139.637 227.064 ;
     RECT  139.621 129.408 139.667 131.64 ;
     RECT  137.801 143.952 139.669 143.976 ;
     RECT  138.629 145.392 139.669 145.944 ;
     RECT  139.345 153.12 139.669 153.816 ;
     RECT  138.985 154.8 139.669 155.736 ;
     RECT  139.571 213.408 139.673 213.576 ;
     RECT  139.571 215.76 139.709 216.6 ;
     RECT  138.652 206.352 139.777 209.4 ;
     RECT  139.561 138.048 139.781 138.696 ;
     RECT  139.061 210.912 139.781 210.936 ;
     RECT  139.669 143.952 139.813 145.944 ;
     RECT  139.205 222.24 139.817 224.28 ;
     RECT  139.669 234.288 139.817 234.312 ;
     RECT  139.597 231.072 139.868 231.336 ;
     RECT  139.669 153.12 139.889 155.736 ;
     RECT  139.637 227.04 139.889 227.064 ;
     RECT  139.093 158.64 139.921 162.36 ;
     RECT  138.845 163.44 139.921 163.944 ;
     RECT  139.673 213.408 139.925 213.432 ;
     RECT  139.817 222.24 139.948 223.224 ;
     RECT  139.868 230.784 139.955 231.336 ;
     RECT  139.813 143.952 139.957 146.28 ;
     RECT  139.489 147.264 139.957 147.816 ;
     RECT  139.429 169.728 139.957 174.12 ;
     RECT  138.988 175.536 139.957 204.792 ;
     RECT  139.633 134.592 139.961 134.616 ;
     RECT  139.948 222.24 139.969 222.888 ;
     RECT  139.889 153.6 139.993 155.736 ;
     RECT  139.025 235.872 139.996 235.896 ;
     RECT  139.561 164.976 140.029 166.488 ;
     RECT  139.043 167.568 140.029 168.648 ;
     RECT  139.565 157.488 140.033 157.512 ;
     RECT  139.955 231.072 140.069 231.336 ;
     RECT  139.385 150.432 140.105 151.512 ;
     RECT  139.957 169.728 140.137 204.792 ;
     RECT  139.921 158.64 140.173 163.944 ;
     RECT  140.173 158.064 140.209 163.944 ;
     RECT  140.029 164.976 140.209 168.648 ;
     RECT  140.137 169.728 140.209 205.368 ;
     RECT  139.777 206.352 140.209 209.448 ;
     RECT  139.993 153.6 140.236 156.168 ;
     RECT  140.065 219.936 140.249 219.96 ;
     RECT  139.097 232.368 140.277 233.16 ;
     RECT  140.277 233.04 140.284 233.16 ;
     RECT  139.349 140.784 140.285 140.808 ;
     RECT  140.209 158.064 140.353 168.648 ;
     RECT  140.209 169.728 140.353 209.448 ;
     RECT  139.667 130.848 140.357 131.64 ;
     RECT  139.957 143.952 140.387 147.816 ;
     RECT  139.385 132.816 140.393 132.84 ;
     RECT  138.563 228.384 140.465 228.792 ;
     RECT  138.449 135.744 140.533 135.912 ;
     RECT  139.667 129.408 140.537 129.432 ;
     RECT  140.387 146.496 140.537 147.288 ;
     RECT  139.817 224.256 140.609 224.28 ;
     RECT  139.969 222.24 140.641 222.36 ;
     RECT  140.236 154.08 140.681 156.168 ;
     RECT  140.641 221.808 140.681 222.36 ;
     RECT  139.345 148.8 140.717 148.824 ;
     RECT  139.705 236.976 140.725 237 ;
     RECT  140.389 238.416 140.771 238.44 ;
     RECT  139.781 138.048 140.78 138.072 ;
     RECT  140.78 138.048 140.821 139.032 ;
     RECT  140.725 236.976 140.832 237.288 ;
     RECT  140.533 135.744 140.857 136.824 ;
     RECT  140.821 138.048 140.867 139.128 ;
     RECT  140.785 140.208 140.869 140.232 ;
     RECT  140.105 150.912 140.876 151.512 ;
     RECT  140.537 146.496 140.897 146.52 ;
     RECT  140.876 150.912 140.933 151.608 ;
     RECT  140.933 151.152 140.963 151.608 ;
     RECT  139.571 212.016 140.965 212.04 ;
     RECT  140.867 138.048 141.005 138.072 ;
     RECT  140.137 142.512 141.005 142.536 ;
     RECT  140.917 152.784 141.037 152.808 ;
     RECT  141.037 152.736 141.038 152.808 ;
     RECT  140.677 235.584 141.041 235.608 ;
     RECT  140.965 212.016 141.109 212.952 ;
     RECT  139.516 217.68 141.109 217.704 ;
     RECT  140.353 158.064 141.145 209.448 ;
     RECT  141.109 211.248 141.145 212.952 ;
     RECT  141.073 142.464 141.157 142.488 ;
     RECT  141.145 158.064 141.217 212.952 ;
     RECT  141.217 158.064 141.221 213.144 ;
     RECT  140.281 225.312 141.221 225.336 ;
     RECT  140.681 221.808 141.253 221.832 ;
     RECT  141.221 158.064 141.257 204.6 ;
     RECT  140.681 155.28 141.393 156.168 ;
     RECT  140.069 231.312 141.397 231.336 ;
     RECT  140.857 135.216 141.493 136.824 ;
     RECT  141.493 134.88 141.539 136.824 ;
     RECT  140.929 130.176 141.545 130.2 ;
     RECT  141.539 134.88 141.581 134.904 ;
     RECT  140.465 228.768 141.613 228.792 ;
     RECT  141.541 215.904 141.637 215.928 ;
     RECT  141.109 216.96 141.637 217.704 ;
     RECT  141.596 214.56 141.683 214.584 ;
     RECT  140.284 233.136 141.721 233.16 ;
     RECT  141.539 135.888 141.757 136.824 ;
     RECT  141.253 221.088 141.757 221.832 ;
     RECT  141.393 156.096 141.877 156.168 ;
     RECT  141.721 157.824 141.877 157.848 ;
     RECT  141.637 215.904 141.884 217.704 ;
     RECT  141.757 221.088 141.901 222.072 ;
     RECT  141.649 225.552 141.901 225.576 ;
     RECT  140.387 143.952 141.925 145.416 ;
     RECT  141.865 147.504 141.925 147.528 ;
     RECT  141.145 148.512 141.925 148.536 ;
     RECT  141.884 215.904 141.925 217.944 ;
     RECT  141.541 219.552 141.925 219.576 ;
     RECT  141.901 221.088 141.925 222.36 ;
     RECT  141.613 227.952 141.925 228.792 ;
     RECT  141.925 227.952 141.932 229.128 ;
     RECT  140.963 151.152 142.009 151.512 ;
     RECT  141.038 152.736 142.009 152.76 ;
     RECT  141.221 205.728 142.009 213.144 ;
     RECT  140.357 131.616 142.081 131.64 ;
     RECT  141.973 132.624 142.081 132.648 ;
     RECT  142.076 127.872 142.117 127.896 ;
     RECT  142.081 131.616 142.117 132.648 ;
     RECT  141.325 236.496 142.117 236.568 ;
     RECT  141.901 149.664 142.165 149.688 ;
     RECT  142.009 151.152 142.165 152.76 ;
     RECT  140.681 154.08 142.165 154.2 ;
     RECT  141.397 231.312 142.165 232.056 ;
     RECT  141.721 233.136 142.165 233.688 ;
     RECT  142.117 236.496 142.165 236.616 ;
     RECT  142.165 151.152 142.189 154.2 ;
     RECT  141.925 147.504 142.22 148.536 ;
     RECT  142.165 149.664 142.22 149.88 ;
     RECT  141.685 141.168 142.261 141.192 ;
     RECT  142.009 142.176 142.261 142.2 ;
     RECT  142.165 231.312 142.297 233.688 ;
     RECT  142.189 151.152 142.357 154.92 ;
     RECT  141.877 156.096 142.357 157.848 ;
     RECT  141.932 227.136 142.369 229.128 ;
     RECT  141.257 159.168 142.405 204.6 ;
     RECT  142.009 205.728 142.405 213.72 ;
     RECT  142.405 159.168 142.453 213.72 ;
     RECT  142.369 227.136 142.453 229.656 ;
     RECT  141.925 215.904 142.469 222.36 ;
     RECT  142.22 147.504 142.477 149.88 ;
     RECT  142.117 131.04 142.513 132.648 ;
     RECT  141.577 129.312 142.549 129.336 ;
     RECT  142.297 230.88 142.549 233.688 ;
     RECT  141.793 234.96 142.549 234.984 ;
     RECT  141.925 143.952 142.585 146.28 ;
     RECT  141.901 225.552 142.585 225.912 ;
     RECT  142.453 227.136 142.585 229.704 ;
     RECT  142.477 134.304 142.597 134.328 ;
     RECT  142.585 225.552 142.621 229.704 ;
     RECT  142.469 215.52 142.657 222.36 ;
     RECT  142.513 130.848 142.693 132.648 ;
     RECT  142.597 134.016 142.693 134.328 ;
     RECT  142.621 225.072 142.729 229.704 ;
     RECT  142.117 127.248 142.808 127.896 ;
     RECT  142.549 129.312 142.808 129.432 ;
     RECT  142.693 130.848 142.808 134.328 ;
     RECT  141.757 135.888 142.808 137.064 ;
     RECT  140.867 139.104 142.808 139.128 ;
     RECT  142.261 140.736 142.808 141.192 ;
     RECT  142.261 142.176 142.808 142.776 ;
     RECT  142.585 143.808 142.808 146.28 ;
     RECT  142.477 147.312 142.808 149.88 ;
     RECT  142.357 151.152 142.808 157.848 ;
     RECT  142.453 159.072 142.808 213.72 ;
     RECT  142.657 215.088 142.808 222.36 ;
     RECT  142.729 224.256 142.808 229.704 ;
     RECT  142.549 230.88 142.808 234.984 ;
     RECT  142.165 236.496 142.808 237 ;
     RECT  141.109 239.904 142.808 239.928 ;
     RECT  142.808 2.148 142.912 369.372 ;
     RECT  142.912 2.418 143.104 369.102 ;
     RECT  143.104 224.544 143.267 226.344 ;
     RECT  143.104 159.168 143.309 207.768 ;
     RECT  143.104 137.904 143.317 147.528 ;
     RECT  143.309 159.552 143.363 207.768 ;
     RECT  143.363 159.648 143.453 207.768 ;
     RECT  143.104 209.088 143.525 219.432 ;
     RECT  143.104 231.456 143.525 231.48 ;
     RECT  143.104 222.864 143.641 222.888 ;
     RECT  143.104 232.512 143.705 234.552 ;
     RECT  143.104 156.768 143.733 158.136 ;
     RECT  143.525 209.088 143.741 217.752 ;
     RECT  143.705 232.896 143.76 234.552 ;
     RECT  143.317 137.904 143.813 144.264 ;
     RECT  143.104 149.04 143.849 150.456 ;
     RECT  143.104 236.976 143.884 239.928 ;
     RECT  143.453 159.744 143.885 207.768 ;
     RECT  143.741 209.088 143.885 215.496 ;
     RECT  143.104 134.016 143.921 134.568 ;
     RECT  143.885 210.336 143.921 215.496 ;
     RECT  143.104 129.936 143.957 131.64 ;
     RECT  143.104 220.848 143.957 221.112 ;
     RECT  143.885 159.744 144.029 204.6 ;
     RECT  143.741 216.576 144.029 217.752 ;
     RECT  143.76 234.288 144.029 234.552 ;
     RECT  143.104 135.888 144.083 136.2 ;
     RECT  143.813 137.904 144.133 143.064 ;
     RECT  143.104 127.248 144.137 127.272 ;
     RECT  143.267 224.544 144.169 225.912 ;
     RECT  143.884 236.976 144.169 238.248 ;
     RECT  143.921 210.336 144.173 210.552 ;
     RECT  143.885 205.584 144.179 207.768 ;
     RECT  143.317 145.296 144.181 147.528 ;
     RECT  143.849 149.04 144.181 149.064 ;
     RECT  144.181 145.296 144.227 149.064 ;
     RECT  143.885 209.088 144.236 209.352 ;
     RECT  143.733 157.2 144.241 158.136 ;
     RECT  144.227 145.296 144.268 148.152 ;
     RECT  144.133 136.752 144.281 143.064 ;
     RECT  143.525 219.12 144.281 219.432 ;
     RECT  144.236 208.992 144.323 209.352 ;
     RECT  143.849 150.144 144.349 150.456 ;
     RECT  143.104 235.776 144.349 235.8 ;
     RECT  144.169 236.88 144.349 238.248 ;
     RECT  144.268 145.296 144.353 148.056 ;
     RECT  143.921 134.256 144.371 134.568 ;
     RECT  144.349 150.144 144.389 150.504 ;
     RECT  144.179 206.976 144.389 207.768 ;
     RECT  143.921 211.536 144.389 215.496 ;
     RECT  143.957 129.936 144.457 130.392 ;
     RECT  144.389 150.336 144.461 150.504 ;
     RECT  144.281 219.408 144.469 219.432 ;
     RECT  144.389 206.976 144.497 207.48 ;
     RECT  144.353 145.296 144.533 145.896 ;
     RECT  144.349 235.776 144.533 238.248 ;
     RECT  143.104 151.632 144.569 151.656 ;
     RECT  144.389 211.776 144.605 215.496 ;
     RECT  144.533 235.968 144.605 238.248 ;
     RECT  144.457 129.456 144.641 130.392 ;
     RECT  144.173 210.336 144.641 210.36 ;
     RECT  144.029 160.032 144.707 204.6 ;
     RECT  144.029 216.624 144.749 217.752 ;
     RECT  144.457 135.456 144.755 135.48 ;
     RECT  144.281 136.752 144.755 142.2 ;
     RECT  144.709 223.392 144.757 223.416 ;
     RECT  144.169 224.448 144.757 225.912 ;
     RECT  143.813 144.24 144.781 144.264 ;
     RECT  144.533 145.296 144.781 145.32 ;
     RECT  143.76 232.896 144.785 232.92 ;
     RECT  144.241 157.2 144.821 158.424 ;
     RECT  144.707 187.632 144.821 204.6 ;
     RECT  144.029 234.288 144.821 234.312 ;
     RECT  144.605 211.824 144.857 215.496 ;
     RECT  143.957 220.848 144.857 220.872 ;
     RECT  143.957 131.616 144.929 131.64 ;
     RECT  144.755 137.904 144.929 142.2 ;
     RECT  143.104 228 144.956 228.024 ;
     RECT  143.104 229.104 144.956 229.128 ;
     RECT  144.857 211.824 144.965 215.304 ;
     RECT  144.749 217.008 144.965 217.752 ;
     RECT  144.641 129.936 144.997 130.392 ;
     RECT  144.956 228 144.997 229.128 ;
     RECT  144.889 230.64 144.997 230.664 ;
     RECT  144.929 137.904 145.001 140.856 ;
     RECT  144.371 134.256 145.033 134.28 ;
     RECT  144.821 158.256 145.033 158.424 ;
     RECT  144.755 136.752 145.037 136.776 ;
     RECT  145.001 137.904 145.073 139.368 ;
     RECT  144.997 129.936 145.081 130.584 ;
     RECT  143.104 153.024 145.1 153.048 ;
     RECT  144.757 222.864 145.101 225.912 ;
     RECT  145.033 158.256 145.105 158.952 ;
     RECT  144.707 160.032 145.105 186.504 ;
     RECT  145.101 222.864 145.109 225.816 ;
     RECT  144.605 235.968 145.109 237.768 ;
     RECT  145.109 237.36 145.132 237.768 ;
     RECT  145.105 158.256 145.145 186.504 ;
     RECT  145.109 222.864 145.145 224.04 ;
     RECT  144.997 227.52 145.145 230.664 ;
     RECT  145.1 152.496 145.187 153.048 ;
     RECT  144.965 213.648 145.217 215.304 ;
     RECT  145.145 227.52 145.217 229.704 ;
     RECT  145.145 223.296 145.253 224.04 ;
     RECT  145.109 225.072 145.253 225.816 ;
     RECT  145.253 223.296 145.283 223.992 ;
     RECT  144.461 150.336 145.289 150.36 ;
     RECT  145.145 158.256 145.289 160.776 ;
     RECT  145.217 228.576 145.289 229.704 ;
     RECT  143.104 154.08 145.321 154.92 ;
     RECT  145.189 234.864 145.325 234.888 ;
     RECT  144.821 187.824 145.357 204.6 ;
     RECT  144.179 205.584 145.357 205.608 ;
     RECT  144.497 207.456 145.357 207.48 ;
     RECT  144.469 219.408 145.381 219.864 ;
     RECT  144.353 146.88 145.433 148.056 ;
     RECT  145.289 228.576 145.433 229.512 ;
     RECT  145.381 219.408 145.468 220.68 ;
     RECT  145.217 213.648 145.469 214.584 ;
     RECT  145.357 187.824 145.505 205.608 ;
     RECT  145.433 228.576 145.541 229.08 ;
     RECT  145.132 237.744 145.541 237.768 ;
     RECT  145.001 140.832 145.685 140.856 ;
     RECT  144.781 144.24 145.765 145.32 ;
     RECT  145.187 153.024 145.789 153.048 ;
     RECT  145.321 154.08 145.789 154.968 ;
     RECT  145.469 213.648 145.793 213.72 ;
     RECT  145.145 161.904 145.825 186.504 ;
     RECT  144.929 141.84 145.829 142.2 ;
     RECT  145.765 128.208 145.852 128.232 ;
     RECT  145.765 143.52 145.852 145.32 ;
     RECT  145.357 207.456 145.865 208.2 ;
     RECT  145.865 207.456 145.901 207.48 ;
     RECT  144.323 209.328 145.937 209.352 ;
     RECT  145.541 228.576 145.937 228.6 ;
     RECT  145.825 161.904 145.964 186.84 ;
     RECT  145.505 187.824 145.964 202.968 ;
     RECT  144.965 217.728 145.969 217.752 ;
     RECT  143.884 239.904 145.969 239.928 ;
     RECT  145.969 217.728 146.005 218.376 ;
     RECT  145.468 219.408 146.005 219.864 ;
     RECT  145.381 222 146.005 222.024 ;
     RECT  145.073 138.528 146.153 139.368 ;
     RECT  144.821 157.2 146.156 157.224 ;
     RECT  145.289 158.256 146.156 160.584 ;
     RECT  145.969 239.28 146.189 239.928 ;
     RECT  145.505 204.192 146.221 205.608 ;
     RECT  144.781 151.392 146.225 151.416 ;
     RECT  145.793 213.696 146.225 213.72 ;
     RECT  146.189 239.904 146.225 239.928 ;
     RECT  145.069 156.192 146.243 156.216 ;
     RECT  146.156 157.2 146.243 160.584 ;
     RECT  145.964 161.904 146.261 202.968 ;
     RECT  145.033 133.92 146.293 134.28 ;
     RECT  145.081 129.936 146.333 129.96 ;
     RECT  146.243 157.2 146.365 158.472 ;
     RECT  146.005 221.664 146.365 222.024 ;
     RECT  145.283 223.296 146.365 223.416 ;
     RECT  145.253 225.792 146.401 225.816 ;
     RECT  146.221 204.192 146.405 205.704 ;
     RECT  145.789 153.024 146.437 154.968 ;
     RECT  146.405 205.68 146.473 205.704 ;
     RECT  146.149 207.168 146.473 207.192 ;
     RECT  146.401 225.024 146.473 225.816 ;
     RECT  146.473 205.68 146.477 207.192 ;
     RECT  146.005 217.728 146.477 219.864 ;
     RECT  146.437 151.968 146.483 154.968 ;
     RECT  146.153 138.528 146.509 138.84 ;
     RECT  146.261 161.904 146.509 186.024 ;
     RECT  146.405 204.192 146.509 204.216 ;
     RECT  146.293 133.92 146.513 135.672 ;
     RECT  146.365 156.336 146.513 158.472 ;
     RECT  146.473 224.976 146.545 225.816 ;
     RECT  146.513 156.912 146.549 158.472 ;
     RECT  146.477 206.64 146.557 207.192 ;
     RECT  146.477 218.352 146.617 219.864 ;
     RECT  146.261 187.488 146.621 202.968 ;
     RECT  146.509 230.832 146.677 230.856 ;
     RECT  146.437 208.656 146.693 209.112 ;
     RECT  146.677 230.832 146.723 232.008 ;
     RECT  145.433 146.928 146.725 148.056 ;
     RECT  146.509 138 146.729 138.84 ;
     RECT  146.513 135.648 146.765 135.672 ;
     RECT  146.483 151.968 146.765 152.76 ;
     RECT  146.725 146.832 146.771 148.056 ;
     RECT  146.365 221.664 146.773 223.416 ;
     RECT  146.545 224.976 146.773 226.344 ;
     RECT  146.773 221.664 146.801 226.344 ;
     RECT  146.771 146.832 146.821 147.144 ;
     RECT  146.621 200.64 146.833 202.968 ;
     RECT  146.509 204.048 146.833 204.216 ;
     RECT  146.617 218.352 146.837 220.68 ;
     RECT  146.837 218.88 146.869 220.68 ;
     RECT  146.801 221.664 146.869 224.04 ;
     RECT  146.621 187.488 146.915 199.56 ;
     RECT  145.109 235.968 146.941 235.992 ;
     RECT  146.221 214.704 146.977 214.728 ;
     RECT  146.941 235.44 146.981 235.992 ;
     RECT  146.869 218.88 147.017 224.04 ;
     RECT  147.017 218.88 147.053 220.68 ;
     RECT  146.765 151.968 147.107 152.424 ;
     RECT  146.723 231.456 147.121 232.008 ;
     RECT  146.077 233.088 147.121 233.112 ;
     RECT  147.017 221.664 147.125 223.32 ;
     RECT  146.693 208.752 147.157 209.112 ;
     RECT  146.401 129.984 147.197 130.008 ;
     RECT  146.761 216.528 147.197 216.552 ;
     RECT  146.483 154.032 147.203 154.968 ;
     RECT  146.243 159.456 147.301 160.584 ;
     RECT  146.509 161.616 147.301 186.024 ;
     RECT  146.981 235.44 147.301 235.464 ;
     RECT  145.829 141.936 147.337 142.2 ;
     RECT  147.229 149.664 147.337 149.688 ;
     RECT  145.852 144.24 147.404 145.32 ;
     RECT  145.217 227.52 147.404 227.544 ;
     RECT  146.801 225.024 147.445 226.344 ;
     RECT  147.404 227.52 147.445 228.168 ;
     RECT  147.301 159.456 147.481 186.024 ;
     RECT  147.481 159.456 147.517 186.216 ;
     RECT  147.517 139.488 147.637 140.136 ;
     RECT  147.517 159.216 147.637 186.216 ;
     RECT  146.915 187.488 147.637 199.08 ;
     RECT  147.301 216.576 147.697 216.6 ;
     RECT  147.404 144 147.733 145.32 ;
     RECT  146.821 146.4 147.733 147.144 ;
     RECT  146.833 200.64 147.733 204.216 ;
     RECT  146.545 131.52 147.829 131.544 ;
     RECT  147.107 152.4 147.913 152.424 ;
     RECT  147.913 152.4 147.949 152.76 ;
     RECT  146.557 207.168 147.985 207.192 ;
     RECT  147.841 213.648 148.021 213.672 ;
     RECT  146.977 214.704 148.021 214.776 ;
     RECT  147.337 149.664 148.057 150.36 ;
     RECT  147.985 206.448 148.057 207.192 ;
     RECT  144.965 211.824 148.057 212.664 ;
     RECT  148.021 213.648 148.057 214.776 ;
     RECT  148.021 138.144 148.069 138.168 ;
     RECT  147.637 139.488 148.069 140.808 ;
     RECT  146.513 134.112 148.165 134.28 ;
     RECT  147.637 159.216 148.165 199.08 ;
     RECT  148.057 211.824 148.165 214.776 ;
     RECT  147.829 130.512 148.208 130.536 ;
     RECT  147.829 131.52 148.208 132.072 ;
     RECT  148.165 133.824 148.208 134.28 ;
     RECT  148.069 137.328 148.208 140.808 ;
     RECT  147.337 141.936 148.208 142.968 ;
     RECT  147.733 144 148.208 147.192 ;
     RECT  147.661 148.56 148.208 148.584 ;
     RECT  148.057 149.664 148.208 151.32 ;
     RECT  147.949 152.4 148.208 152.904 ;
     RECT  147.203 154.032 148.208 154.056 ;
     RECT  147.661 155.136 148.208 155.16 ;
     RECT  146.549 156.912 148.208 158.136 ;
     RECT  148.165 159.12 148.208 199.08 ;
     RECT  147.733 200.64 148.208 205.128 ;
     RECT  148.057 206.448 148.208 207.72 ;
     RECT  147.157 208.752 148.208 209.688 ;
     RECT  148.165 211.824 148.208 215.544 ;
     RECT  147.697 216.576 148.208 216.648 ;
     RECT  147.053 218.88 148.208 219.864 ;
     RECT  147.125 221.76 148.208 223.32 ;
     RECT  147.445 225.024 148.208 228.168 ;
     RECT  147.121 231.456 148.208 233.112 ;
     RECT  147.301 234.24 148.208 235.464 ;
     RECT  148.208 2.148 148.312 369.372 ;
     RECT  148.312 2.418 148.504 369.102 ;
     RECT  148.504 152.352 148.565 152.76 ;
     RECT  148.504 137.904 148.601 138.984 ;
     RECT  148.504 211.536 148.684 216.408 ;
     RECT  148.504 209.232 148.691 210.36 ;
     RECT  148.504 133.824 148.709 133.848 ;
     RECT  148.504 156.72 148.709 186.36 ;
     RECT  148.504 201.744 148.709 205.224 ;
     RECT  148.504 199.68 148.745 200.088 ;
     RECT  148.504 206.784 148.745 208.248 ;
     RECT  148.745 206.784 148.78 207.192 ;
     RECT  148.691 209.232 148.781 209.832 ;
     RECT  148.684 212.64 148.781 216.408 ;
     RECT  148.504 196.08 148.817 198.648 ;
     RECT  148.709 160.416 148.835 186.36 ;
     RECT  148.504 132.432 148.853 132.456 ;
     RECT  148.684 211.536 148.853 211.56 ;
     RECT  148.709 156.72 148.883 159.24 ;
     RECT  148.504 144 148.889 144.888 ;
     RECT  148.889 144 148.925 144.648 ;
     RECT  148.565 152.352 148.925 152.424 ;
     RECT  148.883 156.72 148.925 157.368 ;
     RECT  148.709 201.744 148.925 202.056 ;
     RECT  148.835 160.416 149.033 176.424 ;
     RECT  148.504 187.488 149.075 193.656 ;
     RECT  148.504 147.792 149.177 149.928 ;
     RECT  149.033 160.416 149.285 174.792 ;
     RECT  148.781 214.224 149.321 216.408 ;
     RECT  148.504 142.176 149.356 142.776 ;
     RECT  148.504 217.68 149.356 221.784 ;
     RECT  148.78 207.168 149.363 207.192 ;
     RECT  148.504 154.032 149.393 154.056 ;
     RECT  149.075 187.776 149.393 193.656 ;
     RECT  149.321 214.224 149.393 215.64 ;
     RECT  148.781 209.232 149.401 209.256 ;
     RECT  148.504 150.912 149.497 151.32 ;
     RECT  148.835 177.456 149.5 186.36 ;
     RECT  149.393 188.064 149.533 193.656 ;
     RECT  148.504 194.832 149.533 195.096 ;
     RECT  149.177 148.848 149.537 149.928 ;
     RECT  149.285 162.72 149.537 174.792 ;
     RECT  148.504 225.792 149.537 226.872 ;
     RECT  149.5 185.808 149.557 186.36 ;
     RECT  149.537 164.064 149.603 174.792 ;
     RECT  148.601 137.904 149.605 138.168 ;
     RECT  149.177 147.792 149.609 147.816 ;
     RECT  149.393 214.416 149.645 215.64 ;
     RECT  149.356 217.92 149.681 221.784 ;
     RECT  149.537 225.792 149.681 226.344 ;
     RECT  149.533 188.064 149.699 195.096 ;
     RECT  148.504 223.824 149.749 223.848 ;
     RECT  148.745 208.224 149.753 208.248 ;
     RECT  148.781 212.64 149.753 213 ;
     RECT  149.681 217.92 149.753 220.536 ;
     RECT  149.681 226.272 149.789 226.344 ;
     RECT  149.756 222.768 149.797 222.792 ;
     RECT  149.749 223.824 149.797 224.76 ;
     RECT  149.797 222.768 149.843 224.76 ;
     RECT  149.033 175.776 149.845 176.424 ;
     RECT  149.5 177.456 149.845 184.776 ;
     RECT  148.817 196.512 149.845 198.648 ;
     RECT  148.745 200.064 149.845 200.088 ;
     RECT  149.845 196.512 149.861 200.088 ;
     RECT  148.504 135.504 149.897 135.528 ;
     RECT  149.497 153.408 149.897 153.432 ;
     RECT  148.709 203.184 149.921 205.224 ;
     RECT  149.753 217.92 149.925 220.152 ;
     RECT  149.557 185.808 149.929 186.408 ;
     RECT  149.921 203.184 149.929 205.8 ;
     RECT  149.537 148.848 149.933 149.352 ;
     RECT  149.843 223.296 149.933 223.32 ;
     RECT  149.843 224.4 149.933 224.424 ;
     RECT  148.925 201.744 149.965 202.008 ;
     RECT  149.929 203.184 149.965 206.136 ;
     RECT  149.537 162.72 149.969 162.888 ;
     RECT  149.603 165.888 149.969 174.792 ;
     RECT  149.965 201.744 149.969 206.136 ;
     RECT  149.861 198.624 149.987 200.088 ;
     RECT  148.504 140.208 149.989 140.232 ;
     RECT  149.497 150.912 149.996 151.944 ;
     RECT  149.605 137.904 150.001 138.456 ;
     RECT  149.989 139.632 150.001 140.232 ;
     RECT  149.845 175.776 150.005 184.776 ;
     RECT  149.699 188.064 150.005 193.992 ;
     RECT  149.969 204.144 150.005 206.136 ;
     RECT  149.987 198.624 150.041 198.648 ;
     RECT  150.001 137.904 150.073 140.232 ;
     RECT  150.005 175.776 150.073 176.424 ;
     RECT  150.073 136.944 150.076 140.232 ;
     RECT  149.996 150.864 150.083 151.944 ;
     RECT  150.076 136.944 150.085 139.128 ;
     RECT  148.504 155.136 150.145 155.16 ;
     RECT  148.504 146.4 150.149 146.76 ;
     RECT  150.005 177.552 150.172 184.776 ;
     RECT  150.005 206.112 150.181 206.136 ;
     RECT  150.145 155.136 150.185 155.304 ;
     RECT  149.603 164.064 150.221 164.904 ;
     RECT  149.987 200.064 150.277 200.088 ;
     RECT  149.969 201.744 150.277 203.064 ;
     RECT  149.645 214.416 150.293 215.112 ;
     RECT  148.925 156.864 150.325 157.368 ;
     RECT  149.753 212.64 150.329 212.904 ;
     RECT  149.857 211.44 150.397 211.464 ;
     RECT  149.681 221.76 150.401 221.784 ;
     RECT  150.325 156.768 150.419 157.368 ;
     RECT  149.285 160.416 150.433 161.688 ;
     RECT  150.289 162.672 150.433 162.696 ;
     RECT  150.221 164.064 150.437 164.808 ;
     RECT  150.073 175.104 150.437 176.424 ;
     RECT  150.005 188.112 150.46 193.992 ;
     RECT  150.085 136.944 150.467 138.456 ;
     RECT  148.925 144 150.469 144.408 ;
     RECT  150.083 150.912 150.469 151.944 ;
     RECT  150.469 150.912 150.473 153 ;
     RECT  150.181 206.112 150.473 206.568 ;
     RECT  150.076 140.112 150.505 140.232 ;
     RECT  150.149 146.4 150.509 146.472 ;
     RECT  150.473 151.296 150.509 153 ;
     RECT  148.883 158.448 150.509 159.24 ;
     RECT  149.969 165.888 150.509 173.688 ;
     RECT  150.509 151.92 150.515 153 ;
     RECT  149.925 217.92 150.524 219.048 ;
     RECT  150.397 211.248 150.533 211.464 ;
     RECT  149.933 149.328 150.545 149.352 ;
     RECT  150.515 152.16 150.553 153 ;
     RECT  150.524 217.296 150.565 219.048 ;
     RECT  150.467 138.384 150.581 138.456 ;
     RECT  150.469 144 150.581 144.792 ;
     RECT  150.437 175.968 150.581 176.424 ;
     RECT  150.505 140.112 150.589 140.808 ;
     RECT  150.46 188.112 150.611 193.512 ;
     RECT  150.565 216.576 150.611 219.048 ;
     RECT  150.533 210.336 150.617 211.464 ;
     RECT  150.611 189.264 150.653 193.512 ;
     RECT  150.005 204.144 150.653 205.032 ;
     RECT  149.356 142.176 150.659 142.2 ;
     RECT  149.861 196.512 150.685 197.448 ;
     RECT  150.277 200.064 150.689 203.064 ;
     RECT  150.329 212.88 150.689 212.904 ;
     RECT  150.611 216.576 150.689 216.744 ;
     RECT  150.653 189.264 150.725 191.784 ;
     RECT  150.172 183.408 150.761 184.776 ;
     RECT  150.725 189.264 150.761 191.544 ;
     RECT  149.699 195.072 150.761 195.096 ;
     RECT  150.253 208.8 150.793 208.824 ;
     RECT  150.589 140.112 150.797 140.616 ;
     RECT  150.473 206.112 150.797 206.376 ;
     RECT  150.617 210.912 150.829 211.464 ;
     RECT  150.793 208.8 150.865 209.16 ;
     RECT  150.509 165.888 150.901 173.544 ;
     RECT  150.761 183.696 150.901 184.776 ;
     RECT  149.929 185.808 150.901 186.456 ;
     RECT  150.653 192.816 150.905 193.512 ;
     RECT  150.653 204.144 150.937 204.936 ;
     RECT  150.581 144 150.941 144.408 ;
     RECT  150.905 192.816 150.941 193.032 ;
     RECT  150.829 210.912 150.941 211.608 ;
     RECT  150.941 144.336 150.947 144.408 ;
     RECT  150.685 196.464 150.977 197.448 ;
     RECT  150.901 183.696 150.985 186.456 ;
     RECT  150.689 200.064 151.004 202.152 ;
     RECT  150.977 196.512 151.009 197.448 ;
     RECT  150.293 214.416 151.013 214.44 ;
     RECT  151.009 196.512 151.045 197.736 ;
     RECT  151.004 198.816 151.045 202.152 ;
     RECT  149.789 226.272 151.045 226.296 ;
     RECT  150.865 208.56 151.049 209.16 ;
     RECT  150.941 210.912 151.049 211.416 ;
     RECT  151.049 208.8 151.085 209.16 ;
     RECT  151.045 196.512 151.091 202.152 ;
     RECT  150.793 147.648 151.153 147.672 ;
     RECT  150.985 184.656 151.157 186.456 ;
     RECT  150.689 216.72 151.157 216.744 ;
     RECT  151.091 199.488 151.187 202.152 ;
     RECT  150.611 217.728 151.189 219.048 ;
     RECT  149.925 220.128 151.189 220.152 ;
     RECT  150.172 177.552 151.193 182.376 ;
     RECT  151.187 200.976 151.228 201.768 ;
     RECT  151.193 181.344 151.229 182.376 ;
     RECT  150.685 142.464 151.265 142.488 ;
     RECT  150.901 145.392 151.265 145.416 ;
     RECT  151.153 147.6 151.265 147.672 ;
     RECT  150.797 206.352 151.265 206.376 ;
     RECT  151.189 217.728 151.301 220.152 ;
     RECT  150.185 155.28 151.333 155.304 ;
     RECT  151.301 219.408 151.405 220.152 ;
     RECT  150.581 138.432 151.409 138.456 ;
     RECT  151.045 226.176 151.441 226.296 ;
     RECT  150.937 204.048 151.481 204.936 ;
     RECT  151.333 154.512 151.513 155.304 ;
     RECT  150.433 160.416 151.513 162.696 ;
     RECT  150.437 164.064 151.513 164.712 ;
     RECT  150.611 188.112 151.573 188.232 ;
     RECT  150.581 176.16 151.585 176.424 ;
     RECT  150.761 189.264 151.619 191.256 ;
     RECT  151.585 176.16 151.621 176.52 ;
     RECT  151.441 226.08 151.625 226.296 ;
     RECT  150.419 156.864 151.657 157.368 ;
     RECT  151.513 154.032 151.661 155.304 ;
     RECT  150.509 159.12 151.661 159.24 ;
     RECT  150.901 165.84 151.661 173.544 ;
     RECT  151.157 185.808 151.661 186.456 ;
     RECT  150.467 136.944 151.697 136.968 ;
     RECT  151.661 185.808 151.697 186.36 ;
     RECT  151.085 208.8 151.697 208.824 ;
     RECT  151.441 194.112 151.715 194.568 ;
     RECT  151.573 187.536 151.733 188.232 ;
     RECT  151.049 210.912 151.733 210.936 ;
     RECT  150.797 140.592 151.765 140.616 ;
     RECT  151.765 140.592 151.805 140.808 ;
     RECT  151.625 226.176 151.877 226.296 ;
     RECT  151.225 215.664 151.909 215.688 ;
     RECT  151.301 217.728 151.909 218.232 ;
     RECT  151.697 185.808 151.913 185.88 ;
     RECT  151.405 219.408 151.913 220.536 ;
     RECT  151.621 175.728 151.945 176.52 ;
     RECT  151.193 177.552 151.945 180.072 ;
     RECT  150.509 146.448 151.981 146.472 ;
     RECT  151.661 154.656 151.981 155.304 ;
     RECT  151.945 175.728 151.981 180.072 ;
     RECT  151.909 217.296 151.996 218.232 ;
     RECT  151.229 181.44 152.017 182.376 ;
     RECT  151.117 212.976 152.017 213 ;
     RECT  151.513 160.416 152.051 164.712 ;
     RECT  151.481 204.576 152.053 204.936 ;
     RECT  152.051 160.464 152.06 164.712 ;
     RECT  151.981 154.656 152.065 155.544 ;
     RECT  151.157 184.656 152.089 184.776 ;
     RECT  152.053 204.576 152.099 205.56 ;
     RECT  152.017 212.64 152.101 213 ;
     RECT  152.089 184.272 152.125 184.776 ;
     RECT  152.065 154.656 152.129 155.304 ;
     RECT  151.909 215.28 152.129 216.216 ;
     RECT  151.981 175.44 152.149 180.072 ;
     RECT  151.228 201.696 152.156 201.768 ;
     RECT  152.089 202.944 152.156 202.968 ;
     RECT  151.913 185.808 152.195 185.832 ;
     RECT  151.733 188.208 152.197 188.232 ;
     RECT  151.619 189.264 152.197 190.296 ;
     RECT  152.149 175.344 152.233 180.072 ;
     RECT  151.297 149.088 152.237 149.112 ;
     RECT  152.101 212.928 152.237 213 ;
     RECT  151.913 219.456 152.237 220.536 ;
     RECT  152.125 226.32 152.237 226.344 ;
     RECT  152.197 188.208 152.243 190.296 ;
     RECT  152.156 201.696 152.243 202.968 ;
     RECT  150.941 193.008 152.293 193.032 ;
     RECT  151.715 194.112 152.293 194.136 ;
     RECT  151.981 145.968 152.305 146.472 ;
     RECT  151.265 147.6 152.305 147.624 ;
     RECT  152.243 188.208 152.345 189.288 ;
     RECT  152.293 192.624 152.38 194.136 ;
     RECT  152.233 175.344 152.381 180.168 ;
     RECT  152.38 192.624 152.381 192.648 ;
     RECT  151.661 166.368 152.413 173.544 ;
     RECT  152.381 175.344 152.413 176.568 ;
     RECT  152.099 205.536 152.413 205.56 ;
     RECT  151.153 207.456 152.413 207.48 ;
     RECT  151.091 196.512 152.437 198.12 ;
     RECT  151.187 199.488 152.437 199.512 ;
     RECT  152.341 227.952 152.453 227.976 ;
     RECT  152.243 201.696 152.483 201.72 ;
     RECT  151.805 140.784 152.521 140.808 ;
     RECT  151.729 214.272 152.557 214.296 ;
     RECT  152.129 215.28 152.557 215.64 ;
     RECT  152.381 177.552 152.593 180.168 ;
     RECT  152.017 181.44 152.593 182.424 ;
     RECT  152.521 140.784 152.605 141.336 ;
     RECT  152.605 140.784 152.633 140.808 ;
     RECT  152.06 160.464 152.665 165.144 ;
     RECT  150.553 152.16 152.701 152.184 ;
     RECT  152.437 196.512 152.737 199.512 ;
     RECT  150.947 144.336 152.773 144.36 ;
     RECT  151.657 156.768 152.773 157.368 ;
     RECT  152.737 196.368 152.773 199.512 ;
     RECT  152.125 184.176 152.809 184.776 ;
     RECT  152.773 158.4 152.917 158.424 ;
     RECT  152.593 195.264 152.989 195.288 ;
     RECT  152.773 196.368 152.989 199.992 ;
     RECT  152.917 158.4 153.013 159.24 ;
     RECT  152.809 184.176 153.097 184.824 ;
     RECT  152.345 188.208 153.133 189.096 ;
     RECT  152.665 160.464 153.205 165.192 ;
     RECT  152.413 166.368 153.205 176.568 ;
     RECT  152.701 151.584 153.253 152.184 ;
     RECT  152.305 145.968 153.313 147.624 ;
     RECT  152.243 190.272 153.313 190.296 ;
     RECT  153.313 145.968 153.349 147.768 ;
     RECT  153.277 148.896 153.349 148.92 ;
     RECT  153.205 160.464 153.349 176.568 ;
     RECT  152.593 177.552 153.349 182.424 ;
     RECT  153.308 223.536 153.349 223.56 ;
     RECT  153.349 145.968 153.385 148.92 ;
     RECT  152.773 144.288 153.445 144.36 ;
     RECT  152.129 154.656 153.445 154.68 ;
     RECT  153.445 143.856 153.493 144.36 ;
     RECT  153.097 184.032 153.493 184.824 ;
     RECT  153.097 186.48 153.565 186.504 ;
     RECT  153.133 187.488 153.565 189.096 ;
     RECT  152.38 194.112 153.565 194.136 ;
     RECT  152.989 195.264 153.565 199.992 ;
     RECT  152.237 212.928 153.565 212.952 ;
     RECT  153.349 142.8 153.608 142.824 ;
     RECT  153.493 143.856 153.608 144.552 ;
     RECT  153.385 145.92 153.608 148.92 ;
     RECT  152.485 149.904 153.608 149.928 ;
     RECT  153.253 151.584 153.608 153.528 ;
     RECT  153.445 154.56 153.608 154.68 ;
     RECT  152.773 156.72 153.608 157.368 ;
     RECT  153.013 158.4 153.608 159.288 ;
     RECT  153.349 160.464 153.608 182.424 ;
     RECT  153.493 183.984 153.608 184.824 ;
     RECT  153.565 186.48 153.608 189.096 ;
     RECT  153.313 190.272 153.608 190.44 ;
     RECT  153.241 192.096 153.608 192.12 ;
     RECT  153.565 194.112 153.608 199.992 ;
     RECT  152.413 205.536 153.608 207.48 ;
     RECT  153.097 211.248 153.608 211.272 ;
     RECT  153.565 212.88 153.608 212.952 ;
     RECT  152.557 214.272 153.608 215.64 ;
     RECT  151.996 218.064 153.608 218.232 ;
     RECT  152.237 219.456 153.608 220.152 ;
     RECT  153.349 223.536 153.608 223.752 ;
     RECT  153.608 2.148 153.712 369.372 ;
     RECT  153.712 2.418 153.904 369.102 ;
     RECT  153.904 175.152 153.965 182.376 ;
     RECT  153.904 199.056 153.965 199.992 ;
     RECT  153.904 156.72 154.001 156.984 ;
     RECT  153.904 168.096 154.001 168.84 ;
     RECT  153.904 160.752 154.037 166.488 ;
     RECT  153.904 183.984 154.037 185.448 ;
     RECT  153.904 186.48 154.037 190.968 ;
     RECT  153.965 199.056 154.037 199.464 ;
     RECT  153.904 192.096 154.073 192.12 ;
     RECT  153.904 147.744 154.109 147.768 ;
     RECT  153.904 169.968 154.109 173.544 ;
     RECT  154.037 190.704 154.109 190.968 ;
     RECT  153.904 144.528 154.163 144.552 ;
     RECT  153.904 145.92 154.217 145.944 ;
     RECT  153.904 158.4 154.253 159.24 ;
     RECT  153.904 208.608 154.253 208.632 ;
     RECT  153.904 148.8 154.289 148.92 ;
     RECT  154.001 156.72 154.325 156.744 ;
     RECT  154.109 169.968 154.325 173.496 ;
     RECT  153.904 153.504 154.361 155.592 ;
     RECT  154.037 184.032 154.397 185.448 ;
     RECT  154.037 160.752 154.505 166.248 ;
     RECT  153.965 175.152 154.541 179.976 ;
     RECT  154.361 153.936 154.649 155.592 ;
     RECT  154.541 177.552 154.649 179.976 ;
     RECT  154.037 186.48 154.649 189.72 ;
     RECT  154.649 187.488 154.685 189.72 ;
     RECT  153.904 203.376 154.685 203.4 ;
     RECT  154.649 186.48 154.793 186.504 ;
     RECT  154.397 184.032 154.829 184.872 ;
     RECT  154.505 161.76 154.865 164.52 ;
     RECT  153.904 205.536 154.969 205.56 ;
     RECT  154.001 168.096 154.973 168.12 ;
     RECT  154.685 188.496 154.973 189.72 ;
     RECT  153.904 211.248 154.973 214.824 ;
     RECT  153.904 194.784 155.009 194.808 ;
     RECT  153.904 215.856 155.081 216.792 ;
     RECT  154.649 153.984 155.117 155.592 ;
     RECT  155.117 154.56 155.153 155.592 ;
     RECT  154.933 196.368 155.153 196.392 ;
     RECT  153.904 209.952 155.153 209.976 ;
     RECT  154.973 211.248 155.153 214.44 ;
     RECT  154.685 187.488 155.315 187.512 ;
     RECT  153.904 218.064 155.329 218.088 ;
     RECT  155.153 213.072 155.333 214.44 ;
     RECT  153.904 219.264 155.333 219.288 ;
     RECT  154.865 163.152 155.369 164.52 ;
     RECT  155.333 213.072 155.405 213.912 ;
     RECT  154.289 148.8 155.473 148.824 ;
     RECT  154.969 205.536 155.477 205.896 ;
     RECT  155.369 164.304 155.509 164.52 ;
     RECT  154.505 165.552 155.509 166.248 ;
     RECT  155.473 148.176 155.513 148.824 ;
     RECT  155.405 213.072 155.513 213.816 ;
     RECT  154.505 160.752 155.516 160.776 ;
     RECT  154.865 161.76 155.516 161.88 ;
     RECT  155.516 160.752 155.557 161.88 ;
     RECT  154.253 158.4 155.564 159.192 ;
     RECT  155.557 160.656 155.603 161.88 ;
     RECT  153.904 152.496 155.617 152.52 ;
     RECT  155.564 157.872 155.617 159.192 ;
     RECT  155.509 164.304 155.617 166.248 ;
     RECT  154.541 175.152 155.621 176.472 ;
     RECT  155.617 157.872 155.651 159.624 ;
     RECT  154.109 190.944 155.657 190.968 ;
     RECT  153.904 149.904 155.761 150.024 ;
     RECT  155.617 164.304 155.765 166.44 ;
     RECT  154.325 169.968 155.765 172.728 ;
     RECT  155.293 173.904 155.765 173.928 ;
     RECT  155.765 164.496 155.801 166.44 ;
     RECT  155.621 175.152 155.833 176.376 ;
     RECT  153.965 181.632 155.833 182.376 ;
     RECT  155.749 151.392 155.836 151.416 ;
     RECT  155.801 164.496 155.837 165.432 ;
     RECT  155.329 217.68 155.873 218.088 ;
     RECT  155.603 160.656 155.891 160.68 ;
     RECT  155.603 161.76 155.905 161.88 ;
     RECT  155.369 163.152 155.905 163.176 ;
     RECT  155.081 215.856 155.909 215.88 ;
     RECT  155.761 149.904 155.941 150.36 ;
     RECT  155.651 158.4 156.017 159.624 ;
     RECT  155.833 175.056 156.049 176.376 ;
     RECT  154.973 188.496 156.049 189.096 ;
     RECT  155.477 205.536 156.053 205.56 ;
     RECT  155.185 156.768 156.085 156.792 ;
     RECT  155.617 152.496 156.089 152.76 ;
     RECT  155.653 208.848 156.089 208.872 ;
     RECT  155.153 154.56 156.121 155.016 ;
     RECT  156.013 147.024 156.133 147.048 ;
     RECT  155.513 148.176 156.133 148.2 ;
     RECT  155.153 211.248 156.133 211.8 ;
     RECT  156.121 154.56 156.157 155.064 ;
     RECT  156.133 147.024 156.179 148.2 ;
     RECT  156.157 154.464 156.181 155.064 ;
     RECT  156.085 203.424 156.181 203.448 ;
     RECT  156.181 203.424 156.188 204.072 ;
     RECT  155.513 213.072 156.189 213.192 ;
     RECT  156.049 210.144 156.193 210.168 ;
     RECT  156.133 211.248 156.193 211.896 ;
     RECT  156.193 210.144 156.197 211.896 ;
     RECT  156.188 203.424 156.227 205.224 ;
     RECT  155.873 218.064 156.229 218.088 ;
     RECT  156.179 147.744 156.233 147.768 ;
     RECT  156.197 210.624 156.233 211.896 ;
     RECT  156.157 192.24 156.265 192.264 ;
     RECT  156.049 188.496 156.269 189.864 ;
     RECT  156.227 204.048 156.269 205.224 ;
     RECT  156.233 210.624 156.269 211.272 ;
     RECT  156.269 204.624 156.275 205.224 ;
     RECT  155.941 149.52 156.341 150.36 ;
     RECT  156.089 152.496 156.377 152.52 ;
     RECT  156.193 184.464 156.409 184.488 ;
     RECT  156.409 184.464 156.413 185.064 ;
     RECT  156.265 192.24 156.485 192.648 ;
     RECT  156.485 192.24 156.521 192.264 ;
     RECT  156.341 149.664 156.557 150.36 ;
     RECT  155.905 161.76 156.589 163.176 ;
     RECT  156.085 156.144 156.593 156.792 ;
     RECT  156.275 204.96 156.593 205.224 ;
     RECT  153.904 207.456 156.613 207.48 ;
     RECT  156.413 184.704 156.629 185.064 ;
     RECT  156.613 207.456 156.659 208.248 ;
     RECT  156.229 218.064 156.665 218.856 ;
     RECT  156.659 208.224 156.7 208.248 ;
     RECT  155.833 181.632 156.701 182.616 ;
     RECT  156.049 174.288 156.733 176.376 ;
     RECT  155.869 220.08 156.733 220.104 ;
     RECT  156.625 221.76 156.733 221.784 ;
     RECT  155.801 166.416 156.773 166.44 ;
     RECT  156.189 213.168 156.773 213.192 ;
     RECT  156.445 214.32 156.773 214.344 ;
     RECT  155.837 165.072 156.841 165.432 ;
     RECT  156.733 174.288 156.845 176.568 ;
     RECT  156.269 210.624 156.845 210.648 ;
     RECT  156.301 201.216 156.989 201.24 ;
     RECT  156.181 154.32 157.025 155.064 ;
     RECT  156.665 218.832 157.057 218.856 ;
     RECT  156.733 220.08 157.057 221.784 ;
     RECT  157.057 218.832 157.097 221.784 ;
     RECT  157.025 154.464 157.133 155.064 ;
     RECT  156.629 184.704 157.133 184.728 ;
     RECT  157.141 193.68 157.228 193.704 ;
     RECT  156.265 168.432 157.273 168.456 ;
     RECT  157.121 194.928 157.309 194.952 ;
     RECT  157.097 219.408 157.331 221.784 ;
     RECT  156.593 156.768 157.333 156.792 ;
     RECT  156.589 161.76 157.345 163.272 ;
     RECT  157.333 156.768 157.379 157.608 ;
     RECT  157.345 161.424 157.385 163.272 ;
     RECT  156.841 165.072 157.385 165.912 ;
     RECT  156.845 174.288 157.417 174.312 ;
     RECT  157.379 157.296 157.421 157.608 ;
     RECT  155.765 171.12 157.453 172.728 ;
     RECT  157.331 220.08 157.457 220.104 ;
     RECT  157.273 168.432 157.489 168.504 ;
     RECT  154.037 199.056 157.489 199.08 ;
     RECT  156.593 204.96 157.529 204.984 ;
     RECT  156.701 181.632 157.561 181.656 ;
     RECT  157.309 194.928 157.561 195.576 ;
     RECT  157.333 158.592 157.564 158.616 ;
     RECT  157.489 168.384 157.601 168.504 ;
     RECT  157.58 163.776 157.621 163.8 ;
     RECT  157.385 165.072 157.621 165.336 ;
     RECT  157.331 221.76 157.637 221.784 ;
     RECT  157.621 163.776 157.667 165.336 ;
     RECT  157.601 168.432 157.669 168.504 ;
     RECT  157.561 194.064 157.705 195.576 ;
     RECT  156.949 190.512 157.717 190.536 ;
     RECT  157.667 163.968 157.745 165.336 ;
     RECT  156.845 175.584 157.745 176.568 ;
     RECT  156.269 188.496 157.763 189 ;
     RECT  157.717 190.512 157.804 190.968 ;
     RECT  155.765 169.968 157.813 169.992 ;
     RECT  157.453 171.12 157.813 173.016 ;
     RECT  157.804 190.512 157.813 190.824 ;
     RECT  156.017 159.6 157.849 159.624 ;
     RECT  157.385 161.424 157.849 162.648 ;
     RECT  157.763 188.496 157.921 188.712 ;
     RECT  157.705 194.064 157.961 195.864 ;
     RECT  157.849 159.6 158.101 160.2 ;
     RECT  157.813 169.968 158.137 173.016 ;
     RECT  157.961 194.064 158.197 194.28 ;
     RECT  157.633 192.576 158.245 192.6 ;
     RECT  158.197 193.776 158.245 194.28 ;
     RECT  158.137 169.872 158.317 173.016 ;
     RECT  158.173 203.232 158.381 203.256 ;
     RECT  157.961 195.504 158.389 195.864 ;
     RECT  157.669 168.432 158.425 168.696 ;
     RECT  158.317 169.68 158.425 173.016 ;
     RECT  157.417 174 158.425 174.312 ;
     RECT  154.649 177.552 158.461 179.352 ;
     RECT  157.421 157.296 158.533 157.32 ;
     RECT  157.561 180.672 158.569 181.656 ;
     RECT  158.569 180.672 158.629 182.232 ;
     RECT  158.245 192.576 158.629 194.28 ;
     RECT  157.597 185.808 158.677 186.36 ;
     RECT  158.101 159.456 158.713 160.2 ;
     RECT  158.533 157.296 158.749 158.088 ;
     RECT  158.713 159.36 158.749 160.2 ;
     RECT  158.425 166.224 158.785 166.248 ;
     RECT  158.629 192.384 158.821 194.28 ;
     RECT  158.497 200.448 158.828 200.472 ;
     RECT  157.489 198.384 158.869 199.08 ;
     RECT  158.828 200.064 158.869 200.472 ;
     RECT  158.425 168.432 158.893 173.016 ;
     RECT  158.425 174 158.893 174.36 ;
     RECT  158.677 214.464 158.965 214.488 ;
     RECT  157.133 154.896 159.008 155.064 ;
     RECT  158.749 157.296 159.008 160.2 ;
     RECT  157.849 161.232 159.008 162.648 ;
     RECT  157.745 163.968 159.008 165.144 ;
     RECT  158.785 166.224 159.008 166.536 ;
     RECT  158.893 168.432 159.008 174.36 ;
     RECT  157.745 175.584 159.008 176.376 ;
     RECT  158.461 177.456 159.008 179.352 ;
     RECT  158.629 180.672 159.008 182.328 ;
     RECT  158.677 185.664 159.008 186.36 ;
     RECT  157.921 187.728 159.008 188.712 ;
     RECT  157.813 190.368 159.008 190.824 ;
     RECT  158.821 192.096 159.008 194.28 ;
     RECT  158.389 195.504 159.008 195.96 ;
     RECT  157.417 196.992 159.008 197.016 ;
     RECT  158.869 198.384 159.008 200.472 ;
     RECT  158.381 202.32 159.008 203.256 ;
     RECT  158.341 204.336 159.008 204.36 ;
     RECT  158.317 206.256 159.008 206.28 ;
     RECT  158.389 208.656 159.008 208.68 ;
     RECT  158.893 211.056 159.008 211.08 ;
     RECT  158.173 212.064 159.008 212.664 ;
     RECT  158.965 214.272 159.008 214.488 ;
     RECT  159.008 2.148 159.112 369.372 ;
     RECT  159.112 2.418 159.304 369.102 ;
     RECT  159.304 162.144 159.329 166.536 ;
     RECT  159.329 165.12 159.365 166.536 ;
     RECT  159.365 165.408 159.401 166.536 ;
     RECT  159.304 197.856 159.401 200.712 ;
     RECT  159.304 182.88 159.437 183 ;
     RECT  159.304 187.296 159.437 188.616 ;
     RECT  159.304 203.568 159.506 204.936 ;
     RECT  159.304 213.888 159.509 214.488 ;
     RECT  159.509 213.888 159.545 213.912 ;
     RECT  159.304 160.032 159.581 160.2 ;
     RECT  159.506 203.568 159.587 204.84 ;
     RECT  159.329 162.144 159.617 163.992 ;
     RECT  159.304 207.456 159.617 208.536 ;
     RECT  159.304 168.672 159.635 176.232 ;
     RECT  159.304 180.672 159.635 181.656 ;
     RECT  159.635 168.672 159.653 175.32 ;
     RECT  159.304 177.456 159.653 179.352 ;
     RECT  159.437 182.976 159.653 183 ;
     RECT  159.304 195.936 159.797 196.728 ;
     RECT  159.401 197.856 159.797 198.408 ;
     RECT  159.617 162.144 159.869 162.456 ;
     RECT  159.617 207.84 159.875 208.536 ;
     RECT  159.875 208.416 159.905 208.536 ;
     RECT  159.905 208.416 159.913 208.44 ;
     RECT  159.653 168.672 159.923 174.264 ;
     RECT  159.304 191.376 159.923 192.984 ;
     RECT  159.304 210.912 159.923 210.936 ;
     RECT  159.304 167.568 159.941 167.592 ;
     RECT  159.797 195.936 159.941 195.96 ;
     RECT  159.923 168.816 160.121 174.264 ;
     RECT  159.304 185.376 160.121 185.832 ;
     RECT  159.923 191.376 160.163 191.4 ;
     RECT  159.304 206.064 160.163 206.088 ;
     RECT  159.587 204.816 160.193 204.84 ;
     RECT  159.437 187.44 160.337 187.464 ;
     RECT  159.923 192.96 160.46 192.984 ;
     RECT  159.797 197.856 160.501 197.88 ;
     RECT  159.401 165.408 160.508 166.248 ;
     RECT  160.508 202.176 160.513 202.2 ;
     RECT  160.46 192.96 160.517 193.08 ;
     RECT  160.517 193.056 160.547 193.08 ;
     RECT  159.401 199.44 160.549 200.712 ;
     RECT  160.513 202.176 160.549 202.392 ;
     RECT  159.587 203.568 160.549 203.736 ;
     RECT  160.508 165.024 160.553 166.248 ;
     RECT  159.617 163.44 160.595 163.992 ;
     RECT  160.553 165.024 160.595 165.192 ;
     RECT  160.549 199.44 160.595 203.736 ;
     RECT  159.653 177.552 160.621 179.352 ;
     RECT  160.121 185.376 160.661 185.4 ;
     RECT  160.553 166.224 160.693 166.248 ;
     RECT  160.595 199.44 160.697 202.824 ;
     RECT  160.121 174.24 160.729 174.264 ;
     RECT  159.653 175.296 160.729 175.32 ;
     RECT  160.697 199.44 160.805 201.624 ;
     RECT  160.697 202.8 160.805 202.824 ;
     RECT  160.501 197.232 160.877 197.88 ;
     RECT  160.121 168.816 160.949 172.728 ;
     RECT  160.877 197.856 160.985 197.88 ;
     RECT  160.729 174.24 161.233 175.32 ;
     RECT  159.581 160.176 161.317 160.2 ;
     RECT  161.317 160.176 161.413 160.728 ;
     RECT  159.869 162.144 161.413 162.168 ;
     RECT  160.949 170.16 161.461 172.728 ;
     RECT  161.233 174.144 161.507 175.32 ;
     RECT  161.507 174.24 161.509 175.32 ;
     RECT  160.621 176.688 161.509 179.352 ;
     RECT  161.461 170.16 161.548 173.16 ;
     RECT  161.509 174.24 161.555 179.352 ;
     RECT  161.555 175.296 161.561 175.944 ;
     RECT  161.561 175.536 161.596 175.944 ;
     RECT  161.413 160.176 161.633 162.168 ;
     RECT  160.949 168.816 161.633 168.984 ;
     RECT  161.633 161.376 161.813 162.168 ;
     RECT  160.595 163.488 161.845 163.992 ;
     RECT  161.813 161.472 161.849 162.168 ;
     RECT  161.548 170.16 161.921 172.728 ;
     RECT  161.555 174.24 161.921 174.264 ;
     RECT  160.693 166.224 161.941 166.536 ;
     RECT  161.849 162.144 161.949 162.168 ;
     RECT  161.596 175.92 161.993 175.944 ;
     RECT  161.845 163.2 162.025 163.992 ;
     RECT  161.941 166.224 162.028 167.016 ;
     RECT  162.025 162.48 162.029 163.992 ;
     RECT  162.028 166.224 162.065 166.248 ;
     RECT  162.029 163.488 162.133 163.992 ;
     RECT  160.595 165.072 162.133 165.192 ;
     RECT  162.133 163.488 162.229 165.192 ;
     RECT  162.229 163.488 162.275 165.432 ;
     RECT  162.275 163.488 162.281 163.512 ;
     RECT  162.275 164.88 162.316 165.432 ;
     RECT  162.316 164.88 162.389 165.192 ;
     RECT  162.029 162.48 162.425 162.504 ;
     RECT  162.389 165.072 162.569 165.192 ;
     RECT  162.569 165.168 162.929 165.192 ;
     RECT  161.921 170.976 163.181 172.728 ;
     RECT  161.633 168.816 163.361 168.84 ;
     RECT  163.181 171.12 164.408 172.728 ;
     RECT  161.555 177.552 164.408 179.352 ;
     RECT  159.635 181.632 164.408 181.656 ;
     RECT  164.408 2.148 164.512 369.372 ;
     RECT  164.512 2.418 164.704 369.102 ;
     RECT  164.704 171.12 169.808 172.728 ;
     RECT  164.704 177.552 169.808 179.352 ;
     RECT  164.704 181.632 169.808 181.656 ;
     RECT  169.808 2.148 169.912 369.372 ;
     RECT  169.912 2.418 170.104 369.102 ;
     RECT  170.104 171.12 175.208 172.728 ;
     RECT  170.104 177.552 175.208 179.352 ;
     RECT  170.104 181.632 175.208 181.656 ;
     RECT  175.208 2.148 175.312 369.372 ;
     RECT  175.312 2.418 175.504 369.102 ;
     RECT  175.504 171.12 180.608 172.728 ;
     RECT  175.504 177.552 180.608 179.352 ;
     RECT  175.504 181.632 180.608 181.656 ;
     RECT  180.608 2.148 180.712 369.372 ;
     RECT  180.712 2.418 180.904 369.102 ;
     RECT  180.904 171.12 186.008 172.728 ;
     RECT  180.904 177.552 186.008 179.352 ;
     RECT  180.904 181.632 186.008 181.656 ;
     RECT  186.008 2.148 186.112 369.372 ;
     RECT  186.112 2.418 186.304 369.102 ;
     RECT  186.304 171.12 191.408 172.728 ;
     RECT  186.304 177.552 191.408 179.352 ;
     RECT  186.304 181.632 191.408 181.656 ;
     RECT  191.408 2.148 191.512 369.372 ;
     RECT  191.512 2.418 191.704 369.102 ;
     RECT  191.704 171.12 196.808 172.728 ;
     RECT  191.704 177.552 196.808 179.352 ;
     RECT  191.704 181.632 196.808 181.656 ;
     RECT  196.808 2.148 196.912 369.372 ;
     RECT  196.912 2.418 197.104 369.102 ;
     RECT  197.104 171.12 202.208 172.728 ;
     RECT  197.104 177.552 202.208 179.352 ;
     RECT  197.104 181.632 202.208 181.656 ;
     RECT  202.208 2.148 202.312 369.372 ;
     RECT  202.312 2.418 202.504 369.102 ;
     RECT  202.504 171.12 207.608 172.728 ;
     RECT  202.504 177.552 207.608 179.352 ;
     RECT  202.504 181.632 207.608 181.656 ;
     RECT  207.608 2.148 207.712 369.372 ;
     RECT  207.712 2.418 207.904 369.102 ;
     RECT  207.904 171.12 213.008 172.728 ;
     RECT  207.904 177.552 213.008 179.352 ;
     RECT  207.904 181.632 213.008 181.656 ;
     RECT  213.008 2.148 213.112 369.372 ;
     RECT  213.112 2.418 213.304 369.102 ;
     RECT  213.304 171.12 218.408 172.728 ;
     RECT  213.304 177.552 218.408 179.352 ;
     RECT  213.304 181.632 218.408 181.656 ;
     RECT  218.408 2.148 218.512 369.372 ;
     RECT  218.512 2.418 218.704 369.102 ;
     RECT  218.704 171.12 223.808 172.728 ;
     RECT  218.704 177.552 223.808 179.352 ;
     RECT  218.704 181.632 223.808 181.656 ;
     RECT  223.808 2.148 223.912 369.372 ;
     RECT  223.912 2.418 224.104 369.102 ;
     RECT  224.104 171.12 229.208 172.728 ;
     RECT  224.104 177.552 229.208 179.352 ;
     RECT  224.104 181.632 229.208 181.656 ;
     RECT  229.208 2.148 229.312 369.372 ;
     RECT  229.312 2.418 229.504 369.102 ;
     RECT  229.504 171.12 234.608 172.728 ;
     RECT  229.504 177.552 234.608 179.352 ;
     RECT  229.504 181.632 234.608 181.656 ;
     RECT  234.608 2.148 234.712 369.372 ;
     RECT  234.712 2.418 234.904 369.102 ;
     RECT  234.904 171.12 238.457 172.728 ;
     RECT  238.457 171.264 240.008 172.728 ;
     RECT  234.904 177.552 240.008 179.352 ;
     RECT  234.904 181.632 240.008 181.656 ;
     RECT  240.008 2.148 240.112 369.372 ;
     RECT  240.112 2.418 240.304 369.102 ;
     RECT  240.304 171.264 242.561 172.728 ;
     RECT  242.561 171.36 243.533 172.728 ;
     RECT  243.533 172.128 243.965 172.728 ;
     RECT  243.965 172.704 245.408 172.728 ;
     RECT  240.304 177.552 245.408 179.352 ;
     RECT  240.304 181.632 245.408 181.656 ;
     RECT  245.408 2.148 245.512 369.372 ;
     RECT  245.512 2.418 245.704 369.102 ;
     RECT  245.704 170.832 246.697 172.584 ;
     RECT  246.697 170.64 246.733 172.584 ;
     RECT  246.733 170.352 246.769 172.584 ;
     RECT  245.704 178.512 246.769 178.536 ;
     RECT  246.769 178.416 246.805 178.536 ;
     RECT  246.805 178.32 247.309 178.536 ;
     RECT  247.309 178.32 247.345 178.824 ;
     RECT  247.345 178.224 247.381 178.824 ;
     RECT  246.769 169.68 248.364 172.68 ;
     RECT  247.381 178.128 248.364 178.824 ;
    LAYER M5 ;
     RECT  2.4 2.137 2.52 2.151 ;
     RECT  7.8 2.137 7.92 2.151 ;
     RECT  13.2 2.137 13.32 2.151 ;
     RECT  18.6 2.137 18.72 2.151 ;
     RECT  24 2.137 24.12 2.151 ;
     RECT  29.4 2.137 29.52 2.151 ;
     RECT  34.8 2.137 34.92 2.151 ;
     RECT  40.2 2.137 40.32 2.151 ;
     RECT  45.6 2.137 45.72 2.151 ;
     RECT  51 2.137 51.12 2.151 ;
     RECT  56.4 2.137 56.52 2.151 ;
     RECT  61.8 2.137 61.92 2.151 ;
     RECT  67.2 2.137 67.32 2.151 ;
     RECT  72.6 2.137 72.72 2.151 ;
     RECT  78 2.137 78.12 2.151 ;
     RECT  83.4 2.137 83.52 2.151 ;
     RECT  88.8 2.137 88.92 2.151 ;
     RECT  94.2 2.137 94.32 2.151 ;
     RECT  99.6 2.137 99.72 2.151 ;
     RECT  105 2.137 105.12 2.151 ;
     RECT  110.4 2.137 110.52 2.151 ;
     RECT  115.8 2.137 115.92 2.151 ;
     RECT  121.2 2.137 121.32 2.151 ;
     RECT  126.6 2.137 126.72 2.151 ;
     RECT  132 2.137 132.12 2.151 ;
     RECT  137.4 2.137 137.52 2.151 ;
     RECT  142.8 2.137 142.92 2.151 ;
     RECT  148.2 2.137 148.32 2.151 ;
     RECT  153.6 2.137 153.72 2.151 ;
     RECT  159 2.137 159.12 2.151 ;
     RECT  164.4 2.137 164.52 2.151 ;
     RECT  169.8 2.137 169.92 2.151 ;
     RECT  175.2 2.137 175.32 2.151 ;
     RECT  180.6 2.137 180.72 2.151 ;
     RECT  186 2.137 186.12 2.151 ;
     RECT  191.4 2.137 191.52 2.151 ;
     RECT  196.8 2.137 196.92 2.151 ;
     RECT  202.2 2.137 202.32 2.151 ;
     RECT  207.6 2.137 207.72 2.151 ;
     RECT  213 2.137 213.12 2.151 ;
     RECT  218.4 2.137 218.52 2.151 ;
     RECT  223.8 2.137 223.92 2.151 ;
     RECT  229.2 2.137 229.32 2.151 ;
     RECT  234.6 2.137 234.72 2.151 ;
     RECT  240 2.137 240.12 2.151 ;
     RECT  245.4 2.137 245.52 2.151 ;
     RECT  142.8 2.151 143.112 127.237 ;
     RECT  145.776 128.197 145.8 129.925 ;
     RECT  145.008 129.925 145.8 129.971 ;
     RECT  137.4 2.151 137.712 130.309 ;
     RECT  135.984 129.925 136.008 130.355 ;
     RECT  148.2 2.151 148.512 130.501 ;
     RECT  145.008 129.971 145.032 130.595 ;
     RECT  142.128 127.237 143.112 131.075 ;
     RECT  139.632 129.397 139.656 131.365 ;
     RECT  139.104 131.365 139.656 131.411 ;
     RECT  142.464 131.075 143.112 131.605 ;
     RECT  142.464 131.605 143.976 131.987 ;
     RECT  147.84 130.501 148.512 132.083 ;
     RECT  137.4 130.309 137.832 132.469 ;
     RECT  139.104 131.411 139.128 132.469 ;
     RECT  137.4 132.469 139.128 132.851 ;
     RECT  142.704 131.987 143.976 134.005 ;
     RECT  136.224 133.189 136.248 134.243 ;
     RECT  142.608 134.005 143.976 134.339 ;
     RECT  142.8 134.339 143.976 134.533 ;
     RECT  142.8 134.533 144.36 135.445 ;
     RECT  141.504 134.869 141.528 135.683 ;
     RECT  135.504 135.061 135.528 135.731 ;
     RECT  132 2.151 132.312 135.973 ;
     RECT  133.968 134.629 133.992 136.451 ;
     RECT  148.2 132.083 148.512 137.317 ;
     RECT  137.4 132.851 138.888 137.651 ;
     RECT  132 135.973 132.408 137.845 ;
     RECT  140.784 135.733 140.808 138.083 ;
     RECT  150.432 137.893 150.456 138.421 ;
     RECT  150.048 138.421 150.456 138.467 ;
     RECT  142.8 135.445 144.744 138.563 ;
     RECT  136.032 136.693 136.056 138.611 ;
     RECT  150.048 138.467 150.072 139.139 ;
     RECT  132 137.845 132.648 139.715 ;
     RECT  148.08 137.317 148.512 140.101 ;
     RECT  150 139.621 150.024 140.101 ;
     RECT  138.864 137.651 138.888 140.197 ;
     RECT  140.832 138.997 140.856 140.243 ;
     RECT  150 140.101 150.552 140.243 ;
     RECT  142.8 138.563 144.408 140.435 ;
     RECT  132 139.715 132.312 140.725 ;
     RECT  147.648 140.101 148.512 140.819 ;
     RECT  150.528 140.243 150.552 140.819 ;
     RECT  138.864 140.197 139.176 141.731 ;
     RECT  137.4 137.651 137.712 141.925 ;
     RECT  132 140.725 133.224 142.067 ;
     RECT  134.4 141.925 134.424 142.547 ;
     RECT  148.2 140.819 148.512 142.741 ;
     RECT  152.544 141.301 152.568 142.789 ;
     RECT  153.6 2.151 153.912 142.789 ;
     RECT  148.2 142.741 149.304 142.933 ;
     RECT  136.752 141.925 137.712 143.605 ;
     RECT  141.12 142.453 141.144 143.941 ;
     RECT  142.8 140.435 144.36 143.941 ;
     RECT  132 142.067 132.648 143.987 ;
     RECT  147.456 142.933 149.304 144.035 ;
     RECT  141.12 143.941 144.36 144.275 ;
     RECT  145.776 143.509 145.8 144.275 ;
     RECT  147.456 144.035 148.512 144.325 ;
     RECT  150.624 142.165 150.648 144.373 ;
     RECT  152.544 142.789 153.912 144.517 ;
     RECT  141.12 144.275 141.144 144.803 ;
     RECT  132 143.987 132.312 145.285 ;
     RECT  150.624 144.373 150.936 145.427 ;
     RECT  134.496 145.141 134.52 145.907 ;
     RECT  136.56 143.605 137.712 145.907 ;
     RECT  142.272 144.275 144.36 146.245 ;
     RECT  136.752 145.907 137.712 146.531 ;
     RECT  146.832 144.325 148.512 146.821 ;
     RECT  152.544 144.517 154.152 146.917 ;
     RECT  131.664 145.285 132.312 147.107 ;
     RECT  146.736 146.821 148.512 147.155 ;
     RECT  146.736 147.155 146.76 148.067 ;
     RECT  133.824 146.245 133.848 148.163 ;
     RECT  156.144 147.013 156.168 148.211 ;
     RECT  141.936 146.245 144.36 148.307 ;
     RECT  137.4 146.531 137.712 148.645 ;
     RECT  135.36 147.829 135.384 148.835 ;
     RECT  140.352 146.245 140.376 148.835 ;
     RECT  142.272 148.307 144.36 149.845 ;
     RECT  152.496 146.917 154.152 149.939 ;
     RECT  142.176 149.845 144.36 150.325 ;
     RECT  147.744 147.155 148.512 150.371 ;
     RECT  137.088 148.645 137.712 150.709 ;
     RECT  138.864 141.731 138.888 150.709 ;
     RECT  150.624 145.427 150.648 150.853 ;
     RECT  133.728 150.997 133.752 151.619 ;
     RECT  137.088 150.709 138.888 151.859 ;
     RECT  150.048 150.853 150.648 151.955 ;
     RECT  147.84 150.371 148.512 151.957 ;
     RECT  153.456 149.939 154.152 152.149 ;
     RECT  147.072 151.957 148.512 152.435 ;
     RECT  155.76 151.381 155.784 152.485 ;
     RECT  155.76 152.485 156.216 152.531 ;
     RECT  130.512 152.149 130.536 152.725 ;
     RECT  132 147.107 132.312 152.725 ;
     RECT  133.632 152.101 133.656 152.725 ;
     RECT  137.088 151.859 137.712 152.725 ;
     RECT  133.632 152.725 134.184 152.771 ;
     RECT  140.928 151.573 140.952 152.819 ;
     RECT  150.48 151.955 150.648 153.011 ;
     RECT  142.176 150.325 145.176 153.059 ;
     RECT  146.448 152.725 146.472 153.061 ;
     RECT  146.016 153.061 146.472 153.107 ;
     RECT  134.16 152.771 134.184 153.395 ;
     RECT  130.512 152.725 132.312 153.539 ;
     RECT  136.368 152.725 137.712 153.539 ;
     RECT  153.264 152.149 154.152 153.971 ;
     RECT  146.016 153.107 146.04 154.117 ;
     RECT  142.176 153.059 144.36 154.165 ;
     RECT  145.68 154.117 146.04 154.451 ;
     RECT  147.84 152.435 148.512 154.453 ;
     RECT  153.264 153.971 154.008 154.691 ;
     RECT  141.312 154.165 144.36 154.931 ;
     RECT  156.192 152.531 156.216 155.027 ;
     RECT  136.464 153.539 137.712 155.075 ;
     RECT  150.624 153.011 150.648 155.269 ;
     RECT  141.312 154.931 141.336 155.315 ;
     RECT  138.864 151.859 138.888 155.701 ;
     RECT  142.368 154.931 144.36 156.085 ;
     RECT  137.088 155.075 137.712 156.133 ;
     RECT  145.68 154.451 145.704 156.181 ;
     RECT  147.168 154.453 148.512 156.181 ;
     RECT  145.68 156.181 148.512 156.709 ;
     RECT  152.016 155.509 152.04 156.709 ;
     RECT  153.6 154.691 154.008 156.709 ;
     RECT  150.384 155.269 150.648 157.045 ;
     RECT  159 2.151 159.312 157.285 ;
     RECT  136.224 156.133 137.712 157.379 ;
     RECT  145.68 156.709 148.872 157.907 ;
     RECT  158.832 157.285 159.312 158.197 ;
     RECT  152.016 156.709 154.008 158.435 ;
     RECT  155.616 157.861 155.64 158.435 ;
     RECT  149.904 157.045 150.648 158.483 ;
     RECT  134.352 156.421 134.376 158.531 ;
     RECT  157.344 156.757 157.368 158.581 ;
     RECT  157.344 158.581 157.512 158.627 ;
     RECT  138.864 155.701 139.032 159.011 ;
     RECT  153.024 158.435 154.008 159.155 ;
     RECT  129.984 158.389 130.008 159.539 ;
     RECT  157.488 158.627 157.512 159.589 ;
     RECT  158.784 158.197 159.312 159.589 ;
     RECT  145.68 157.907 148.512 159.635 ;
     RECT  157.488 159.589 159.312 159.635 ;
     RECT  110.4 2.151 110.712 159.733 ;
     RECT  147.168 159.635 148.512 159.781 ;
     RECT  134.304 158.629 134.328 159.973 ;
     RECT  131.184 153.539 132.312 160.117 ;
     RECT  134.304 159.973 134.376 160.117 ;
     RECT  128.784 158.965 128.808 160.163 ;
     RECT  138.864 159.011 138.888 160.165 ;
     RECT  157.872 159.635 159.312 160.211 ;
     RECT  147.168 159.781 148.68 160.307 ;
     RECT  141.648 156.085 144.36 160.357 ;
     RECT  145.68 159.635 146.088 160.357 ;
     RECT  140.16 153.589 140.184 160.405 ;
     RECT  147.168 160.307 148.632 160.451 ;
     RECT  134.304 160.117 134.664 160.501 ;
     RECT  134.304 160.501 134.904 160.595 ;
     RECT  155.856 158.965 155.88 160.645 ;
     RECT  141.648 160.357 146.088 160.691 ;
     RECT  155.568 160.645 155.88 160.691 ;
     RECT  138.864 160.165 139.128 160.693 ;
     RECT  140.16 160.405 140.52 160.693 ;
     RECT  152.016 158.435 152.04 160.693 ;
     RECT  153.024 159.155 153.912 160.693 ;
     RECT  152.016 160.693 153.912 160.739 ;
     RECT  130.752 160.117 132.312 160.835 ;
     RECT  138.864 160.693 140.52 161.219 ;
     RECT  155.568 160.691 155.592 161.363 ;
     RECT  109.968 159.733 110.712 161.509 ;
     RECT  137.088 157.379 137.712 161.605 ;
     RECT  138.864 161.219 140.184 161.605 ;
     RECT  152.112 160.739 153.912 161.843 ;
     RECT  130.752 160.835 130.776 161.893 ;
     RECT  131.904 160.835 132.312 161.893 ;
     RECT  147.168 160.451 148.512 161.893 ;
     RECT  158.16 160.211 159.312 161.893 ;
     RECT  109.488 161.509 110.712 162.035 ;
     RECT  161.328 160.693 161.352 162.133 ;
     RECT  161.328 162.133 161.88 162.179 ;
     RECT  141.648 160.691 144.36 162.325 ;
     RECT  147.168 161.893 148.632 162.373 ;
     RECT  128.448 160.693 128.472 162.421 ;
     RECT  137.088 161.605 140.184 162.421 ;
     RECT  141.312 162.325 144.36 162.421 ;
     RECT  145.68 160.691 146.088 162.421 ;
     RECT  152.352 161.843 153.912 162.421 ;
     RECT  137.088 162.421 146.088 162.517 ;
     RECT  147.168 162.373 148.728 162.613 ;
     RECT  147.168 162.613 148.872 162.709 ;
     RECT  107.424 162.421 107.448 162.899 ;
     RECT  136.8 162.517 146.088 162.949 ;
     RECT  112.272 162.421 112.296 162.997 ;
     RECT  111.744 162.997 112.296 163.043 ;
     RECT  122.832 158.965 122.856 163.043 ;
     RECT  128.208 162.421 128.472 163.043 ;
     RECT  152.352 162.421 154.728 163.381 ;
     RECT  130.752 161.893 132.312 163.427 ;
     RECT  128.448 163.043 128.472 163.525 ;
     RECT  136.128 162.949 146.088 163.765 ;
     RECT  147.168 162.709 149.304 163.765 ;
     RECT  161.856 162.179 161.88 163.909 ;
     RECT  161.856 163.909 162.264 163.955 ;
     RECT  157.632 161.893 159.312 164.003 ;
     RECT  150.624 158.483 150.648 164.149 ;
     RECT  111.744 163.043 111.768 164.243 ;
     RECT  152.16 163.381 154.728 164.531 ;
     RECT  132 163.427 132.312 164.581 ;
     RECT  126.6 2.151 126.912 164.629 ;
     RECT  128.448 163.525 129.384 164.629 ;
     RECT  124.416 162.949 124.44 164.725 ;
     RECT  136.128 163.765 149.304 164.771 ;
     RECT  138.816 164.771 149.304 165.011 ;
     RECT  160.56 163.429 160.584 165.059 ;
     RECT  152.16 164.531 153.912 165.061 ;
     RECT  147.12 165.011 149.304 165.107 ;
     RECT  109.008 163.861 109.032 165.205 ;
     RECT  110.4 162.035 110.712 165.205 ;
     RECT  134.352 160.595 134.904 165.253 ;
     RECT  132 164.581 132.792 165.347 ;
     RECT  157.632 164.003 157.656 165.347 ;
     RECT  162.24 163.955 162.264 165.443 ;
     RECT  147.168 165.107 149.304 165.589 ;
     RECT  109.008 165.205 110.712 165.685 ;
     RECT  126.6 164.629 127.368 165.685 ;
     RECT  128.448 164.629 129.48 165.685 ;
     RECT  134.208 165.253 134.904 165.685 ;
     RECT  136.128 164.771 137.712 165.685 ;
     RECT  126.6 165.685 129.48 165.923 ;
     RECT  124.224 164.725 124.44 166.115 ;
     RECT  152.112 165.061 153.912 166.213 ;
     RECT  134.208 165.685 137.712 166.261 ;
     RECT  138.816 165.011 146.088 166.261 ;
     RECT  152.112 166.213 154.104 166.451 ;
     RECT  109.008 165.685 110.808 166.499 ;
     RECT  126.6 165.923 129.384 166.741 ;
     RECT  125.808 166.741 129.384 166.931 ;
     RECT  150.624 164.149 151.08 166.933 ;
     RECT  125.808 166.931 128.472 167.075 ;
     RECT  113.664 163.573 113.688 167.125 ;
     RECT  113.664 167.125 113.976 167.171 ;
     RECT  153.024 166.451 154.104 167.219 ;
     RECT  150.624 166.933 151.608 167.459 ;
     RECT  130.752 163.427 130.776 167.461 ;
     RECT  113.952 167.171 113.976 167.557 ;
     RECT  134.208 166.261 146.088 167.557 ;
     RECT  109.44 166.499 110.808 167.603 ;
     RECT  125.808 167.075 128.328 167.651 ;
     RECT  126.6 167.651 128.328 167.699 ;
     RECT  126.6 167.699 127.848 168.083 ;
     RECT  132 165.347 132.312 168.085 ;
     RECT  134.208 167.557 146.184 168.277 ;
     RECT  147.168 165.589 149.592 168.277 ;
     RECT  106.608 163.669 106.632 168.659 ;
     RECT  159 164.003 159.312 168.661 ;
     RECT  105 2.151 105.312 168.709 ;
     RECT  109.44 167.603 110.712 168.755 ;
     RECT  112.176 166.933 112.2 168.755 ;
     RECT  153.6 167.219 154.104 168.805 ;
     RECT  161.952 166.981 161.976 168.851 ;
     RECT  113.952 167.557 114.504 169.091 ;
     RECT  123.072 164.677 123.096 169.187 ;
     RECT  134.208 168.277 149.592 169.285 ;
     RECT  150.624 167.459 151.512 169.285 ;
     RECT  104.88 168.709 105.312 169.379 ;
     RECT  129.36 168.037 129.384 169.427 ;
     RECT  124.416 166.115 124.44 169.619 ;
     RECT  130.704 167.461 130.776 169.619 ;
     RECT  121.2 2.151 121.512 169.765 ;
     RECT  153.504 168.805 154.104 169.907 ;
     RECT  132 168.085 132.504 170.005 ;
     RECT  134.208 169.285 151.512 170.147 ;
     RECT  132 170.005 132.744 170.243 ;
     RECT  121.2 169.765 121.992 170.291 ;
     RECT  105 169.379 105.312 170.341 ;
     RECT  113.952 169.091 113.976 170.389 ;
     RECT  124.224 169.765 124.248 170.483 ;
     RECT  110.4 168.755 110.712 170.965 ;
     RECT  126.6 168.083 127.752 170.965 ;
     RECT  106.608 169.765 106.632 171.011 ;
     RECT  132 170.243 132.696 171.253 ;
     RECT  113.424 170.389 113.976 171.395 ;
     RECT  132 171.253 132.792 171.493 ;
     RECT  133.776 170.197 133.8 171.493 ;
     RECT  159 168.661 159.912 171.539 ;
     RECT  123.504 170.965 123.528 171.541 ;
     RECT  130.704 169.619 130.728 171.635 ;
     RECT  123.504 171.541 124.248 171.923 ;
     RECT  132 171.493 133.8 171.973 ;
     RECT  134.88 170.147 151.512 171.973 ;
     RECT  162.096 170.965 162.12 172.117 ;
     RECT  129.264 170.389 129.288 172.309 ;
     RECT  129.168 172.309 129.288 172.355 ;
     RECT  161.472 172.117 162.12 172.403 ;
     RECT  124.224 171.923 124.248 172.595 ;
     RECT  113.952 171.395 113.976 172.645 ;
     RECT  132 171.973 151.512 172.691 ;
     RECT  110.112 170.965 110.712 172.933 ;
     RECT  113.424 172.645 113.976 172.979 ;
     RECT  110.112 172.933 111.528 173.027 ;
     RECT  115.8 2.151 116.112 173.125 ;
     RECT  104.88 170.341 105.312 173.221 ;
     RECT  129.168 172.355 129.192 173.315 ;
     RECT  126.6 170.965 127.992 173.797 ;
     RECT  132 172.691 133.464 173.797 ;
     RECT  134.88 172.691 151.512 173.797 ;
     RECT  125.616 173.797 127.992 173.891 ;
     RECT  104.88 173.221 105.864 173.939 ;
     RECT  161.472 172.403 161.496 174.179 ;
     RECT  132 173.797 151.512 174.325 ;
     RECT  105 173.939 105.864 174.467 ;
     RECT  113.424 172.979 113.448 174.467 ;
     RECT  125.616 173.891 127.032 174.467 ;
     RECT  131.808 174.325 151.512 174.467 ;
     RECT  153.6 169.907 154.104 174.709 ;
     RECT  152.928 174.709 154.104 174.851 ;
     RECT  131.808 174.467 133.464 175.093 ;
     RECT  153.6 174.851 154.104 175.141 ;
     RECT  159 171.539 159.864 175.331 ;
     RECT  134.88 174.467 151.512 175.333 ;
     RECT  126.6 174.467 127.032 175.475 ;
     RECT  131.712 175.093 133.464 175.571 ;
     RECT  153.6 175.141 155.064 175.619 ;
     RECT  126.6 175.475 126.912 175.717 ;
     RECT  105 174.467 105.432 175.859 ;
     RECT  115.8 173.125 116.76 176.195 ;
     RECT  155.04 175.619 155.064 176.195 ;
     RECT  159 175.331 159.624 176.243 ;
     RECT  134.88 175.333 152.184 176.245 ;
     RECT  134.88 176.245 152.376 176.435 ;
     RECT  126 175.717 126.912 176.485 ;
     RECT  131.808 175.571 133.464 176.629 ;
     RECT  161.52 174.757 161.544 176.677 ;
     RECT  124.224 174.325 124.248 176.723 ;
     RECT  160.944 176.677 161.544 176.723 ;
     RECT  109.008 174.325 109.032 177.107 ;
     RECT  115.8 176.195 116.112 177.205 ;
     RECT  121.2 170.291 121.512 177.829 ;
     RECT  125.712 176.485 126.912 177.829 ;
     RECT  119.376 174.325 119.4 177.875 ;
     RECT  128.496 178.261 128.52 178.403 ;
     RECT  120.864 177.829 121.512 178.451 ;
     RECT  163.152 177.589 163.176 178.451 ;
     RECT  159 176.243 159.312 178.597 ;
     RECT  158.592 178.597 159.312 178.883 ;
     RECT  152.352 176.435 152.376 178.933 ;
     RECT  159 178.883 159.312 178.933 ;
     RECT  108.864 177.253 108.888 178.979 ;
     RECT  160.944 176.723 160.968 178.979 ;
     RECT  115.344 177.205 116.112 179.027 ;
     RECT  125.232 177.829 126.912 179.603 ;
     RECT  131.136 176.629 133.464 179.893 ;
     RECT  152.256 178.933 152.376 179.987 ;
     RECT  121.2 178.451 121.512 180.037 ;
     RECT  110.4 173.027 111.528 180.179 ;
     RECT  152.352 179.987 152.376 180.179 ;
     RECT  107.184 179.461 107.208 180.227 ;
     RECT  131.136 179.893 133.656 180.323 ;
     RECT  113.28 180.037 113.304 180.613 ;
     RECT  112.848 180.613 113.304 180.659 ;
     RECT  109.056 179.509 109.08 180.661 ;
     RECT  112.848 180.659 112.872 180.755 ;
     RECT  109.056 180.661 109.416 181.477 ;
     RECT  108.864 181.477 109.416 181.523 ;
     RECT  115.8 179.027 116.112 181.765 ;
     RECT  125.232 179.603 125.256 181.859 ;
     RECT  131.136 180.323 132.936 181.859 ;
     RECT  159 178.933 159.624 182.197 ;
     RECT  134.88 176.435 150.648 182.245 ;
     RECT  107.28 181.237 107.304 182.339 ;
     RECT  121.2 180.037 122.232 182.339 ;
     RECT  123.456 181.669 123.48 182.339 ;
     RECT  158.64 182.197 159.624 182.339 ;
     RECT  134.88 182.245 150.936 182.581 ;
     RECT  131.136 181.859 132.408 182.723 ;
     RECT  108.864 181.523 108.888 182.963 ;
     RECT  131.136 182.723 132.312 183.011 ;
     RECT  159 182.339 159.624 183.011 ;
     RECT  112.56 182.005 112.584 183.155 ;
     RECT  118.176 180.661 118.2 183.251 ;
     RECT  115.296 181.765 116.112 183.443 ;
     RECT  126.6 179.603 126.912 183.493 ;
     RECT  131.184 183.011 132.312 183.539 ;
     RECT  131.856 183.539 132.312 183.587 ;
     RECT  134.592 182.581 150.936 183.731 ;
     RECT  105 175.859 105.312 183.781 ;
     RECT  127.968 181.141 127.992 183.971 ;
     RECT  110.4 180.179 110.712 184.069 ;
     RECT  110.4 184.069 111.384 184.117 ;
     RECT  125.664 183.493 126.912 184.259 ;
     RECT  115.8 183.443 116.112 184.645 ;
     RECT  134.592 183.731 150.648 184.739 ;
     RECT  114.816 184.645 116.112 185.221 ;
     RECT  104.88 183.781 105.312 185.315 ;
     RECT  119.808 184.069 119.832 185.363 ;
     RECT  109.728 184.117 111.384 185.555 ;
     RECT  152.16 184.501 152.184 185.843 ;
     RECT  124.224 184.645 124.248 186.419 ;
     RECT  134.64 184.739 150.648 186.421 ;
     RECT  113.952 185.221 116.112 186.467 ;
     RECT  134.64 186.421 151.608 186.611 ;
     RECT  114.576 186.467 116.112 186.707 ;
     RECT  111.744 185.797 111.768 186.851 ;
     RECT  133.344 184.069 133.368 186.901 ;
     RECT  111.792 186.901 111.816 187.141 ;
     RECT  125.856 184.259 126.912 187.187 ;
     RECT  132 183.587 132.312 187.189 ;
     RECT  133.344 186.901 133.944 187.189 ;
     RECT  135.312 186.611 151.608 187.571 ;
     RECT  132 187.189 133.944 188.099 ;
     RECT  111.792 187.141 112.296 188.389 ;
     RECT  111.696 188.389 112.296 188.483 ;
     RECT  114.576 186.707 114.6 188.579 ;
     RECT  159 183.011 159.312 188.581 ;
     RECT  129.456 186.709 129.48 188.675 ;
     RECT  115.8 186.707 116.112 188.677 ;
     RECT  158.496 188.581 159.312 188.677 ;
     RECT  132 188.099 132.312 188.773 ;
     RECT  123.984 187.477 124.008 188.965 ;
     RECT  158.4 188.677 159.312 188.965 ;
     RECT  155.28 187.477 155.304 189.011 ;
     RECT  110.016 185.555 110.712 189.205 ;
     RECT  111.696 188.483 111.72 189.205 ;
     RECT  110.016 189.205 111.72 189.251 ;
     RECT  135.312 187.571 150.648 189.253 ;
     RECT  108.816 188.629 108.84 189.347 ;
     RECT  115.584 188.677 116.112 189.395 ;
     RECT  107.376 187.477 107.4 189.445 ;
     RECT  106.656 189.445 107.4 189.491 ;
     RECT  135.312 189.253 151.08 189.685 ;
     RECT  133.344 188.099 133.944 189.731 ;
     RECT  134.976 189.685 151.08 190.261 ;
     RECT  152.208 189.061 152.232 190.261 ;
     RECT  110.016 189.251 111.384 190.309 ;
     RECT  157.728 188.965 159.312 190.403 ;
     RECT  123.648 188.965 124.008 190.451 ;
     RECT  131.616 188.773 132.312 190.451 ;
     RECT  106.656 189.491 107.208 190.595 ;
     RECT  109.296 190.309 111.384 190.979 ;
     RECT  134.976 190.261 152.232 190.979 ;
     RECT  157.728 190.403 157.752 190.979 ;
     RECT  109.296 190.979 109.32 191.123 ;
     RECT  131.904 190.451 132.312 191.173 ;
     RECT  133.344 189.731 133.368 191.173 ;
     RECT  135.312 190.979 152.232 191.267 ;
     RECT  158.784 190.403 159.312 191.365 ;
     RECT  110.4 190.979 111.384 191.555 ;
     RECT  135.312 191.267 150.648 191.555 ;
     RECT  114.576 190.501 114.6 191.747 ;
     RECT  115.8 189.395 116.112 192.037 ;
     RECT  158.784 191.365 160.152 192.373 ;
     RECT  135.312 191.555 150.6 192.517 ;
     RECT  126.6 187.187 126.912 192.565 ;
     RECT  152.208 191.267 152.232 192.613 ;
     RECT  106.656 190.595 106.68 192.803 ;
     RECT  158.64 192.373 160.152 193.045 ;
     RECT  128.88 191.317 128.904 193.141 ;
     RECT  158.64 193.045 160.536 193.189 ;
     RECT  112.128 192.613 112.152 193.379 ;
     RECT  134.544 192.517 150.6 193.475 ;
     RECT  109.152 191.893 109.176 193.523 ;
     RECT  115.104 192.037 116.112 193.523 ;
     RECT  158.256 193.189 160.536 193.765 ;
     RECT  152.208 192.613 152.328 194.101 ;
     RECT  151.68 194.101 152.328 194.147 ;
     RECT  128.88 193.141 129 194.195 ;
     RECT  126.48 192.565 126.912 194.389 ;
     RECT  151.68 194.147 152.232 194.579 ;
     RECT  134.592 193.475 150.6 194.627 ;
     RECT  157.152 193.669 157.176 194.917 ;
     RECT  158.208 193.765 160.536 194.917 ;
     RECT  157.152 194.917 160.536 194.963 ;
     RECT  135.072 194.627 150.6 195.539 ;
     RECT  126.096 194.389 126.912 195.587 ;
     RECT  157.92 194.963 160.536 195.587 ;
     RECT  128.88 194.195 128.904 196.259 ;
     RECT  123.984 190.451 124.008 196.309 ;
     RECT  123.984 196.309 124.776 196.355 ;
     RECT  131.904 191.173 133.368 196.691 ;
     RECT  135.072 195.539 145.272 196.739 ;
     RECT  152.208 194.579 152.232 197.077 ;
     RECT  152.208 197.077 152.472 197.123 ;
     RECT  135.312 196.739 145.272 197.125 ;
     RECT  126.6 195.587 126.912 197.173 ;
     RECT  158.208 195.587 160.536 197.267 ;
     RECT  152.448 197.123 152.472 197.269 ;
     RECT  153.6 175.619 153.912 197.269 ;
     RECT  146.496 195.539 150.6 198.085 ;
     RECT  146.496 198.085 151.08 198.275 ;
     RECT  152.448 197.269 153.912 198.275 ;
     RECT  132 196.691 133.368 198.325 ;
     RECT  124.752 196.355 124.776 198.419 ;
     RECT  146.784 198.275 151.08 198.419 ;
     RECT  126.6 197.173 127.128 198.901 ;
     RECT  125.616 198.901 127.128 198.995 ;
     RECT  135.312 197.125 145.512 199.331 ;
     RECT  149.856 198.419 151.08 199.331 ;
     RECT  129.216 198.613 129.24 199.523 ;
     RECT  137.4 199.331 145.512 199.523 ;
     RECT  149.952 199.331 151.08 200.053 ;
     RECT  131.904 198.325 133.368 200.293 ;
     RECT  137.4 199.523 145.464 200.819 ;
     RECT  135.312 199.331 136.392 201.251 ;
     RECT  158.208 197.267 160.152 201.589 ;
     RECT  152.448 198.275 152.472 201.731 ;
     RECT  125.616 198.995 126.912 201.733 ;
     RECT  125.616 201.733 127.032 201.779 ;
     RECT  146.784 198.419 148.824 202.019 ;
     RECT  149.952 200.053 151.176 202.163 ;
     RECT  135.312 201.251 136.056 202.213 ;
     RECT  126.6 201.779 127.032 202.309 ;
     RECT  131.52 200.293 133.368 202.309 ;
     RECT  135.12 202.213 136.056 202.309 ;
     RECT  131.52 202.309 136.056 202.451 ;
     RECT  135.12 202.451 136.056 202.595 ;
     RECT  146.784 202.019 148.632 202.643 ;
     RECT  135.312 202.595 136.056 202.837 ;
     RECT  152.208 202.165 152.232 202.979 ;
     RECT  158.208 201.589 160.584 203.747 ;
     RECT  146.784 202.643 148.512 203.989 ;
     RECT  149.952 202.163 150.6 204.037 ;
     RECT  135.312 202.837 136.2 204.083 ;
     RECT  156.192 203.413 156.216 204.083 ;
     RECT  131.52 202.451 133.368 204.181 ;
     RECT  130.608 204.181 133.368 204.227 ;
     RECT  126.6 202.309 127.704 204.755 ;
     RECT  125.04 203.461 125.064 204.995 ;
     RECT  146.784 203.989 148.776 205.045 ;
     RECT  149.952 204.037 151.08 205.045 ;
     RECT  146.784 205.045 151.08 205.235 ;
     RECT  156.24 204.613 156.264 205.235 ;
     RECT  128.784 204.469 128.808 205.379 ;
     RECT  135.312 204.083 136.056 205.717 ;
     RECT  137.4 200.819 145.32 205.717 ;
     RECT  149.952 205.235 151.08 205.811 ;
     RECT  126.6 204.755 126.912 206.053 ;
     RECT  158.208 203.747 160.152 206.099 ;
     RECT  130.608 204.227 130.632 206.293 ;
     RECT  135.312 205.717 145.32 206.387 ;
     RECT  150.576 205.811 151.08 206.387 ;
     RECT  146.784 205.235 148.776 206.629 ;
     RECT  130.08 206.293 130.632 206.771 ;
     RECT  138.912 206.387 145.32 206.771 ;
     RECT  126.6 206.053 127.272 207.013 ;
     RECT  136.752 206.387 137.928 207.059 ;
     RECT  135.312 206.387 135.336 207.155 ;
     RECT  146.496 206.629 148.776 207.157 ;
     RECT  146.496 207.157 149.352 207.203 ;
     RECT  141.168 206.771 145.32 207.445 ;
     RECT  131.904 204.227 133.368 207.539 ;
     RECT  137.04 207.059 137.928 207.539 ;
     RECT  156.624 207.445 156.648 208.259 ;
     RECT  138.912 206.771 140.184 208.355 ;
     RECT  132 207.539 133.368 208.645 ;
     RECT  130.56 206.771 130.632 208.787 ;
     RECT  126.6 207.013 127.32 208.885 ;
     RECT  129.072 207.061 129.096 208.931 ;
     RECT  130.608 208.787 130.632 208.933 ;
     RECT  131.904 208.645 133.368 208.933 ;
     RECT  130.608 208.933 133.368 208.979 ;
     RECT  141.168 207.445 145.368 209.027 ;
     RECT  137.04 207.539 137.712 209.171 ;
     RECT  135.648 208.021 135.672 209.219 ;
     RECT  146.784 207.203 149.352 209.267 ;
     RECT  145.2 209.027 145.368 209.363 ;
     RECT  137.184 209.171 137.712 209.461 ;
     RECT  138.912 208.355 139.224 209.461 ;
     RECT  136.128 209.653 136.152 210.277 ;
     RECT  135.696 210.277 136.152 210.323 ;
     RECT  137.184 209.461 139.224 210.323 ;
     RECT  130.944 208.979 133.368 210.371 ;
     RECT  141.168 209.027 143.736 210.371 ;
     RECT  150.576 206.387 150.6 210.371 ;
     RECT  141.408 210.371 143.736 210.373 ;
     RECT  126.144 208.885 127.8 210.419 ;
     RECT  141.408 210.373 143.88 210.611 ;
     RECT  135.696 210.323 135.72 210.803 ;
     RECT  158.208 206.099 159.912 210.947 ;
     RECT  126.6 210.419 127.8 210.995 ;
     RECT  141.408 210.611 143.736 211.235 ;
     RECT  137.4 210.323 139.224 211.283 ;
     RECT  141.408 211.235 143.592 211.283 ;
     RECT  132 210.371 133.368 211.523 ;
     RECT  126.6 210.995 127.32 211.907 ;
     RECT  130.944 210.371 130.968 212.005 ;
     RECT  132 211.523 132.312 212.005 ;
     RECT  141.648 211.283 143.592 212.051 ;
     RECT  145.2 209.363 145.32 212.099 ;
     RECT  128.688 211.861 128.712 212.581 ;
     RECT  139.2 211.283 139.224 212.581 ;
     RECT  139.2 212.581 139.56 212.675 ;
     RECT  152.064 204.565 152.088 212.675 ;
     RECT  158.208 210.947 159.312 212.675 ;
     RECT  145.2 212.099 145.224 212.965 ;
     RECT  156.144 211.861 156.168 213.107 ;
     RECT  141.696 212.051 143.592 213.109 ;
     RECT  137.4 211.283 137.712 213.157 ;
     RECT  130.944 212.005 132.312 214.019 ;
     RECT  130.944 214.019 130.968 214.069 ;
     RECT  130.656 214.069 130.968 214.115 ;
     RECT  128.688 212.581 128.808 214.355 ;
     RECT  136.8 213.157 137.712 214.499 ;
     RECT  141.648 213.109 143.592 214.549 ;
     RECT  141.648 214.549 143.688 214.837 ;
     RECT  144.72 212.965 145.224 214.837 ;
     RECT  133.344 211.523 133.368 215.269 ;
     RECT  137.4 214.499 137.712 215.365 ;
     RECT  133.344 215.269 133.656 215.699 ;
     RECT  139.536 212.675 139.56 215.795 ;
     RECT  137.4 215.365 137.832 216.179 ;
     RECT  146.784 209.267 148.776 216.373 ;
     RECT  141.648 214.837 145.224 216.659 ;
     RECT  146.784 216.373 149.304 216.659 ;
     RECT  139.44 216.565 139.464 217.379 ;
     RECT  148.2 216.659 149.304 217.715 ;
     RECT  130.656 214.115 130.68 217.765 ;
     RECT  132 214.019 132.312 217.765 ;
     RECT  128.688 214.355 128.712 217.811 ;
     RECT  150.576 216.565 150.6 218.197 ;
     RECT  130.656 217.765 132.312 218.291 ;
     RECT  149.856 218.197 150.6 218.339 ;
     RECT  146.784 216.659 146.808 218.869 ;
     RECT  148.2 217.715 148.776 218.869 ;
     RECT  149.856 218.339 149.88 218.869 ;
     RECT  151.92 215.269 151.944 218.869 ;
     RECT  141.696 216.659 145.224 219.397 ;
     RECT  151.2 218.869 151.944 219.443 ;
     RECT  151.92 219.443 151.944 219.491 ;
     RECT  132 218.291 132.312 219.685 ;
     RECT  141.696 219.397 145.416 219.875 ;
     RECT  148.2 218.869 149.88 219.875 ;
     RECT  130.656 218.291 130.68 220.021 ;
     RECT  138.96 219.349 138.984 220.115 ;
     RECT  137.4 216.179 137.712 220.213 ;
     RECT  131.808 219.685 132.312 220.499 ;
     RECT  135.84 216.565 135.864 220.549 ;
     RECT  130.08 220.021 130.68 220.979 ;
     RECT  157.296 219.397 157.32 220.979 ;
     RECT  135.648 220.549 135.864 221.459 ;
     RECT  148.2 219.875 149.832 221.507 ;
     RECT  137.4 220.213 137.832 221.795 ;
     RECT  141.696 219.875 143.592 221.795 ;
     RECT  144.768 219.875 145.416 222.035 ;
     RECT  135.84 221.459 135.864 222.323 ;
     RECT  142.08 221.795 143.592 222.371 ;
     RECT  146.784 218.869 146.904 222.373 ;
     RECT  139.92 222.229 139.944 222.899 ;
     RECT  142.128 222.371 143.592 222.899 ;
     RECT  130.656 220.979 130.68 223.235 ;
     RECT  146.784 222.373 147.048 223.331 ;
     RECT  153.6 198.275 153.912 223.525 ;
     RECT  153.36 223.525 153.912 223.715 ;
     RECT  144.768 222.035 145.224 223.957 ;
     RECT  144.768 223.957 145.272 224.051 ;
     RECT  146.784 223.331 146.808 224.051 ;
     RECT  139.872 223.189 139.896 224.291 ;
     RECT  149.808 221.507 149.832 224.771 ;
     RECT  132 220.499 132.312 225.109 ;
     RECT  145.2 224.051 145.272 225.781 ;
     RECT  142.128 222.899 143.256 225.877 ;
     RECT  145.2 225.781 145.368 225.877 ;
     RECT  141.984 225.877 143.256 226.355 ;
     RECT  148.2 221.507 148.512 226.693 ;
     RECT  134.88 226.261 134.904 227.171 ;
     RECT  133.344 215.699 133.368 227.365 ;
     RECT  131.808 225.109 132.312 227.459 ;
     RECT  141.984 226.355 143.112 227.941 ;
     RECT  147.456 226.693 148.512 228.179 ;
     RECT  137.4 221.795 137.712 228.517 ;
     RECT  139.104 225.733 139.128 228.517 ;
     RECT  137.4 228.517 139.128 228.563 ;
     RECT  145.008 225.877 145.368 228.611 ;
     RECT  141.84 227.941 143.112 228.755 ;
     RECT  141.936 228.755 143.112 229.139 ;
     RECT  133.344 227.365 133.704 229.283 ;
     RECT  135.12 227.413 135.144 229.283 ;
     RECT  145.2 228.611 145.368 229.523 ;
     RECT  145.2 229.523 145.224 229.669 ;
     RECT  145.008 229.669 145.224 230.675 ;
     RECT  137.4 228.563 138.552 231.011 ;
     RECT  139.92 230.773 139.944 231.347 ;
     RECT  135.744 229.285 135.768 231.491 ;
     RECT  146.688 230.821 146.712 232.019 ;
     RECT  142.128 229.139 143.112 232.501 ;
     RECT  140.208 232.357 140.232 233.075 ;
     RECT  148.2 228.179 148.512 233.077 ;
     RECT  139.056 231.397 139.08 233.459 ;
     RECT  142.128 232.501 143.688 233.459 ;
     RECT  142.128 233.459 143.352 233.653 ;
     RECT  141.888 233.653 143.352 234.563 ;
     RECT  145.2 230.675 145.224 234.899 ;
     RECT  141.888 234.563 143.112 234.995 ;
     RECT  147.312 233.077 148.512 235.475 ;
     RECT  139.008 234.565 139.032 235.861 ;
     RECT  139.008 235.861 139.944 235.907 ;
     RECT  142.128 234.995 143.112 236.627 ;
     RECT  139.92 235.907 139.944 236.965 ;
     RECT  139.92 236.965 140.76 237.011 ;
     RECT  142.176 236.627 143.112 237.011 ;
     RECT  145.056 236.533 145.08 237.779 ;
     RECT  142.8 237.011 143.112 237.781 ;
     RECT  140.736 237.011 140.76 238.451 ;
     RECT  142.8 237.781 143.832 239.939 ;
     RECT  132 227.459 132.312 257.029 ;
     RECT  133.344 229.283 133.368 257.029 ;
     RECT  132 257.029 133.368 272.483 ;
     RECT  2.4 2.151 2.712 369.369 ;
     RECT  7.8 2.151 8.112 369.369 ;
     RECT  13.2 2.151 13.512 369.369 ;
     RECT  18.6 2.151 18.912 369.369 ;
     RECT  24 2.151 24.312 369.369 ;
     RECT  29.4 2.151 29.712 369.369 ;
     RECT  34.8 2.151 35.112 369.369 ;
     RECT  40.2 2.151 40.512 369.369 ;
     RECT  45.6 2.151 45.912 369.369 ;
     RECT  51 2.151 51.312 369.369 ;
     RECT  56.4 2.151 56.712 369.369 ;
     RECT  61.8 2.151 62.112 369.369 ;
     RECT  67.2 2.151 67.512 369.369 ;
     RECT  72.6 2.151 72.912 369.369 ;
     RECT  78 2.151 78.312 369.369 ;
     RECT  83.4 2.151 83.712 369.369 ;
     RECT  88.8 2.151 89.112 369.369 ;
     RECT  94.2 2.151 94.512 369.369 ;
     RECT  99.6 2.151 99.912 369.369 ;
     RECT  105 185.315 105.312 369.369 ;
     RECT  110.4 191.555 110.712 369.369 ;
     RECT  115.8 193.523 116.112 369.369 ;
     RECT  121.2 182.339 121.512 369.369 ;
     RECT  126.6 211.907 126.912 369.369 ;
     RECT  137.4 231.011 137.712 369.369 ;
     RECT  142.8 239.939 143.112 369.369 ;
     RECT  148.2 235.475 148.512 369.369 ;
     RECT  153.6 223.715 153.912 369.369 ;
     RECT  159 212.675 159.312 369.369 ;
     RECT  164.4 2.151 164.712 369.369 ;
     RECT  169.8 2.151 170.112 369.369 ;
     RECT  175.2 2.151 175.512 369.369 ;
     RECT  180.6 2.151 180.912 369.369 ;
     RECT  186 2.151 186.312 369.369 ;
     RECT  191.4 2.151 191.712 369.369 ;
     RECT  196.8 2.151 197.112 369.369 ;
     RECT  202.2 2.151 202.512 369.369 ;
     RECT  207.6 2.151 207.912 369.369 ;
     RECT  213 2.151 213.312 369.369 ;
     RECT  218.4 2.151 218.712 369.369 ;
     RECT  223.8 2.151 224.112 369.369 ;
     RECT  229.2 2.151 229.512 369.369 ;
     RECT  234.6 2.151 234.912 369.369 ;
     RECT  240 2.151 240.312 369.369 ;
     RECT  245.4 2.151 245.712 369.369 ;
     RECT  2.4 369.369 2.52 369.383 ;
     RECT  7.8 369.369 7.92 369.383 ;
     RECT  13.2 369.369 13.32 369.383 ;
     RECT  18.6 369.369 18.72 369.383 ;
     RECT  24 369.369 24.12 369.383 ;
     RECT  29.4 369.369 29.52 369.383 ;
     RECT  34.8 369.369 34.92 369.383 ;
     RECT  40.2 369.369 40.32 369.383 ;
     RECT  45.6 369.369 45.72 369.383 ;
     RECT  51 369.369 51.12 369.383 ;
     RECT  56.4 369.369 56.52 369.383 ;
     RECT  61.8 369.369 61.92 369.383 ;
     RECT  67.2 369.369 67.32 369.383 ;
     RECT  72.6 369.369 72.72 369.383 ;
     RECT  78 369.369 78.12 369.383 ;
     RECT  83.4 369.369 83.52 369.383 ;
     RECT  88.8 369.369 88.92 369.383 ;
     RECT  94.2 369.369 94.32 369.383 ;
     RECT  99.6 369.369 99.72 369.383 ;
     RECT  105 369.369 105.12 369.383 ;
     RECT  110.4 369.369 110.52 369.383 ;
     RECT  115.8 369.369 115.92 369.383 ;
     RECT  121.2 369.369 121.32 369.383 ;
     RECT  126.6 369.369 126.72 369.383 ;
     RECT  132 272.483 132.552 369.383 ;
     RECT  137.4 369.369 137.52 369.383 ;
     RECT  142.8 369.369 142.92 369.383 ;
     RECT  148.2 369.369 148.32 369.383 ;
     RECT  153.6 369.369 153.72 369.383 ;
     RECT  159 369.369 159.12 369.383 ;
     RECT  164.4 369.369 164.52 369.383 ;
     RECT  169.8 369.369 169.92 369.383 ;
     RECT  175.2 369.369 175.32 369.383 ;
     RECT  180.6 369.369 180.72 369.383 ;
     RECT  186 369.369 186.12 369.383 ;
     RECT  191.4 369.369 191.52 369.383 ;
     RECT  196.8 369.369 196.92 369.383 ;
     RECT  202.2 369.369 202.32 369.383 ;
     RECT  207.6 369.369 207.72 369.383 ;
     RECT  213 369.369 213.12 369.383 ;
     RECT  218.4 369.369 218.52 369.383 ;
     RECT  223.8 369.369 223.92 369.383 ;
     RECT  229.2 369.369 229.32 369.383 ;
     RECT  234.6 369.369 234.72 369.383 ;
     RECT  240 369.369 240.12 369.383 ;
     RECT  245.4 369.369 245.52 369.383 ;
     RECT  132.432 369.383 132.552 370.453 ;
     RECT  132.144 370.453 132.552 371.315 ;
     RECT  132.144 371.315 132.456 371.472 ;
  END
END ot_qwen_ctrl_pc
END LIBRARY
